VERSION 5.8 ;
BUSBITCHARS "[]" ;
DIVIDERCHAR "/" ;
UNITS
    DATABASE MICRONS 1000 ;
END UNITS

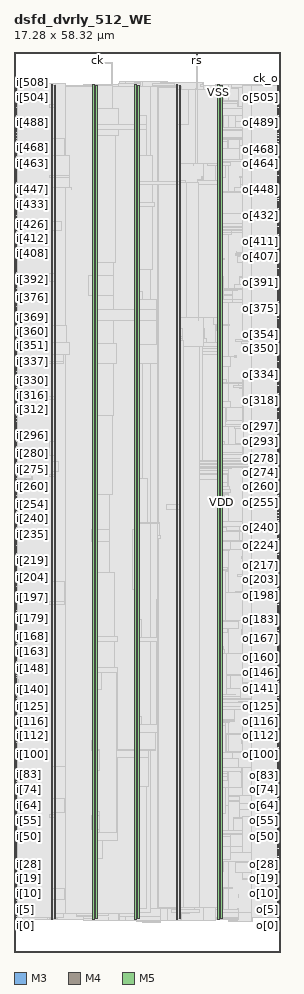
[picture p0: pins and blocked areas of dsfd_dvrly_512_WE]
MACRO dsfd_dvrly_512_WE
  FOREIGN dsfd_dvrly_512_WE 0 0 ;
  CLASS BLOCK ;
  SIZE 17.28 BY 58.32 ;
  PIN ck
    DIRECTION INPUT ;
    USE SIGNAL ;
    PORT
      LAYER M3 ;
        RECT  5.4 58.176 5.418 58.32 ;
    END
  END ck
  PIN ck_o
    DIRECTION OUTPUT ;
    USE SIGNAL ;
    PORT
      LAYER M4 ;
        RECT  17.088 56.112 17.28 56.136 ;
    END
  END ck_o
  PIN i[0]
    DIRECTION INPUT ;
    USE SIGNAL ;
    PORT
      LAYER M4 ;
        RECT  0 2.208 0.192 2.232 ;
    END
  END i[0]
  PIN i[100]
    DIRECTION INPUT ;
    USE SIGNAL ;
    PORT
      LAYER M4 ;
        RECT  0 12.768 0.192 12.792 ;
    END
  END i[100]
  PIN i[101]
    DIRECTION INPUT ;
    USE SIGNAL ;
    PORT
      LAYER M4 ;
        RECT  0 12.864 0.192 12.888 ;
    END
  END i[101]
  PIN i[102]
    DIRECTION INPUT ;
    USE SIGNAL ;
    PORT
      LAYER M4 ;
        RECT  0 12.96 0.192 12.984 ;
    END
  END i[102]
  PIN i[103]
    DIRECTION INPUT ;
    USE SIGNAL ;
    PORT
      LAYER M4 ;
        RECT  0 13.104 0.192 13.128 ;
    END
  END i[103]
  PIN i[104]
    DIRECTION INPUT ;
    USE SIGNAL ;
    PORT
      LAYER M4 ;
        RECT  0 13.2 0.192 13.224 ;
    END
  END i[104]
  PIN i[105]
    DIRECTION INPUT ;
    USE SIGNAL ;
    PORT
      LAYER M4 ;
        RECT  0 13.296 0.192 13.32 ;
    END
  END i[105]
  PIN i[106]
    DIRECTION INPUT ;
    USE SIGNAL ;
    PORT
      LAYER M4 ;
        RECT  0 13.392 0.192 13.416 ;
    END
  END i[106]
  PIN i[107]
    DIRECTION INPUT ;
    USE SIGNAL ;
    PORT
      LAYER M4 ;
        RECT  0 13.488 0.192 13.512 ;
    END
  END i[107]
  PIN i[108]
    DIRECTION INPUT ;
    USE SIGNAL ;
    PORT
      LAYER M4 ;
        RECT  0 13.632 0.192 13.656 ;
    END
  END i[108]
  PIN i[109]
    DIRECTION INPUT ;
    USE SIGNAL ;
    PORT
      LAYER M4 ;
        RECT  0 13.728 0.192 13.752 ;
    END
  END i[109]
  PIN i[10]
    DIRECTION INPUT ;
    USE SIGNAL ;
    PORT
      LAYER M4 ;
        RECT  0 3.264 0.192 3.288 ;
    END
  END i[10]
  PIN i[110]
    DIRECTION INPUT ;
    USE SIGNAL ;
    PORT
      LAYER M4 ;
        RECT  0 13.824 0.192 13.848 ;
    END
  END i[110]
  PIN i[111]
    DIRECTION INPUT ;
    USE SIGNAL ;
    PORT
      LAYER M4 ;
        RECT  0 13.92 0.192 13.944 ;
    END
  END i[111]
  PIN i[112]
    DIRECTION INPUT ;
    USE SIGNAL ;
    PORT
      LAYER M4 ;
        RECT  0 14.016 0.192 14.04 ;
    END
  END i[112]
  PIN i[113]
    DIRECTION INPUT ;
    USE SIGNAL ;
    PORT
      LAYER M4 ;
        RECT  0 14.16 0.192 14.184 ;
    END
  END i[113]
  PIN i[114]
    DIRECTION INPUT ;
    USE SIGNAL ;
    PORT
      LAYER M4 ;
        RECT  0 14.256 0.192 14.28 ;
    END
  END i[114]
  PIN i[115]
    DIRECTION INPUT ;
    USE SIGNAL ;
    PORT
      LAYER M4 ;
        RECT  0 14.352 0.192 14.376 ;
    END
  END i[115]
  PIN i[116]
    DIRECTION INPUT ;
    USE SIGNAL ;
    PORT
      LAYER M4 ;
        RECT  0 14.448 0.192 14.472 ;
    END
  END i[116]
  PIN i[117]
    DIRECTION INPUT ;
    USE SIGNAL ;
    PORT
      LAYER M4 ;
        RECT  0 14.544 0.192 14.568 ;
    END
  END i[117]
  PIN i[118]
    DIRECTION INPUT ;
    USE SIGNAL ;
    PORT
      LAYER M4 ;
        RECT  0 14.688 0.192 14.712 ;
    END
  END i[118]
  PIN i[119]
    DIRECTION INPUT ;
    USE SIGNAL ;
    PORT
      LAYER M4 ;
        RECT  0 14.784 0.192 14.808 ;
    END
  END i[119]
  PIN i[11]
    DIRECTION INPUT ;
    USE SIGNAL ;
    PORT
      LAYER M4 ;
        RECT  0 3.408 0.192 3.432 ;
    END
  END i[11]
  PIN i[120]
    DIRECTION INPUT ;
    USE SIGNAL ;
    PORT
      LAYER M4 ;
        RECT  0 14.88 0.192 14.904 ;
    END
  END i[120]
  PIN i[121]
    DIRECTION INPUT ;
    USE SIGNAL ;
    PORT
      LAYER M4 ;
        RECT  0 14.976 0.192 15 ;
    END
  END i[121]
  PIN i[122]
    DIRECTION INPUT ;
    USE SIGNAL ;
    PORT
      LAYER M4 ;
        RECT  0 15.072 0.192 15.096 ;
    END
  END i[122]
  PIN i[123]
    DIRECTION INPUT ;
    USE SIGNAL ;
    PORT
      LAYER M4 ;
        RECT  0 15.216 0.192 15.24 ;
    END
  END i[123]
  PIN i[124]
    DIRECTION INPUT ;
    USE SIGNAL ;
    PORT
      LAYER M4 ;
        RECT  0 15.312 0.192 15.336 ;
    END
  END i[124]
  PIN i[125]
    DIRECTION INPUT ;
    USE SIGNAL ;
    PORT
      LAYER M4 ;
        RECT  0 15.408 0.192 15.432 ;
    END
  END i[125]
  PIN i[126]
    DIRECTION INPUT ;
    USE SIGNAL ;
    PORT
      LAYER M4 ;
        RECT  0 15.504 0.192 15.528 ;
    END
  END i[126]
  PIN i[127]
    DIRECTION INPUT ;
    USE SIGNAL ;
    PORT
      LAYER M4 ;
        RECT  0 15.6 0.192 15.624 ;
    END
  END i[127]
  PIN i[128]
    DIRECTION INPUT ;
    USE SIGNAL ;
    PORT
      LAYER M4 ;
        RECT  0 15.744 0.192 15.768 ;
    END
  END i[128]
  PIN i[129]
    DIRECTION INPUT ;
    USE SIGNAL ;
    PORT
      LAYER M4 ;
        RECT  0 15.84 0.192 15.864 ;
    END
  END i[129]
  PIN i[12]
    DIRECTION INPUT ;
    USE SIGNAL ;
    PORT
      LAYER M4 ;
        RECT  0 3.504 0.192 3.528 ;
    END
  END i[12]
  PIN i[130]
    DIRECTION INPUT ;
    USE SIGNAL ;
    PORT
      LAYER M4 ;
        RECT  0 15.936 0.192 15.96 ;
    END
  END i[130]
  PIN i[131]
    DIRECTION INPUT ;
    USE SIGNAL ;
    PORT
      LAYER M4 ;
        RECT  0 16.032 0.192 16.056 ;
    END
  END i[131]
  PIN i[132]
    DIRECTION INPUT ;
    USE SIGNAL ;
    PORT
      LAYER M4 ;
        RECT  0 16.128 0.192 16.152 ;
    END
  END i[132]
  PIN i[133]
    DIRECTION INPUT ;
    USE SIGNAL ;
    PORT
      LAYER M4 ;
        RECT  0 16.272 0.192 16.296 ;
    END
  END i[133]
  PIN i[134]
    DIRECTION INPUT ;
    USE SIGNAL ;
    PORT
      LAYER M4 ;
        RECT  0 16.368 0.192 16.392 ;
    END
  END i[134]
  PIN i[135]
    DIRECTION INPUT ;
    USE SIGNAL ;
    PORT
      LAYER M4 ;
        RECT  0 16.464 0.192 16.488 ;
    END
  END i[135]
  PIN i[136]
    DIRECTION INPUT ;
    USE SIGNAL ;
    PORT
      LAYER M4 ;
        RECT  0 16.56 0.192 16.584 ;
    END
  END i[136]
  PIN i[137]
    DIRECTION INPUT ;
    USE SIGNAL ;
    PORT
      LAYER M4 ;
        RECT  0 16.656 0.192 16.68 ;
    END
  END i[137]
  PIN i[138]
    DIRECTION INPUT ;
    USE SIGNAL ;
    PORT
      LAYER M4 ;
        RECT  0 16.8 0.192 16.824 ;
    END
  END i[138]
  PIN i[139]
    DIRECTION INPUT ;
    USE SIGNAL ;
    PORT
      LAYER M4 ;
        RECT  0 16.896 0.192 16.92 ;
    END
  END i[139]
  PIN i[13]
    DIRECTION INPUT ;
    USE SIGNAL ;
    PORT
      LAYER M4 ;
        RECT  0 3.6 0.192 3.624 ;
    END
  END i[13]
  PIN i[140]
    DIRECTION INPUT ;
    USE SIGNAL ;
    PORT
      LAYER M4 ;
        RECT  0 16.992 0.192 17.016 ;
    END
  END i[140]
  PIN i[141]
    DIRECTION INPUT ;
    USE SIGNAL ;
    PORT
      LAYER M4 ;
        RECT  0 17.088 0.192 17.112 ;
    END
  END i[141]
  PIN i[142]
    DIRECTION INPUT ;
    USE SIGNAL ;
    PORT
      LAYER M4 ;
        RECT  0 17.184 0.192 17.208 ;
    END
  END i[142]
  PIN i[143]
    DIRECTION INPUT ;
    USE SIGNAL ;
    PORT
      LAYER M4 ;
        RECT  0 17.328 0.192 17.352 ;
    END
  END i[143]
  PIN i[144]
    DIRECTION INPUT ;
    USE SIGNAL ;
    PORT
      LAYER M4 ;
        RECT  0 17.424 0.192 17.448 ;
    END
  END i[144]
  PIN i[145]
    DIRECTION INPUT ;
    USE SIGNAL ;
    PORT
      LAYER M4 ;
        RECT  0 17.52 0.192 17.544 ;
    END
  END i[145]
  PIN i[146]
    DIRECTION INPUT ;
    USE SIGNAL ;
    PORT
      LAYER M4 ;
        RECT  0 17.616 0.192 17.64 ;
    END
  END i[146]
  PIN i[147]
    DIRECTION INPUT ;
    USE SIGNAL ;
    PORT
      LAYER M4 ;
        RECT  0 17.712 0.192 17.736 ;
    END
  END i[147]
  PIN i[148]
    DIRECTION INPUT ;
    USE SIGNAL ;
    PORT
      LAYER M4 ;
        RECT  0 17.856 0.192 17.88 ;
    END
  END i[148]
  PIN i[149]
    DIRECTION INPUT ;
    USE SIGNAL ;
    PORT
      LAYER M4 ;
        RECT  0 17.952 0.192 17.976 ;
    END
  END i[149]
  PIN i[14]
    DIRECTION INPUT ;
    USE SIGNAL ;
    PORT
      LAYER M4 ;
        RECT  0 3.696 0.192 3.72 ;
    END
  END i[14]
  PIN i[150]
    DIRECTION INPUT ;
    USE SIGNAL ;
    PORT
      LAYER M4 ;
        RECT  0 18.048 0.192 18.072 ;
    END
  END i[150]
  PIN i[151]
    DIRECTION INPUT ;
    USE SIGNAL ;
    PORT
      LAYER M4 ;
        RECT  0 18.144 0.192 18.168 ;
    END
  END i[151]
  PIN i[152]
    DIRECTION INPUT ;
    USE SIGNAL ;
    PORT
      LAYER M4 ;
        RECT  0 18.24 0.192 18.264 ;
    END
  END i[152]
  PIN i[153]
    DIRECTION INPUT ;
    USE SIGNAL ;
    PORT
      LAYER M4 ;
        RECT  0 18.384 0.192 18.408 ;
    END
  END i[153]
  PIN i[154]
    DIRECTION INPUT ;
    USE SIGNAL ;
    PORT
      LAYER M4 ;
        RECT  0 18.48 0.192 18.504 ;
    END
  END i[154]
  PIN i[155]
    DIRECTION INPUT ;
    USE SIGNAL ;
    PORT
      LAYER M4 ;
        RECT  0 18.576 0.192 18.6 ;
    END
  END i[155]
  PIN i[156]
    DIRECTION INPUT ;
    USE SIGNAL ;
    PORT
      LAYER M4 ;
        RECT  0 18.672 0.192 18.696 ;
    END
  END i[156]
  PIN i[157]
    DIRECTION INPUT ;
    USE SIGNAL ;
    PORT
      LAYER M4 ;
        RECT  0 18.768 0.192 18.792 ;
    END
  END i[157]
  PIN i[158]
    DIRECTION INPUT ;
    USE SIGNAL ;
    PORT
      LAYER M4 ;
        RECT  0 18.912 0.192 18.936 ;
    END
  END i[158]
  PIN i[159]
    DIRECTION INPUT ;
    USE SIGNAL ;
    PORT
      LAYER M4 ;
        RECT  0 19.008 0.192 19.032 ;
    END
  END i[159]
  PIN i[15]
    DIRECTION INPUT ;
    USE SIGNAL ;
    PORT
      LAYER M4 ;
        RECT  0 3.792 0.192 3.816 ;
    END
  END i[15]
  PIN i[160]
    DIRECTION INPUT ;
    USE SIGNAL ;
    PORT
      LAYER M4 ;
        RECT  0 19.104 0.192 19.128 ;
    END
  END i[160]
  PIN i[161]
    DIRECTION INPUT ;
    USE SIGNAL ;
    PORT
      LAYER M4 ;
        RECT  0 19.2 0.192 19.224 ;
    END
  END i[161]
  PIN i[162]
    DIRECTION INPUT ;
    USE SIGNAL ;
    PORT
      LAYER M4 ;
        RECT  0 19.296 0.192 19.32 ;
    END
  END i[162]
  PIN i[163]
    DIRECTION INPUT ;
    USE SIGNAL ;
    PORT
      LAYER M4 ;
        RECT  0 19.44 0.192 19.464 ;
    END
  END i[163]
  PIN i[164]
    DIRECTION INPUT ;
    USE SIGNAL ;
    PORT
      LAYER M4 ;
        RECT  0 19.536 0.192 19.56 ;
    END
  END i[164]
  PIN i[165]
    DIRECTION INPUT ;
    USE SIGNAL ;
    PORT
      LAYER M4 ;
        RECT  0 19.632 0.192 19.656 ;
    END
  END i[165]
  PIN i[166]
    DIRECTION INPUT ;
    USE SIGNAL ;
    PORT
      LAYER M4 ;
        RECT  0 19.728 0.192 19.752 ;
    END
  END i[166]
  PIN i[167]
    DIRECTION INPUT ;
    USE SIGNAL ;
    PORT
      LAYER M4 ;
        RECT  0 19.824 0.192 19.848 ;
    END
  END i[167]
  PIN i[168]
    DIRECTION INPUT ;
    USE SIGNAL ;
    PORT
      LAYER M4 ;
        RECT  0 19.92 0.192 19.944 ;
    END
  END i[168]
  PIN i[169]
    DIRECTION INPUT ;
    USE SIGNAL ;
    PORT
      LAYER M4 ;
        RECT  0 20.064 0.192 20.088 ;
    END
  END i[169]
  PIN i[16]
    DIRECTION INPUT ;
    USE SIGNAL ;
    PORT
      LAYER M4 ;
        RECT  0 3.936 0.192 3.96 ;
    END
  END i[16]
  PIN i[170]
    DIRECTION INPUT ;
    USE SIGNAL ;
    PORT
      LAYER M4 ;
        RECT  0 20.16 0.192 20.184 ;
    END
  END i[170]
  PIN i[171]
    DIRECTION INPUT ;
    USE SIGNAL ;
    PORT
      LAYER M4 ;
        RECT  0 20.256 0.192 20.28 ;
    END
  END i[171]
  PIN i[172]
    DIRECTION INPUT ;
    USE SIGNAL ;
    PORT
      LAYER M4 ;
        RECT  0 20.352 0.192 20.376 ;
    END
  END i[172]
  PIN i[173]
    DIRECTION INPUT ;
    USE SIGNAL ;
    PORT
      LAYER M4 ;
        RECT  0 20.448 0.192 20.472 ;
    END
  END i[173]
  PIN i[174]
    DIRECTION INPUT ;
    USE SIGNAL ;
    PORT
      LAYER M4 ;
        RECT  0 20.592 0.192 20.616 ;
    END
  END i[174]
  PIN i[175]
    DIRECTION INPUT ;
    USE SIGNAL ;
    PORT
      LAYER M4 ;
        RECT  0 20.688 0.192 20.712 ;
    END
  END i[175]
  PIN i[176]
    DIRECTION INPUT ;
    USE SIGNAL ;
    PORT
      LAYER M4 ;
        RECT  0 20.784 0.192 20.808 ;
    END
  END i[176]
  PIN i[177]
    DIRECTION INPUT ;
    USE SIGNAL ;
    PORT
      LAYER M4 ;
        RECT  0 20.88 0.192 20.904 ;
    END
  END i[177]
  PIN i[178]
    DIRECTION INPUT ;
    USE SIGNAL ;
    PORT
      LAYER M4 ;
        RECT  0 20.976 0.192 21 ;
    END
  END i[178]
  PIN i[179]
    DIRECTION INPUT ;
    USE SIGNAL ;
    PORT
      LAYER M4 ;
        RECT  0 21.12 0.192 21.144 ;
    END
  END i[179]
  PIN i[17]
    DIRECTION INPUT ;
    USE SIGNAL ;
    PORT
      LAYER M4 ;
        RECT  0 4.032 0.192 4.056 ;
    END
  END i[17]
  PIN i[180]
    DIRECTION INPUT ;
    USE SIGNAL ;
    PORT
      LAYER M4 ;
        RECT  0 21.216 0.192 21.24 ;
    END
  END i[180]
  PIN i[181]
    DIRECTION INPUT ;
    USE SIGNAL ;
    PORT
      LAYER M4 ;
        RECT  0 21.312 0.192 21.336 ;
    END
  END i[181]
  PIN i[182]
    DIRECTION INPUT ;
    USE SIGNAL ;
    PORT
      LAYER M4 ;
        RECT  0 21.408 0.192 21.432 ;
    END
  END i[182]
  PIN i[183]
    DIRECTION INPUT ;
    USE SIGNAL ;
    PORT
      LAYER M4 ;
        RECT  0 21.504 0.192 21.528 ;
    END
  END i[183]
  PIN i[184]
    DIRECTION INPUT ;
    USE SIGNAL ;
    PORT
      LAYER M4 ;
        RECT  0 21.648 0.192 21.672 ;
    END
  END i[184]
  PIN i[185]
    DIRECTION INPUT ;
    USE SIGNAL ;
    PORT
      LAYER M4 ;
        RECT  0 21.744 0.192 21.768 ;
    END
  END i[185]
  PIN i[186]
    DIRECTION INPUT ;
    USE SIGNAL ;
    PORT
      LAYER M4 ;
        RECT  0 21.84 0.192 21.864 ;
    END
  END i[186]
  PIN i[187]
    DIRECTION INPUT ;
    USE SIGNAL ;
    PORT
      LAYER M4 ;
        RECT  0 21.936 0.192 21.96 ;
    END
  END i[187]
  PIN i[188]
    DIRECTION INPUT ;
    USE SIGNAL ;
    PORT
      LAYER M4 ;
        RECT  0 22.032 0.192 22.056 ;
    END
  END i[188]
  PIN i[189]
    DIRECTION INPUT ;
    USE SIGNAL ;
    PORT
      LAYER M4 ;
        RECT  0 22.176 0.192 22.2 ;
    END
  END i[189]
  PIN i[18]
    DIRECTION INPUT ;
    USE SIGNAL ;
    PORT
      LAYER M4 ;
        RECT  0 4.128 0.192 4.152 ;
    END
  END i[18]
  PIN i[190]
    DIRECTION INPUT ;
    USE SIGNAL ;
    PORT
      LAYER M4 ;
        RECT  0 22.272 0.192 22.296 ;
    END
  END i[190]
  PIN i[191]
    DIRECTION INPUT ;
    USE SIGNAL ;
    PORT
      LAYER M4 ;
        RECT  0 22.368 0.192 22.392 ;
    END
  END i[191]
  PIN i[192]
    DIRECTION INPUT ;
    USE SIGNAL ;
    PORT
      LAYER M4 ;
        RECT  0 22.464 0.192 22.488 ;
    END
  END i[192]
  PIN i[193]
    DIRECTION INPUT ;
    USE SIGNAL ;
    PORT
      LAYER M4 ;
        RECT  0 22.56 0.192 22.584 ;
    END
  END i[193]
  PIN i[194]
    DIRECTION INPUT ;
    USE SIGNAL ;
    PORT
      LAYER M4 ;
        RECT  0 22.704 0.192 22.728 ;
    END
  END i[194]
  PIN i[195]
    DIRECTION INPUT ;
    USE SIGNAL ;
    PORT
      LAYER M4 ;
        RECT  0 22.8 0.192 22.824 ;
    END
  END i[195]
  PIN i[196]
    DIRECTION INPUT ;
    USE SIGNAL ;
    PORT
      LAYER M4 ;
        RECT  0 22.896 0.192 22.92 ;
    END
  END i[196]
  PIN i[197]
    DIRECTION INPUT ;
    USE SIGNAL ;
    PORT
      LAYER M4 ;
        RECT  0 22.992 0.192 23.016 ;
    END
  END i[197]
  PIN i[198]
    DIRECTION INPUT ;
    USE SIGNAL ;
    PORT
      LAYER M4 ;
        RECT  0 23.088 0.192 23.112 ;
    END
  END i[198]
  PIN i[199]
    DIRECTION INPUT ;
    USE SIGNAL ;
    PORT
      LAYER M4 ;
        RECT  0 23.232 0.192 23.256 ;
    END
  END i[199]
  PIN i[19]
    DIRECTION INPUT ;
    USE SIGNAL ;
    PORT
      LAYER M4 ;
        RECT  0 4.224 0.192 4.248 ;
    END
  END i[19]
  PIN i[1]
    DIRECTION INPUT ;
    USE SIGNAL ;
    PORT
      LAYER M4 ;
        RECT  0 2.352 0.192 2.376 ;
    END
  END i[1]
  PIN i[200]
    DIRECTION INPUT ;
    USE SIGNAL ;
    PORT
      LAYER M4 ;
        RECT  0 23.328 0.192 23.352 ;
    END
  END i[200]
  PIN i[201]
    DIRECTION INPUT ;
    USE SIGNAL ;
    PORT
      LAYER M4 ;
        RECT  0 23.424 0.192 23.448 ;
    END
  END i[201]
  PIN i[202]
    DIRECTION INPUT ;
    USE SIGNAL ;
    PORT
      LAYER M4 ;
        RECT  0 23.52 0.192 23.544 ;
    END
  END i[202]
  PIN i[203]
    DIRECTION INPUT ;
    USE SIGNAL ;
    PORT
      LAYER M4 ;
        RECT  0 23.616 0.192 23.64 ;
    END
  END i[203]
  PIN i[204]
    DIRECTION INPUT ;
    USE SIGNAL ;
    PORT
      LAYER M4 ;
        RECT  0 23.76 0.192 23.784 ;
    END
  END i[204]
  PIN i[205]
    DIRECTION INPUT ;
    USE SIGNAL ;
    PORT
      LAYER M4 ;
        RECT  0 23.856 0.192 23.88 ;
    END
  END i[205]
  PIN i[206]
    DIRECTION INPUT ;
    USE SIGNAL ;
    PORT
      LAYER M4 ;
        RECT  0 23.952 0.192 23.976 ;
    END
  END i[206]
  PIN i[207]
    DIRECTION INPUT ;
    USE SIGNAL ;
    PORT
      LAYER M4 ;
        RECT  0 24.048 0.192 24.072 ;
    END
  END i[207]
  PIN i[208]
    DIRECTION INPUT ;
    USE SIGNAL ;
    PORT
      LAYER M4 ;
        RECT  0 24.144 0.192 24.168 ;
    END
  END i[208]
  PIN i[209]
    DIRECTION INPUT ;
    USE SIGNAL ;
    PORT
      LAYER M4 ;
        RECT  0 24.288 0.192 24.312 ;
    END
  END i[209]
  PIN i[20]
    DIRECTION INPUT ;
    USE SIGNAL ;
    PORT
      LAYER M4 ;
        RECT  0 4.32 0.192 4.344 ;
    END
  END i[20]
  PIN i[210]
    DIRECTION INPUT ;
    USE SIGNAL ;
    PORT
      LAYER M4 ;
        RECT  0 24.384 0.192 24.408 ;
    END
  END i[210]
  PIN i[211]
    DIRECTION INPUT ;
    USE SIGNAL ;
    PORT
      LAYER M4 ;
        RECT  0 24.48 0.192 24.504 ;
    END
  END i[211]
  PIN i[212]
    DIRECTION INPUT ;
    USE SIGNAL ;
    PORT
      LAYER M4 ;
        RECT  0 24.576 0.192 24.6 ;
    END
  END i[212]
  PIN i[213]
    DIRECTION INPUT ;
    USE SIGNAL ;
    PORT
      LAYER M4 ;
        RECT  0 24.672 0.192 24.696 ;
    END
  END i[213]
  PIN i[214]
    DIRECTION INPUT ;
    USE SIGNAL ;
    PORT
      LAYER M4 ;
        RECT  0 24.816 0.192 24.84 ;
    END
  END i[214]
  PIN i[215]
    DIRECTION INPUT ;
    USE SIGNAL ;
    PORT
      LAYER M4 ;
        RECT  0 24.912 0.192 24.936 ;
    END
  END i[215]
  PIN i[216]
    DIRECTION INPUT ;
    USE SIGNAL ;
    PORT
      LAYER M4 ;
        RECT  0 25.008 0.192 25.032 ;
    END
  END i[216]
  PIN i[217]
    DIRECTION INPUT ;
    USE SIGNAL ;
    PORT
      LAYER M4 ;
        RECT  0 25.104 0.192 25.128 ;
    END
  END i[217]
  PIN i[218]
    DIRECTION INPUT ;
    USE SIGNAL ;
    PORT
      LAYER M4 ;
        RECT  0 25.2 0.192 25.224 ;
    END
  END i[218]
  PIN i[219]
    DIRECTION INPUT ;
    USE SIGNAL ;
    PORT
      LAYER M4 ;
        RECT  0 25.344 0.192 25.368 ;
    END
  END i[219]
  PIN i[21]
    DIRECTION INPUT ;
    USE SIGNAL ;
    PORT
      LAYER M4 ;
        RECT  0 4.416 0.192 4.44 ;
    END
  END i[21]
  PIN i[220]
    DIRECTION INPUT ;
    USE SIGNAL ;
    PORT
      LAYER M4 ;
        RECT  0 25.44 0.192 25.464 ;
    END
  END i[220]
  PIN i[221]
    DIRECTION INPUT ;
    USE SIGNAL ;
    PORT
      LAYER M4 ;
        RECT  0 25.536 0.192 25.56 ;
    END
  END i[221]
  PIN i[222]
    DIRECTION INPUT ;
    USE SIGNAL ;
    PORT
      LAYER M4 ;
        RECT  0 25.632 0.192 25.656 ;
    END
  END i[222]
  PIN i[223]
    DIRECTION INPUT ;
    USE SIGNAL ;
    PORT
      LAYER M4 ;
        RECT  0 25.728 0.192 25.752 ;
    END
  END i[223]
  PIN i[224]
    DIRECTION INPUT ;
    USE SIGNAL ;
    PORT
      LAYER M4 ;
        RECT  0 25.872 0.192 25.896 ;
    END
  END i[224]
  PIN i[225]
    DIRECTION INPUT ;
    USE SIGNAL ;
    PORT
      LAYER M4 ;
        RECT  0 25.968 0.192 25.992 ;
    END
  END i[225]
  PIN i[226]
    DIRECTION INPUT ;
    USE SIGNAL ;
    PORT
      LAYER M4 ;
        RECT  0 26.064 0.192 26.088 ;
    END
  END i[226]
  PIN i[227]
    DIRECTION INPUT ;
    USE SIGNAL ;
    PORT
      LAYER M4 ;
        RECT  0 26.16 0.192 26.184 ;
    END
  END i[227]
  PIN i[228]
    DIRECTION INPUT ;
    USE SIGNAL ;
    PORT
      LAYER M4 ;
        RECT  0 26.256 0.192 26.28 ;
    END
  END i[228]
  PIN i[229]
    DIRECTION INPUT ;
    USE SIGNAL ;
    PORT
      LAYER M4 ;
        RECT  0 26.4 0.192 26.424 ;
    END
  END i[229]
  PIN i[22]
    DIRECTION INPUT ;
    USE SIGNAL ;
    PORT
      LAYER M4 ;
        RECT  0 4.56 0.192 4.584 ;
    END
  END i[22]
  PIN i[230]
    DIRECTION INPUT ;
    USE SIGNAL ;
    PORT
      LAYER M4 ;
        RECT  0 26.496 0.192 26.52 ;
    END
  END i[230]
  PIN i[231]
    DIRECTION INPUT ;
    USE SIGNAL ;
    PORT
      LAYER M4 ;
        RECT  0 26.592 0.192 26.616 ;
    END
  END i[231]
  PIN i[232]
    DIRECTION INPUT ;
    USE SIGNAL ;
    PORT
      LAYER M4 ;
        RECT  0 26.688 0.192 26.712 ;
    END
  END i[232]
  PIN i[233]
    DIRECTION INPUT ;
    USE SIGNAL ;
    PORT
      LAYER M4 ;
        RECT  0 26.784 0.192 26.808 ;
    END
  END i[233]
  PIN i[234]
    DIRECTION INPUT ;
    USE SIGNAL ;
    PORT
      LAYER M4 ;
        RECT  0 26.928 0.192 26.952 ;
    END
  END i[234]
  PIN i[235]
    DIRECTION INPUT ;
    USE SIGNAL ;
    PORT
      LAYER M4 ;
        RECT  0 27.024 0.192 27.048 ;
    END
  END i[235]
  PIN i[236]
    DIRECTION INPUT ;
    USE SIGNAL ;
    PORT
      LAYER M4 ;
        RECT  0 27.12 0.192 27.144 ;
    END
  END i[236]
  PIN i[237]
    DIRECTION INPUT ;
    USE SIGNAL ;
    PORT
      LAYER M4 ;
        RECT  0 27.216 0.192 27.24 ;
    END
  END i[237]
  PIN i[238]
    DIRECTION INPUT ;
    USE SIGNAL ;
    PORT
      LAYER M4 ;
        RECT  0 27.312 0.192 27.336 ;
    END
  END i[238]
  PIN i[239]
    DIRECTION INPUT ;
    USE SIGNAL ;
    PORT
      LAYER M4 ;
        RECT  0 27.408 0.192 27.432 ;
    END
  END i[239]
  PIN i[23]
    DIRECTION INPUT ;
    USE SIGNAL ;
    PORT
      LAYER M4 ;
        RECT  0 4.656 0.192 4.68 ;
    END
  END i[23]
  PIN i[240]
    DIRECTION INPUT ;
    USE SIGNAL ;
    PORT
      LAYER M4 ;
        RECT  0 27.552 0.192 27.576 ;
    END
  END i[240]
  PIN i[241]
    DIRECTION INPUT ;
    USE SIGNAL ;
    PORT
      LAYER M4 ;
        RECT  0 27.648 0.192 27.672 ;
    END
  END i[241]
  PIN i[242]
    DIRECTION INPUT ;
    USE SIGNAL ;
    PORT
      LAYER M4 ;
        RECT  0 27.744 0.192 27.768 ;
    END
  END i[242]
  PIN i[243]
    DIRECTION INPUT ;
    USE SIGNAL ;
    PORT
      LAYER M4 ;
        RECT  0 27.84 0.192 27.864 ;
    END
  END i[243]
  PIN i[244]
    DIRECTION INPUT ;
    USE SIGNAL ;
    PORT
      LAYER M4 ;
        RECT  0 27.936 0.192 27.96 ;
    END
  END i[244]
  PIN i[245]
    DIRECTION INPUT ;
    USE SIGNAL ;
    PORT
      LAYER M4 ;
        RECT  0 28.08 0.192 28.104 ;
    END
  END i[245]
  PIN i[246]
    DIRECTION INPUT ;
    USE SIGNAL ;
    PORT
      LAYER M4 ;
        RECT  0 28.176 0.192 28.2 ;
    END
  END i[246]
  PIN i[247]
    DIRECTION INPUT ;
    USE SIGNAL ;
    PORT
      LAYER M4 ;
        RECT  0 28.272 0.192 28.296 ;
    END
  END i[247]
  PIN i[248]
    DIRECTION INPUT ;
    USE SIGNAL ;
    PORT
      LAYER M4 ;
        RECT  0 28.368 0.192 28.392 ;
    END
  END i[248]
  PIN i[249]
    DIRECTION INPUT ;
    USE SIGNAL ;
    PORT
      LAYER M4 ;
        RECT  0 28.464 0.192 28.488 ;
    END
  END i[249]
  PIN i[24]
    DIRECTION INPUT ;
    USE SIGNAL ;
    PORT
      LAYER M4 ;
        RECT  0 4.752 0.192 4.776 ;
    END
  END i[24]
  PIN i[250]
    DIRECTION INPUT ;
    USE SIGNAL ;
    PORT
      LAYER M4 ;
        RECT  0 28.608 0.192 28.632 ;
    END
  END i[250]
  PIN i[251]
    DIRECTION INPUT ;
    USE SIGNAL ;
    PORT
      LAYER M4 ;
        RECT  0 28.704 0.192 28.728 ;
    END
  END i[251]
  PIN i[252]
    DIRECTION INPUT ;
    USE SIGNAL ;
    PORT
      LAYER M4 ;
        RECT  0 28.8 0.192 28.824 ;
    END
  END i[252]
  PIN i[253]
    DIRECTION INPUT ;
    USE SIGNAL ;
    PORT
      LAYER M4 ;
        RECT  0 28.896 0.192 28.92 ;
    END
  END i[253]
  PIN i[254]
    DIRECTION INPUT ;
    USE SIGNAL ;
    PORT
      LAYER M4 ;
        RECT  0 28.992 0.192 29.016 ;
    END
  END i[254]
  PIN i[255]
    DIRECTION INPUT ;
    USE SIGNAL ;
    PORT
      LAYER M4 ;
        RECT  0 29.136 0.192 29.16 ;
    END
  END i[255]
  PIN i[256]
    DIRECTION INPUT ;
    USE SIGNAL ;
    PORT
      LAYER M4 ;
        RECT  0 29.232 0.192 29.256 ;
    END
  END i[256]
  PIN i[257]
    DIRECTION INPUT ;
    USE SIGNAL ;
    PORT
      LAYER M4 ;
        RECT  0 29.328 0.192 29.352 ;
    END
  END i[257]
  PIN i[258]
    DIRECTION INPUT ;
    USE SIGNAL ;
    PORT
      LAYER M4 ;
        RECT  0 29.424 0.192 29.448 ;
    END
  END i[258]
  PIN i[259]
    DIRECTION INPUT ;
    USE SIGNAL ;
    PORT
      LAYER M4 ;
        RECT  0 29.52 0.192 29.544 ;
    END
  END i[259]
  PIN i[25]
    DIRECTION INPUT ;
    USE SIGNAL ;
    PORT
      LAYER M4 ;
        RECT  0 4.848 0.192 4.872 ;
    END
  END i[25]
  PIN i[260]
    DIRECTION INPUT ;
    USE SIGNAL ;
    PORT
      LAYER M4 ;
        RECT  0 29.664 0.192 29.688 ;
    END
  END i[260]
  PIN i[261]
    DIRECTION INPUT ;
    USE SIGNAL ;
    PORT
      LAYER M4 ;
        RECT  0 29.76 0.192 29.784 ;
    END
  END i[261]
  PIN i[262]
    DIRECTION INPUT ;
    USE SIGNAL ;
    PORT
      LAYER M4 ;
        RECT  0 29.856 0.192 29.88 ;
    END
  END i[262]
  PIN i[263]
    DIRECTION INPUT ;
    USE SIGNAL ;
    PORT
      LAYER M4 ;
        RECT  0 29.952 0.192 29.976 ;
    END
  END i[263]
  PIN i[264]
    DIRECTION INPUT ;
    USE SIGNAL ;
    PORT
      LAYER M4 ;
        RECT  0 30.048 0.192 30.072 ;
    END
  END i[264]
  PIN i[265]
    DIRECTION INPUT ;
    USE SIGNAL ;
    PORT
      LAYER M4 ;
        RECT  0 30.192 0.192 30.216 ;
    END
  END i[265]
  PIN i[266]
    DIRECTION INPUT ;
    USE SIGNAL ;
    PORT
      LAYER M4 ;
        RECT  0 30.288 0.192 30.312 ;
    END
  END i[266]
  PIN i[267]
    DIRECTION INPUT ;
    USE SIGNAL ;
    PORT
      LAYER M4 ;
        RECT  0 30.384 0.192 30.408 ;
    END
  END i[267]
  PIN i[268]
    DIRECTION INPUT ;
    USE SIGNAL ;
    PORT
      LAYER M4 ;
        RECT  0 30.48 0.192 30.504 ;
    END
  END i[268]
  PIN i[269]
    DIRECTION INPUT ;
    USE SIGNAL ;
    PORT
      LAYER M4 ;
        RECT  0 30.576 0.192 30.6 ;
    END
  END i[269]
  PIN i[26]
    DIRECTION INPUT ;
    USE SIGNAL ;
    PORT
      LAYER M4 ;
        RECT  0 4.944 0.192 4.968 ;
    END
  END i[26]
  PIN i[270]
    DIRECTION INPUT ;
    USE SIGNAL ;
    PORT
      LAYER M4 ;
        RECT  0 30.72 0.192 30.744 ;
    END
  END i[270]
  PIN i[271]
    DIRECTION INPUT ;
    USE SIGNAL ;
    PORT
      LAYER M4 ;
        RECT  0 30.816 0.192 30.84 ;
    END
  END i[271]
  PIN i[272]
    DIRECTION INPUT ;
    USE SIGNAL ;
    PORT
      LAYER M4 ;
        RECT  0 30.912 0.192 30.936 ;
    END
  END i[272]
  PIN i[273]
    DIRECTION INPUT ;
    USE SIGNAL ;
    PORT
      LAYER M4 ;
        RECT  0 31.008 0.192 31.032 ;
    END
  END i[273]
  PIN i[274]
    DIRECTION INPUT ;
    USE SIGNAL ;
    PORT
      LAYER M4 ;
        RECT  0 31.104 0.192 31.128 ;
    END
  END i[274]
  PIN i[275]
    DIRECTION INPUT ;
    USE SIGNAL ;
    PORT
      LAYER M4 ;
        RECT  0 31.248 0.192 31.272 ;
    END
  END i[275]
  PIN i[276]
    DIRECTION INPUT ;
    USE SIGNAL ;
    PORT
      LAYER M4 ;
        RECT  0 31.344 0.192 31.368 ;
    END
  END i[276]
  PIN i[277]
    DIRECTION INPUT ;
    USE SIGNAL ;
    PORT
      LAYER M4 ;
        RECT  0 31.44 0.192 31.464 ;
    END
  END i[277]
  PIN i[278]
    DIRECTION INPUT ;
    USE SIGNAL ;
    PORT
      LAYER M4 ;
        RECT  0 31.536 0.192 31.56 ;
    END
  END i[278]
  PIN i[279]
    DIRECTION INPUT ;
    USE SIGNAL ;
    PORT
      LAYER M4 ;
        RECT  0 31.632 0.192 31.656 ;
    END
  END i[279]
  PIN i[27]
    DIRECTION INPUT ;
    USE SIGNAL ;
    PORT
      LAYER M4 ;
        RECT  0 5.088 0.192 5.112 ;
    END
  END i[27]
  PIN i[280]
    DIRECTION INPUT ;
    USE SIGNAL ;
    PORT
      LAYER M4 ;
        RECT  0 31.776 0.192 31.8 ;
    END
  END i[280]
  PIN i[281]
    DIRECTION INPUT ;
    USE SIGNAL ;
    PORT
      LAYER M4 ;
        RECT  0 31.872 0.192 31.896 ;
    END
  END i[281]
  PIN i[282]
    DIRECTION INPUT ;
    USE SIGNAL ;
    PORT
      LAYER M4 ;
        RECT  0 31.968 0.192 31.992 ;
    END
  END i[282]
  PIN i[283]
    DIRECTION INPUT ;
    USE SIGNAL ;
    PORT
      LAYER M4 ;
        RECT  0 32.064 0.192 32.088 ;
    END
  END i[283]
  PIN i[284]
    DIRECTION INPUT ;
    USE SIGNAL ;
    PORT
      LAYER M4 ;
        RECT  0 32.16 0.192 32.184 ;
    END
  END i[284]
  PIN i[285]
    DIRECTION INPUT ;
    USE SIGNAL ;
    PORT
      LAYER M4 ;
        RECT  0 32.304 0.192 32.328 ;
    END
  END i[285]
  PIN i[286]
    DIRECTION INPUT ;
    USE SIGNAL ;
    PORT
      LAYER M4 ;
        RECT  0 32.4 0.192 32.424 ;
    END
  END i[286]
  PIN i[287]
    DIRECTION INPUT ;
    USE SIGNAL ;
    PORT
      LAYER M4 ;
        RECT  0 32.496 0.192 32.52 ;
    END
  END i[287]
  PIN i[288]
    DIRECTION INPUT ;
    USE SIGNAL ;
    PORT
      LAYER M4 ;
        RECT  0 32.592 0.192 32.616 ;
    END
  END i[288]
  PIN i[289]
    DIRECTION INPUT ;
    USE SIGNAL ;
    PORT
      LAYER M4 ;
        RECT  0 32.688 0.192 32.712 ;
    END
  END i[289]
  PIN i[28]
    DIRECTION INPUT ;
    USE SIGNAL ;
    PORT
      LAYER M4 ;
        RECT  0 5.184 0.192 5.208 ;
    END
  END i[28]
  PIN i[290]
    DIRECTION INPUT ;
    USE SIGNAL ;
    PORT
      LAYER M4 ;
        RECT  0 32.832 0.192 32.856 ;
    END
  END i[290]
  PIN i[291]
    DIRECTION INPUT ;
    USE SIGNAL ;
    PORT
      LAYER M4 ;
        RECT  0 32.928 0.192 32.952 ;
    END
  END i[291]
  PIN i[292]
    DIRECTION INPUT ;
    USE SIGNAL ;
    PORT
      LAYER M4 ;
        RECT  0 33.024 0.192 33.048 ;
    END
  END i[292]
  PIN i[293]
    DIRECTION INPUT ;
    USE SIGNAL ;
    PORT
      LAYER M4 ;
        RECT  0 33.12 0.192 33.144 ;
    END
  END i[293]
  PIN i[294]
    DIRECTION INPUT ;
    USE SIGNAL ;
    PORT
      LAYER M4 ;
        RECT  0 33.216 0.192 33.24 ;
    END
  END i[294]
  PIN i[295]
    DIRECTION INPUT ;
    USE SIGNAL ;
    PORT
      LAYER M4 ;
        RECT  0 33.36 0.192 33.384 ;
    END
  END i[295]
  PIN i[296]
    DIRECTION INPUT ;
    USE SIGNAL ;
    PORT
      LAYER M4 ;
        RECT  0 33.456 0.192 33.48 ;
    END
  END i[296]
  PIN i[297]
    DIRECTION INPUT ;
    USE SIGNAL ;
    PORT
      LAYER M4 ;
        RECT  0 33.552 0.192 33.576 ;
    END
  END i[297]
  PIN i[298]
    DIRECTION INPUT ;
    USE SIGNAL ;
    PORT
      LAYER M4 ;
        RECT  0 33.648 0.192 33.672 ;
    END
  END i[298]
  PIN i[299]
    DIRECTION INPUT ;
    USE SIGNAL ;
    PORT
      LAYER M4 ;
        RECT  0 33.744 0.192 33.768 ;
    END
  END i[299]
  PIN i[29]
    DIRECTION INPUT ;
    USE SIGNAL ;
    PORT
      LAYER M4 ;
        RECT  0 5.28 0.192 5.304 ;
    END
  END i[29]
  PIN i[2]
    DIRECTION INPUT ;
    USE SIGNAL ;
    PORT
      LAYER M4 ;
        RECT  0 2.448 0.192 2.472 ;
    END
  END i[2]
  PIN i[300]
    DIRECTION INPUT ;
    USE SIGNAL ;
    PORT
      LAYER M4 ;
        RECT  0 33.888 0.192 33.912 ;
    END
  END i[300]
  PIN i[301]
    DIRECTION INPUT ;
    USE SIGNAL ;
    PORT
      LAYER M4 ;
        RECT  0 33.984 0.192 34.008 ;
    END
  END i[301]
  PIN i[302]
    DIRECTION INPUT ;
    USE SIGNAL ;
    PORT
      LAYER M4 ;
        RECT  0 34.08 0.192 34.104 ;
    END
  END i[302]
  PIN i[303]
    DIRECTION INPUT ;
    USE SIGNAL ;
    PORT
      LAYER M4 ;
        RECT  0 34.176 0.192 34.2 ;
    END
  END i[303]
  PIN i[304]
    DIRECTION INPUT ;
    USE SIGNAL ;
    PORT
      LAYER M4 ;
        RECT  0 34.272 0.192 34.296 ;
    END
  END i[304]
  PIN i[305]
    DIRECTION INPUT ;
    USE SIGNAL ;
    PORT
      LAYER M4 ;
        RECT  0 34.416 0.192 34.44 ;
    END
  END i[305]
  PIN i[306]
    DIRECTION INPUT ;
    USE SIGNAL ;
    PORT
      LAYER M4 ;
        RECT  0 34.512 0.192 34.536 ;
    END
  END i[306]
  PIN i[307]
    DIRECTION INPUT ;
    USE SIGNAL ;
    PORT
      LAYER M4 ;
        RECT  0 34.608 0.192 34.632 ;
    END
  END i[307]
  PIN i[308]
    DIRECTION INPUT ;
    USE SIGNAL ;
    PORT
      LAYER M4 ;
        RECT  0 34.704 0.192 34.728 ;
    END
  END i[308]
  PIN i[309]
    DIRECTION INPUT ;
    USE SIGNAL ;
    PORT
      LAYER M4 ;
        RECT  0 34.8 0.192 34.824 ;
    END
  END i[309]
  PIN i[30]
    DIRECTION INPUT ;
    USE SIGNAL ;
    PORT
      LAYER M4 ;
        RECT  0 5.376 0.192 5.4 ;
    END
  END i[30]
  PIN i[310]
    DIRECTION INPUT ;
    USE SIGNAL ;
    PORT
      LAYER M4 ;
        RECT  0 34.944 0.192 34.968 ;
    END
  END i[310]
  PIN i[311]
    DIRECTION INPUT ;
    USE SIGNAL ;
    PORT
      LAYER M4 ;
        RECT  0 35.04 0.192 35.064 ;
    END
  END i[311]
  PIN i[312]
    DIRECTION INPUT ;
    USE SIGNAL ;
    PORT
      LAYER M4 ;
        RECT  0 35.136 0.192 35.16 ;
    END
  END i[312]
  PIN i[313]
    DIRECTION INPUT ;
    USE SIGNAL ;
    PORT
      LAYER M4 ;
        RECT  0 35.232 0.192 35.256 ;
    END
  END i[313]
  PIN i[314]
    DIRECTION INPUT ;
    USE SIGNAL ;
    PORT
      LAYER M4 ;
        RECT  0 35.328 0.192 35.352 ;
    END
  END i[314]
  PIN i[315]
    DIRECTION INPUT ;
    USE SIGNAL ;
    PORT
      LAYER M4 ;
        RECT  0 35.424 0.192 35.448 ;
    END
  END i[315]
  PIN i[316]
    DIRECTION INPUT ;
    USE SIGNAL ;
    PORT
      LAYER M4 ;
        RECT  0 35.568 0.192 35.592 ;
    END
  END i[316]
  PIN i[317]
    DIRECTION INPUT ;
    USE SIGNAL ;
    PORT
      LAYER M4 ;
        RECT  0 35.664 0.192 35.688 ;
    END
  END i[317]
  PIN i[318]
    DIRECTION INPUT ;
    USE SIGNAL ;
    PORT
      LAYER M4 ;
        RECT  0 35.76 0.192 35.784 ;
    END
  END i[318]
  PIN i[319]
    DIRECTION INPUT ;
    USE SIGNAL ;
    PORT
      LAYER M4 ;
        RECT  0 35.856 0.192 35.88 ;
    END
  END i[319]
  PIN i[31]
    DIRECTION INPUT ;
    USE SIGNAL ;
    PORT
      LAYER M4 ;
        RECT  0 5.472 0.192 5.496 ;
    END
  END i[31]
  PIN i[320]
    DIRECTION INPUT ;
    USE SIGNAL ;
    PORT
      LAYER M4 ;
        RECT  0 35.952 0.192 35.976 ;
    END
  END i[320]
  PIN i[321]
    DIRECTION INPUT ;
    USE SIGNAL ;
    PORT
      LAYER M4 ;
        RECT  0 36.096 0.192 36.12 ;
    END
  END i[321]
  PIN i[322]
    DIRECTION INPUT ;
    USE SIGNAL ;
    PORT
      LAYER M4 ;
        RECT  0 36.192 0.192 36.216 ;
    END
  END i[322]
  PIN i[323]
    DIRECTION INPUT ;
    USE SIGNAL ;
    PORT
      LAYER M4 ;
        RECT  0 36.288 0.192 36.312 ;
    END
  END i[323]
  PIN i[324]
    DIRECTION INPUT ;
    USE SIGNAL ;
    PORT
      LAYER M4 ;
        RECT  0 36.384 0.192 36.408 ;
    END
  END i[324]
  PIN i[325]
    DIRECTION INPUT ;
    USE SIGNAL ;
    PORT
      LAYER M4 ;
        RECT  0 36.48 0.192 36.504 ;
    END
  END i[325]
  PIN i[326]
    DIRECTION INPUT ;
    USE SIGNAL ;
    PORT
      LAYER M4 ;
        RECT  0 36.624 0.192 36.648 ;
    END
  END i[326]
  PIN i[327]
    DIRECTION INPUT ;
    USE SIGNAL ;
    PORT
      LAYER M4 ;
        RECT  0 36.72 0.192 36.744 ;
    END
  END i[327]
  PIN i[328]
    DIRECTION INPUT ;
    USE SIGNAL ;
    PORT
      LAYER M4 ;
        RECT  0 36.816 0.192 36.84 ;
    END
  END i[328]
  PIN i[329]
    DIRECTION INPUT ;
    USE SIGNAL ;
    PORT
      LAYER M4 ;
        RECT  0 36.912 0.192 36.936 ;
    END
  END i[329]
  PIN i[32]
    DIRECTION INPUT ;
    USE SIGNAL ;
    PORT
      LAYER M4 ;
        RECT  0 5.616 0.192 5.64 ;
    END
  END i[32]
  PIN i[330]
    DIRECTION INPUT ;
    USE SIGNAL ;
    PORT
      LAYER M4 ;
        RECT  0 37.008 0.192 37.032 ;
    END
  END i[330]
  PIN i[331]
    DIRECTION INPUT ;
    USE SIGNAL ;
    PORT
      LAYER M4 ;
        RECT  0 37.152 0.192 37.176 ;
    END
  END i[331]
  PIN i[332]
    DIRECTION INPUT ;
    USE SIGNAL ;
    PORT
      LAYER M4 ;
        RECT  0 37.248 0.192 37.272 ;
    END
  END i[332]
  PIN i[333]
    DIRECTION INPUT ;
    USE SIGNAL ;
    PORT
      LAYER M4 ;
        RECT  0 37.344 0.192 37.368 ;
    END
  END i[333]
  PIN i[334]
    DIRECTION INPUT ;
    USE SIGNAL ;
    PORT
      LAYER M4 ;
        RECT  0 37.44 0.192 37.464 ;
    END
  END i[334]
  PIN i[335]
    DIRECTION INPUT ;
    USE SIGNAL ;
    PORT
      LAYER M4 ;
        RECT  0 37.536 0.192 37.56 ;
    END
  END i[335]
  PIN i[336]
    DIRECTION INPUT ;
    USE SIGNAL ;
    PORT
      LAYER M4 ;
        RECT  0 37.68 0.192 37.704 ;
    END
  END i[336]
  PIN i[337]
    DIRECTION INPUT ;
    USE SIGNAL ;
    PORT
      LAYER M4 ;
        RECT  0 37.776 0.192 37.8 ;
    END
  END i[337]
  PIN i[338]
    DIRECTION INPUT ;
    USE SIGNAL ;
    PORT
      LAYER M4 ;
        RECT  0 37.872 0.192 37.896 ;
    END
  END i[338]
  PIN i[339]
    DIRECTION INPUT ;
    USE SIGNAL ;
    PORT
      LAYER M4 ;
        RECT  0 37.968 0.192 37.992 ;
    END
  END i[339]
  PIN i[33]
    DIRECTION INPUT ;
    USE SIGNAL ;
    PORT
      LAYER M4 ;
        RECT  0 5.712 0.192 5.736 ;
    END
  END i[33]
  PIN i[340]
    DIRECTION INPUT ;
    USE SIGNAL ;
    PORT
      LAYER M4 ;
        RECT  0 38.064 0.192 38.088 ;
    END
  END i[340]
  PIN i[341]
    DIRECTION INPUT ;
    USE SIGNAL ;
    PORT
      LAYER M4 ;
        RECT  0 38.208 0.192 38.232 ;
    END
  END i[341]
  PIN i[342]
    DIRECTION INPUT ;
    USE SIGNAL ;
    PORT
      LAYER M4 ;
        RECT  0 38.304 0.192 38.328 ;
    END
  END i[342]
  PIN i[343]
    DIRECTION INPUT ;
    USE SIGNAL ;
    PORT
      LAYER M4 ;
        RECT  0 38.4 0.192 38.424 ;
    END
  END i[343]
  PIN i[344]
    DIRECTION INPUT ;
    USE SIGNAL ;
    PORT
      LAYER M4 ;
        RECT  0 38.496 0.192 38.52 ;
    END
  END i[344]
  PIN i[345]
    DIRECTION INPUT ;
    USE SIGNAL ;
    PORT
      LAYER M4 ;
        RECT  0 38.592 0.192 38.616 ;
    END
  END i[345]
  PIN i[346]
    DIRECTION INPUT ;
    USE SIGNAL ;
    PORT
      LAYER M4 ;
        RECT  0 38.736 0.192 38.76 ;
    END
  END i[346]
  PIN i[347]
    DIRECTION INPUT ;
    USE SIGNAL ;
    PORT
      LAYER M4 ;
        RECT  0 38.832 0.192 38.856 ;
    END
  END i[347]
  PIN i[348]
    DIRECTION INPUT ;
    USE SIGNAL ;
    PORT
      LAYER M4 ;
        RECT  0 38.928 0.192 38.952 ;
    END
  END i[348]
  PIN i[349]
    DIRECTION INPUT ;
    USE SIGNAL ;
    PORT
      LAYER M4 ;
        RECT  0 39.024 0.192 39.048 ;
    END
  END i[349]
  PIN i[34]
    DIRECTION INPUT ;
    USE SIGNAL ;
    PORT
      LAYER M4 ;
        RECT  0 5.808 0.192 5.832 ;
    END
  END i[34]
  PIN i[350]
    DIRECTION INPUT ;
    USE SIGNAL ;
    PORT
      LAYER M4 ;
        RECT  0 39.12 0.192 39.144 ;
    END
  END i[350]
  PIN i[351]
    DIRECTION INPUT ;
    USE SIGNAL ;
    PORT
      LAYER M4 ;
        RECT  0 39.264 0.192 39.288 ;
    END
  END i[351]
  PIN i[352]
    DIRECTION INPUT ;
    USE SIGNAL ;
    PORT
      LAYER M4 ;
        RECT  0 39.36 0.192 39.384 ;
    END
  END i[352]
  PIN i[353]
    DIRECTION INPUT ;
    USE SIGNAL ;
    PORT
      LAYER M4 ;
        RECT  0 39.456 0.192 39.48 ;
    END
  END i[353]
  PIN i[354]
    DIRECTION INPUT ;
    USE SIGNAL ;
    PORT
      LAYER M4 ;
        RECT  0 39.552 0.192 39.576 ;
    END
  END i[354]
  PIN i[355]
    DIRECTION INPUT ;
    USE SIGNAL ;
    PORT
      LAYER M4 ;
        RECT  0 39.648 0.192 39.672 ;
    END
  END i[355]
  PIN i[356]
    DIRECTION INPUT ;
    USE SIGNAL ;
    PORT
      LAYER M4 ;
        RECT  0 39.792 0.192 39.816 ;
    END
  END i[356]
  PIN i[357]
    DIRECTION INPUT ;
    USE SIGNAL ;
    PORT
      LAYER M4 ;
        RECT  0 39.888 0.192 39.912 ;
    END
  END i[357]
  PIN i[358]
    DIRECTION INPUT ;
    USE SIGNAL ;
    PORT
      LAYER M4 ;
        RECT  0 39.984 0.192 40.008 ;
    END
  END i[358]
  PIN i[359]
    DIRECTION INPUT ;
    USE SIGNAL ;
    PORT
      LAYER M4 ;
        RECT  0 40.08 0.192 40.104 ;
    END
  END i[359]
  PIN i[35]
    DIRECTION INPUT ;
    USE SIGNAL ;
    PORT
      LAYER M4 ;
        RECT  0 5.904 0.192 5.928 ;
    END
  END i[35]
  PIN i[360]
    DIRECTION INPUT ;
    USE SIGNAL ;
    PORT
      LAYER M4 ;
        RECT  0 40.176 0.192 40.2 ;
    END
  END i[360]
  PIN i[361]
    DIRECTION INPUT ;
    USE SIGNAL ;
    PORT
      LAYER M4 ;
        RECT  0 40.32 0.192 40.344 ;
    END
  END i[361]
  PIN i[362]
    DIRECTION INPUT ;
    USE SIGNAL ;
    PORT
      LAYER M4 ;
        RECT  0 40.416 0.192 40.44 ;
    END
  END i[362]
  PIN i[363]
    DIRECTION INPUT ;
    USE SIGNAL ;
    PORT
      LAYER M4 ;
        RECT  0 40.512 0.192 40.536 ;
    END
  END i[363]
  PIN i[364]
    DIRECTION INPUT ;
    USE SIGNAL ;
    PORT
      LAYER M4 ;
        RECT  0 40.608 0.192 40.632 ;
    END
  END i[364]
  PIN i[365]
    DIRECTION INPUT ;
    USE SIGNAL ;
    PORT
      LAYER M4 ;
        RECT  0 40.704 0.192 40.728 ;
    END
  END i[365]
  PIN i[366]
    DIRECTION INPUT ;
    USE SIGNAL ;
    PORT
      LAYER M4 ;
        RECT  0 40.848 0.192 40.872 ;
    END
  END i[366]
  PIN i[367]
    DIRECTION INPUT ;
    USE SIGNAL ;
    PORT
      LAYER M4 ;
        RECT  0 40.944 0.192 40.968 ;
    END
  END i[367]
  PIN i[368]
    DIRECTION INPUT ;
    USE SIGNAL ;
    PORT
      LAYER M4 ;
        RECT  0 41.04 0.192 41.064 ;
    END
  END i[368]
  PIN i[369]
    DIRECTION INPUT ;
    USE SIGNAL ;
    PORT
      LAYER M4 ;
        RECT  0 41.136 0.192 41.16 ;
    END
  END i[369]
  PIN i[36]
    DIRECTION INPUT ;
    USE SIGNAL ;
    PORT
      LAYER M4 ;
        RECT  0 6 0.192 6.024 ;
    END
  END i[36]
  PIN i[370]
    DIRECTION INPUT ;
    USE SIGNAL ;
    PORT
      LAYER M4 ;
        RECT  0 41.232 0.192 41.256 ;
    END
  END i[370]
  PIN i[371]
    DIRECTION INPUT ;
    USE SIGNAL ;
    PORT
      LAYER M4 ;
        RECT  0 41.376 0.192 41.4 ;
    END
  END i[371]
  PIN i[372]
    DIRECTION INPUT ;
    USE SIGNAL ;
    PORT
      LAYER M4 ;
        RECT  0 41.472 0.192 41.496 ;
    END
  END i[372]
  PIN i[373]
    DIRECTION INPUT ;
    USE SIGNAL ;
    PORT
      LAYER M4 ;
        RECT  0 41.568 0.192 41.592 ;
    END
  END i[373]
  PIN i[374]
    DIRECTION INPUT ;
    USE SIGNAL ;
    PORT
      LAYER M4 ;
        RECT  0 41.664 0.192 41.688 ;
    END
  END i[374]
  PIN i[375]
    DIRECTION INPUT ;
    USE SIGNAL ;
    PORT
      LAYER M4 ;
        RECT  0 41.76 0.192 41.784 ;
    END
  END i[375]
  PIN i[376]
    DIRECTION INPUT ;
    USE SIGNAL ;
    PORT
      LAYER M4 ;
        RECT  0 41.904 0.192 41.928 ;
    END
  END i[376]
  PIN i[377]
    DIRECTION INPUT ;
    USE SIGNAL ;
    PORT
      LAYER M4 ;
        RECT  0 42 0.192 42.024 ;
    END
  END i[377]
  PIN i[378]
    DIRECTION INPUT ;
    USE SIGNAL ;
    PORT
      LAYER M4 ;
        RECT  0 42.096 0.192 42.12 ;
    END
  END i[378]
  PIN i[379]
    DIRECTION INPUT ;
    USE SIGNAL ;
    PORT
      LAYER M4 ;
        RECT  0 42.192 0.192 42.216 ;
    END
  END i[379]
  PIN i[37]
    DIRECTION INPUT ;
    USE SIGNAL ;
    PORT
      LAYER M4 ;
        RECT  0 6.144 0.192 6.168 ;
    END
  END i[37]
  PIN i[380]
    DIRECTION INPUT ;
    USE SIGNAL ;
    PORT
      LAYER M4 ;
        RECT  0 42.288 0.192 42.312 ;
    END
  END i[380]
  PIN i[381]
    DIRECTION INPUT ;
    USE SIGNAL ;
    PORT
      LAYER M4 ;
        RECT  0 42.432 0.192 42.456 ;
    END
  END i[381]
  PIN i[382]
    DIRECTION INPUT ;
    USE SIGNAL ;
    PORT
      LAYER M4 ;
        RECT  0 42.528 0.192 42.552 ;
    END
  END i[382]
  PIN i[383]
    DIRECTION INPUT ;
    USE SIGNAL ;
    PORT
      LAYER M4 ;
        RECT  0 42.624 0.192 42.648 ;
    END
  END i[383]
  PIN i[384]
    DIRECTION INPUT ;
    USE SIGNAL ;
    PORT
      LAYER M4 ;
        RECT  0 42.72 0.192 42.744 ;
    END
  END i[384]
  PIN i[385]
    DIRECTION INPUT ;
    USE SIGNAL ;
    PORT
      LAYER M4 ;
        RECT  0 42.816 0.192 42.84 ;
    END
  END i[385]
  PIN i[386]
    DIRECTION INPUT ;
    USE SIGNAL ;
    PORT
      LAYER M4 ;
        RECT  0 42.912 0.192 42.936 ;
    END
  END i[386]
  PIN i[387]
    DIRECTION INPUT ;
    USE SIGNAL ;
    PORT
      LAYER M4 ;
        RECT  0 43.056 0.192 43.08 ;
    END
  END i[387]
  PIN i[388]
    DIRECTION INPUT ;
    USE SIGNAL ;
    PORT
      LAYER M4 ;
        RECT  0 43.152 0.192 43.176 ;
    END
  END i[388]
  PIN i[389]
    DIRECTION INPUT ;
    USE SIGNAL ;
    PORT
      LAYER M4 ;
        RECT  0 43.248 0.192 43.272 ;
    END
  END i[389]
  PIN i[38]
    DIRECTION INPUT ;
    USE SIGNAL ;
    PORT
      LAYER M4 ;
        RECT  0 6.24 0.192 6.264 ;
    END
  END i[38]
  PIN i[390]
    DIRECTION INPUT ;
    USE SIGNAL ;
    PORT
      LAYER M4 ;
        RECT  0 43.344 0.192 43.368 ;
    END
  END i[390]
  PIN i[391]
    DIRECTION INPUT ;
    USE SIGNAL ;
    PORT
      LAYER M4 ;
        RECT  0 43.44 0.192 43.464 ;
    END
  END i[391]
  PIN i[392]
    DIRECTION INPUT ;
    USE SIGNAL ;
    PORT
      LAYER M4 ;
        RECT  0 43.584 0.192 43.608 ;
    END
  END i[392]
  PIN i[393]
    DIRECTION INPUT ;
    USE SIGNAL ;
    PORT
      LAYER M4 ;
        RECT  0 43.68 0.192 43.704 ;
    END
  END i[393]
  PIN i[394]
    DIRECTION INPUT ;
    USE SIGNAL ;
    PORT
      LAYER M4 ;
        RECT  0 43.776 0.192 43.8 ;
    END
  END i[394]
  PIN i[395]
    DIRECTION INPUT ;
    USE SIGNAL ;
    PORT
      LAYER M4 ;
        RECT  0 43.872 0.192 43.896 ;
    END
  END i[395]
  PIN i[396]
    DIRECTION INPUT ;
    USE SIGNAL ;
    PORT
      LAYER M4 ;
        RECT  0 43.968 0.192 43.992 ;
    END
  END i[396]
  PIN i[397]
    DIRECTION INPUT ;
    USE SIGNAL ;
    PORT
      LAYER M4 ;
        RECT  0 44.112 0.192 44.136 ;
    END
  END i[397]
  PIN i[398]
    DIRECTION INPUT ;
    USE SIGNAL ;
    PORT
      LAYER M4 ;
        RECT  0 44.208 0.192 44.232 ;
    END
  END i[398]
  PIN i[399]
    DIRECTION INPUT ;
    USE SIGNAL ;
    PORT
      LAYER M4 ;
        RECT  0 44.304 0.192 44.328 ;
    END
  END i[399]
  PIN i[39]
    DIRECTION INPUT ;
    USE SIGNAL ;
    PORT
      LAYER M4 ;
        RECT  0 6.336 0.192 6.36 ;
    END
  END i[39]
  PIN i[3]
    DIRECTION INPUT ;
    USE SIGNAL ;
    PORT
      LAYER M4 ;
        RECT  0 2.544 0.192 2.568 ;
    END
  END i[3]
  PIN i[400]
    DIRECTION INPUT ;
    USE SIGNAL ;
    PORT
      LAYER M4 ;
        RECT  0 44.4 0.192 44.424 ;
    END
  END i[400]
  PIN i[401]
    DIRECTION INPUT ;
    USE SIGNAL ;
    PORT
      LAYER M4 ;
        RECT  0 44.496 0.192 44.52 ;
    END
  END i[401]
  PIN i[402]
    DIRECTION INPUT ;
    USE SIGNAL ;
    PORT
      LAYER M4 ;
        RECT  0 44.64 0.192 44.664 ;
    END
  END i[402]
  PIN i[403]
    DIRECTION INPUT ;
    USE SIGNAL ;
    PORT
      LAYER M4 ;
        RECT  0 44.736 0.192 44.76 ;
    END
  END i[403]
  PIN i[404]
    DIRECTION INPUT ;
    USE SIGNAL ;
    PORT
      LAYER M4 ;
        RECT  0 44.832 0.192 44.856 ;
    END
  END i[404]
  PIN i[405]
    DIRECTION INPUT ;
    USE SIGNAL ;
    PORT
      LAYER M4 ;
        RECT  0 44.928 0.192 44.952 ;
    END
  END i[405]
  PIN i[406]
    DIRECTION INPUT ;
    USE SIGNAL ;
    PORT
      LAYER M4 ;
        RECT  0 45.024 0.192 45.048 ;
    END
  END i[406]
  PIN i[407]
    DIRECTION INPUT ;
    USE SIGNAL ;
    PORT
      LAYER M4 ;
        RECT  0 45.168 0.192 45.192 ;
    END
  END i[407]
  PIN i[408]
    DIRECTION INPUT ;
    USE SIGNAL ;
    PORT
      LAYER M4 ;
        RECT  0 45.264 0.192 45.288 ;
    END
  END i[408]
  PIN i[409]
    DIRECTION INPUT ;
    USE SIGNAL ;
    PORT
      LAYER M4 ;
        RECT  0 45.36 0.192 45.384 ;
    END
  END i[409]
  PIN i[40]
    DIRECTION INPUT ;
    USE SIGNAL ;
    PORT
      LAYER M4 ;
        RECT  0 6.432 0.192 6.456 ;
    END
  END i[40]
  PIN i[410]
    DIRECTION INPUT ;
    USE SIGNAL ;
    PORT
      LAYER M4 ;
        RECT  0 45.456 0.192 45.48 ;
    END
  END i[410]
  PIN i[411]
    DIRECTION INPUT ;
    USE SIGNAL ;
    PORT
      LAYER M4 ;
        RECT  0 45.552 0.192 45.576 ;
    END
  END i[411]
  PIN i[412]
    DIRECTION INPUT ;
    USE SIGNAL ;
    PORT
      LAYER M4 ;
        RECT  0 45.696 0.192 45.72 ;
    END
  END i[412]
  PIN i[413]
    DIRECTION INPUT ;
    USE SIGNAL ;
    PORT
      LAYER M4 ;
        RECT  0 45.792 0.192 45.816 ;
    END
  END i[413]
  PIN i[414]
    DIRECTION INPUT ;
    USE SIGNAL ;
    PORT
      LAYER M4 ;
        RECT  0 45.888 0.192 45.912 ;
    END
  END i[414]
  PIN i[415]
    DIRECTION INPUT ;
    USE SIGNAL ;
    PORT
      LAYER M4 ;
        RECT  0 45.984 0.192 46.008 ;
    END
  END i[415]
  PIN i[416]
    DIRECTION INPUT ;
    USE SIGNAL ;
    PORT
      LAYER M4 ;
        RECT  0 46.08 0.192 46.104 ;
    END
  END i[416]
  PIN i[417]
    DIRECTION INPUT ;
    USE SIGNAL ;
    PORT
      LAYER M4 ;
        RECT  0 46.224 0.192 46.248 ;
    END
  END i[417]
  PIN i[418]
    DIRECTION INPUT ;
    USE SIGNAL ;
    PORT
      LAYER M4 ;
        RECT  0 46.32 0.192 46.344 ;
    END
  END i[418]
  PIN i[419]
    DIRECTION INPUT ;
    USE SIGNAL ;
    PORT
      LAYER M4 ;
        RECT  0 46.416 0.192 46.44 ;
    END
  END i[419]
  PIN i[41]
    DIRECTION INPUT ;
    USE SIGNAL ;
    PORT
      LAYER M4 ;
        RECT  0 6.528 0.192 6.552 ;
    END
  END i[41]
  PIN i[420]
    DIRECTION INPUT ;
    USE SIGNAL ;
    PORT
      LAYER M4 ;
        RECT  0 46.512 0.192 46.536 ;
    END
  END i[420]
  PIN i[421]
    DIRECTION INPUT ;
    USE SIGNAL ;
    PORT
      LAYER M4 ;
        RECT  0 46.608 0.192 46.632 ;
    END
  END i[421]
  PIN i[422]
    DIRECTION INPUT ;
    USE SIGNAL ;
    PORT
      LAYER M4 ;
        RECT  0 46.752 0.192 46.776 ;
    END
  END i[422]
  PIN i[423]
    DIRECTION INPUT ;
    USE SIGNAL ;
    PORT
      LAYER M4 ;
        RECT  0 46.848 0.192 46.872 ;
    END
  END i[423]
  PIN i[424]
    DIRECTION INPUT ;
    USE SIGNAL ;
    PORT
      LAYER M4 ;
        RECT  0 46.944 0.192 46.968 ;
    END
  END i[424]
  PIN i[425]
    DIRECTION INPUT ;
    USE SIGNAL ;
    PORT
      LAYER M4 ;
        RECT  0 47.04 0.192 47.064 ;
    END
  END i[425]
  PIN i[426]
    DIRECTION INPUT ;
    USE SIGNAL ;
    PORT
      LAYER M4 ;
        RECT  0 47.136 0.192 47.16 ;
    END
  END i[426]
  PIN i[427]
    DIRECTION INPUT ;
    USE SIGNAL ;
    PORT
      LAYER M4 ;
        RECT  0 47.28 0.192 47.304 ;
    END
  END i[427]
  PIN i[428]
    DIRECTION INPUT ;
    USE SIGNAL ;
    PORT
      LAYER M4 ;
        RECT  0 47.376 0.192 47.4 ;
    END
  END i[428]
  PIN i[429]
    DIRECTION INPUT ;
    USE SIGNAL ;
    PORT
      LAYER M4 ;
        RECT  0 47.472 0.192 47.496 ;
    END
  END i[429]
  PIN i[42]
    DIRECTION INPUT ;
    USE SIGNAL ;
    PORT
      LAYER M4 ;
        RECT  0 6.672 0.192 6.696 ;
    END
  END i[42]
  PIN i[430]
    DIRECTION INPUT ;
    USE SIGNAL ;
    PORT
      LAYER M4 ;
        RECT  0 47.568 0.192 47.592 ;
    END
  END i[430]
  PIN i[431]
    DIRECTION INPUT ;
    USE SIGNAL ;
    PORT
      LAYER M4 ;
        RECT  0 47.664 0.192 47.688 ;
    END
  END i[431]
  PIN i[432]
    DIRECTION INPUT ;
    USE SIGNAL ;
    PORT
      LAYER M4 ;
        RECT  0 47.808 0.192 47.832 ;
    END
  END i[432]
  PIN i[433]
    DIRECTION INPUT ;
    USE SIGNAL ;
    PORT
      LAYER M4 ;
        RECT  0 47.904 0.192 47.928 ;
    END
  END i[433]
  PIN i[434]
    DIRECTION INPUT ;
    USE SIGNAL ;
    PORT
      LAYER M4 ;
        RECT  0 48 0.192 48.024 ;
    END
  END i[434]
  PIN i[435]
    DIRECTION INPUT ;
    USE SIGNAL ;
    PORT
      LAYER M4 ;
        RECT  0 48.096 0.192 48.12 ;
    END
  END i[435]
  PIN i[436]
    DIRECTION INPUT ;
    USE SIGNAL ;
    PORT
      LAYER M4 ;
        RECT  0 48.192 0.192 48.216 ;
    END
  END i[436]
  PIN i[437]
    DIRECTION INPUT ;
    USE SIGNAL ;
    PORT
      LAYER M4 ;
        RECT  0 48.336 0.192 48.36 ;
    END
  END i[437]
  PIN i[438]
    DIRECTION INPUT ;
    USE SIGNAL ;
    PORT
      LAYER M4 ;
        RECT  0 48.432 0.192 48.456 ;
    END
  END i[438]
  PIN i[439]
    DIRECTION INPUT ;
    USE SIGNAL ;
    PORT
      LAYER M4 ;
        RECT  0 48.528 0.192 48.552 ;
    END
  END i[439]
  PIN i[43]
    DIRECTION INPUT ;
    USE SIGNAL ;
    PORT
      LAYER M4 ;
        RECT  0 6.768 0.192 6.792 ;
    END
  END i[43]
  PIN i[440]
    DIRECTION INPUT ;
    USE SIGNAL ;
    PORT
      LAYER M4 ;
        RECT  0 48.624 0.192 48.648 ;
    END
  END i[440]
  PIN i[441]
    DIRECTION INPUT ;
    USE SIGNAL ;
    PORT
      LAYER M4 ;
        RECT  0 48.72 0.192 48.744 ;
    END
  END i[441]
  PIN i[442]
    DIRECTION INPUT ;
    USE SIGNAL ;
    PORT
      LAYER M4 ;
        RECT  0 48.864 0.192 48.888 ;
    END
  END i[442]
  PIN i[443]
    DIRECTION INPUT ;
    USE SIGNAL ;
    PORT
      LAYER M4 ;
        RECT  0 48.96 0.192 48.984 ;
    END
  END i[443]
  PIN i[444]
    DIRECTION INPUT ;
    USE SIGNAL ;
    PORT
      LAYER M4 ;
        RECT  0 49.056 0.192 49.08 ;
    END
  END i[444]
  PIN i[445]
    DIRECTION INPUT ;
    USE SIGNAL ;
    PORT
      LAYER M4 ;
        RECT  0 49.152 0.192 49.176 ;
    END
  END i[445]
  PIN i[446]
    DIRECTION INPUT ;
    USE SIGNAL ;
    PORT
      LAYER M4 ;
        RECT  0 49.248 0.192 49.272 ;
    END
  END i[446]
  PIN i[447]
    DIRECTION INPUT ;
    USE SIGNAL ;
    PORT
      LAYER M4 ;
        RECT  0 49.392 0.192 49.416 ;
    END
  END i[447]
  PIN i[448]
    DIRECTION INPUT ;
    USE SIGNAL ;
    PORT
      LAYER M4 ;
        RECT  0 49.488 0.192 49.512 ;
    END
  END i[448]
  PIN i[449]
    DIRECTION INPUT ;
    USE SIGNAL ;
    PORT
      LAYER M4 ;
        RECT  0 49.584 0.192 49.608 ;
    END
  END i[449]
  PIN i[44]
    DIRECTION INPUT ;
    USE SIGNAL ;
    PORT
      LAYER M4 ;
        RECT  0 6.864 0.192 6.888 ;
    END
  END i[44]
  PIN i[450]
    DIRECTION INPUT ;
    USE SIGNAL ;
    PORT
      LAYER M4 ;
        RECT  0 49.68 0.192 49.704 ;
    END
  END i[450]
  PIN i[451]
    DIRECTION INPUT ;
    USE SIGNAL ;
    PORT
      LAYER M4 ;
        RECT  0 49.776 0.192 49.8 ;
    END
  END i[451]
  PIN i[452]
    DIRECTION INPUT ;
    USE SIGNAL ;
    PORT
      LAYER M4 ;
        RECT  0 49.92 0.192 49.944 ;
    END
  END i[452]
  PIN i[453]
    DIRECTION INPUT ;
    USE SIGNAL ;
    PORT
      LAYER M4 ;
        RECT  0 50.016 0.192 50.04 ;
    END
  END i[453]
  PIN i[454]
    DIRECTION INPUT ;
    USE SIGNAL ;
    PORT
      LAYER M4 ;
        RECT  0 50.112 0.192 50.136 ;
    END
  END i[454]
  PIN i[455]
    DIRECTION INPUT ;
    USE SIGNAL ;
    PORT
      LAYER M4 ;
        RECT  0 50.208 0.192 50.232 ;
    END
  END i[455]
  PIN i[456]
    DIRECTION INPUT ;
    USE SIGNAL ;
    PORT
      LAYER M4 ;
        RECT  0 50.304 0.192 50.328 ;
    END
  END i[456]
  PIN i[457]
    DIRECTION INPUT ;
    USE SIGNAL ;
    PORT
      LAYER M4 ;
        RECT  0 50.4 0.192 50.424 ;
    END
  END i[457]
  PIN i[458]
    DIRECTION INPUT ;
    USE SIGNAL ;
    PORT
      LAYER M4 ;
        RECT  0 50.544 0.192 50.568 ;
    END
  END i[458]
  PIN i[459]
    DIRECTION INPUT ;
    USE SIGNAL ;
    PORT
      LAYER M4 ;
        RECT  0 50.64 0.192 50.664 ;
    END
  END i[459]
  PIN i[45]
    DIRECTION INPUT ;
    USE SIGNAL ;
    PORT
      LAYER M4 ;
        RECT  0 6.96 0.192 6.984 ;
    END
  END i[45]
  PIN i[460]
    DIRECTION INPUT ;
    USE SIGNAL ;
    PORT
      LAYER M4 ;
        RECT  0 50.736 0.192 50.76 ;
    END
  END i[460]
  PIN i[461]
    DIRECTION INPUT ;
    USE SIGNAL ;
    PORT
      LAYER M4 ;
        RECT  0 50.832 0.192 50.856 ;
    END
  END i[461]
  PIN i[462]
    DIRECTION INPUT ;
    USE SIGNAL ;
    PORT
      LAYER M4 ;
        RECT  0 50.928 0.192 50.952 ;
    END
  END i[462]
  PIN i[463]
    DIRECTION INPUT ;
    USE SIGNAL ;
    PORT
      LAYER M4 ;
        RECT  0 51.072 0.192 51.096 ;
    END
  END i[463]
  PIN i[464]
    DIRECTION INPUT ;
    USE SIGNAL ;
    PORT
      LAYER M4 ;
        RECT  0 51.168 0.192 51.192 ;
    END
  END i[464]
  PIN i[465]
    DIRECTION INPUT ;
    USE SIGNAL ;
    PORT
      LAYER M4 ;
        RECT  0 51.264 0.192 51.288 ;
    END
  END i[465]
  PIN i[466]
    DIRECTION INPUT ;
    USE SIGNAL ;
    PORT
      LAYER M4 ;
        RECT  0 51.36 0.192 51.384 ;
    END
  END i[466]
  PIN i[467]
    DIRECTION INPUT ;
    USE SIGNAL ;
    PORT
      LAYER M4 ;
        RECT  0 51.456 0.192 51.48 ;
    END
  END i[467]
  PIN i[468]
    DIRECTION INPUT ;
    USE SIGNAL ;
    PORT
      LAYER M4 ;
        RECT  0 51.6 0.192 51.624 ;
    END
  END i[468]
  PIN i[469]
    DIRECTION INPUT ;
    USE SIGNAL ;
    PORT
      LAYER M4 ;
        RECT  0 51.696 0.192 51.72 ;
    END
  END i[469]
  PIN i[46]
    DIRECTION INPUT ;
    USE SIGNAL ;
    PORT
      LAYER M4 ;
        RECT  0 7.056 0.192 7.08 ;
    END
  END i[46]
  PIN i[470]
    DIRECTION INPUT ;
    USE SIGNAL ;
    PORT
      LAYER M4 ;
        RECT  0 51.792 0.192 51.816 ;
    END
  END i[470]
  PIN i[471]
    DIRECTION INPUT ;
    USE SIGNAL ;
    PORT
      LAYER M4 ;
        RECT  0 51.888 0.192 51.912 ;
    END
  END i[471]
  PIN i[472]
    DIRECTION INPUT ;
    USE SIGNAL ;
    PORT
      LAYER M4 ;
        RECT  0 51.984 0.192 52.008 ;
    END
  END i[472]
  PIN i[473]
    DIRECTION INPUT ;
    USE SIGNAL ;
    PORT
      LAYER M4 ;
        RECT  0 52.128 0.192 52.152 ;
    END
  END i[473]
  PIN i[474]
    DIRECTION INPUT ;
    USE SIGNAL ;
    PORT
      LAYER M4 ;
        RECT  0 52.224 0.192 52.248 ;
    END
  END i[474]
  PIN i[475]
    DIRECTION INPUT ;
    USE SIGNAL ;
    PORT
      LAYER M4 ;
        RECT  0 52.32 0.192 52.344 ;
    END
  END i[475]
  PIN i[476]
    DIRECTION INPUT ;
    USE SIGNAL ;
    PORT
      LAYER M4 ;
        RECT  0 52.416 0.192 52.44 ;
    END
  END i[476]
  PIN i[477]
    DIRECTION INPUT ;
    USE SIGNAL ;
    PORT
      LAYER M4 ;
        RECT  0 52.512 0.192 52.536 ;
    END
  END i[477]
  PIN i[478]
    DIRECTION INPUT ;
    USE SIGNAL ;
    PORT
      LAYER M4 ;
        RECT  0 52.656 0.192 52.68 ;
    END
  END i[478]
  PIN i[479]
    DIRECTION INPUT ;
    USE SIGNAL ;
    PORT
      LAYER M4 ;
        RECT  0 52.752 0.192 52.776 ;
    END
  END i[479]
  PIN i[47]
    DIRECTION INPUT ;
    USE SIGNAL ;
    PORT
      LAYER M4 ;
        RECT  0 7.2 0.192 7.224 ;
    END
  END i[47]
  PIN i[480]
    DIRECTION INPUT ;
    USE SIGNAL ;
    PORT
      LAYER M4 ;
        RECT  0 52.848 0.192 52.872 ;
    END
  END i[480]
  PIN i[481]
    DIRECTION INPUT ;
    USE SIGNAL ;
    PORT
      LAYER M4 ;
        RECT  0 52.944 0.192 52.968 ;
    END
  END i[481]
  PIN i[482]
    DIRECTION INPUT ;
    USE SIGNAL ;
    PORT
      LAYER M4 ;
        RECT  0 53.04 0.192 53.064 ;
    END
  END i[482]
  PIN i[483]
    DIRECTION INPUT ;
    USE SIGNAL ;
    PORT
      LAYER M4 ;
        RECT  0 53.184 0.192 53.208 ;
    END
  END i[483]
  PIN i[484]
    DIRECTION INPUT ;
    USE SIGNAL ;
    PORT
      LAYER M4 ;
        RECT  0 53.28 0.192 53.304 ;
    END
  END i[484]
  PIN i[485]
    DIRECTION INPUT ;
    USE SIGNAL ;
    PORT
      LAYER M4 ;
        RECT  0 53.376 0.192 53.4 ;
    END
  END i[485]
  PIN i[486]
    DIRECTION INPUT ;
    USE SIGNAL ;
    PORT
      LAYER M4 ;
        RECT  0 53.472 0.192 53.496 ;
    END
  END i[486]
  PIN i[487]
    DIRECTION INPUT ;
    USE SIGNAL ;
    PORT
      LAYER M4 ;
        RECT  0 53.568 0.192 53.592 ;
    END
  END i[487]
  PIN i[488]
    DIRECTION INPUT ;
    USE SIGNAL ;
    PORT
      LAYER M4 ;
        RECT  0 53.712 0.192 53.736 ;
    END
  END i[488]
  PIN i[489]
    DIRECTION INPUT ;
    USE SIGNAL ;
    PORT
      LAYER M4 ;
        RECT  0 53.808 0.192 53.832 ;
    END
  END i[489]
  PIN i[48]
    DIRECTION INPUT ;
    USE SIGNAL ;
    PORT
      LAYER M4 ;
        RECT  0 7.296 0.192 7.32 ;
    END
  END i[48]
  PIN i[490]
    DIRECTION INPUT ;
    USE SIGNAL ;
    PORT
      LAYER M4 ;
        RECT  0 53.904 0.192 53.928 ;
    END
  END i[490]
  PIN i[491]
    DIRECTION INPUT ;
    USE SIGNAL ;
    PORT
      LAYER M4 ;
        RECT  0 54 0.192 54.024 ;
    END
  END i[491]
  PIN i[492]
    DIRECTION INPUT ;
    USE SIGNAL ;
    PORT
      LAYER M4 ;
        RECT  0 54.096 0.192 54.12 ;
    END
  END i[492]
  PIN i[493]
    DIRECTION INPUT ;
    USE SIGNAL ;
    PORT
      LAYER M4 ;
        RECT  0 54.24 0.192 54.264 ;
    END
  END i[493]
  PIN i[494]
    DIRECTION INPUT ;
    USE SIGNAL ;
    PORT
      LAYER M4 ;
        RECT  0 54.336 0.192 54.36 ;
    END
  END i[494]
  PIN i[495]
    DIRECTION INPUT ;
    USE SIGNAL ;
    PORT
      LAYER M4 ;
        RECT  0 54.432 0.192 54.456 ;
    END
  END i[495]
  PIN i[496]
    DIRECTION INPUT ;
    USE SIGNAL ;
    PORT
      LAYER M4 ;
        RECT  0 54.528 0.192 54.552 ;
    END
  END i[496]
  PIN i[497]
    DIRECTION INPUT ;
    USE SIGNAL ;
    PORT
      LAYER M4 ;
        RECT  0 54.624 0.192 54.648 ;
    END
  END i[497]
  PIN i[498]
    DIRECTION INPUT ;
    USE SIGNAL ;
    PORT
      LAYER M4 ;
        RECT  0 54.768 0.192 54.792 ;
    END
  END i[498]
  PIN i[499]
    DIRECTION INPUT ;
    USE SIGNAL ;
    PORT
      LAYER M4 ;
        RECT  0 54.864 0.192 54.888 ;
    END
  END i[499]
  PIN i[49]
    DIRECTION INPUT ;
    USE SIGNAL ;
    PORT
      LAYER M4 ;
        RECT  0 7.392 0.192 7.416 ;
    END
  END i[49]
  PIN i[4]
    DIRECTION INPUT ;
    USE SIGNAL ;
    PORT
      LAYER M4 ;
        RECT  0 2.64 0.192 2.664 ;
    END
  END i[4]
  PIN i[500]
    DIRECTION INPUT ;
    USE SIGNAL ;
    PORT
      LAYER M4 ;
        RECT  0 54.96 0.192 54.984 ;
    END
  END i[500]
  PIN i[501]
    DIRECTION INPUT ;
    USE SIGNAL ;
    PORT
      LAYER M4 ;
        RECT  0 55.056 0.192 55.08 ;
    END
  END i[501]
  PIN i[502]
    DIRECTION INPUT ;
    USE SIGNAL ;
    PORT
      LAYER M4 ;
        RECT  0 55.152 0.192 55.176 ;
    END
  END i[502]
  PIN i[503]
    DIRECTION INPUT ;
    USE SIGNAL ;
    PORT
      LAYER M4 ;
        RECT  0 55.296 0.192 55.32 ;
    END
  END i[503]
  PIN i[504]
    DIRECTION INPUT ;
    USE SIGNAL ;
    PORT
      LAYER M4 ;
        RECT  0 55.392 0.192 55.416 ;
    END
  END i[504]
  PIN i[505]
    DIRECTION INPUT ;
    USE SIGNAL ;
    PORT
      LAYER M4 ;
        RECT  0 55.488 0.192 55.512 ;
    END
  END i[505]
  PIN i[506]
    DIRECTION INPUT ;
    USE SIGNAL ;
    PORT
      LAYER M4 ;
        RECT  0 55.584 0.192 55.608 ;
    END
  END i[506]
  PIN i[507]
    DIRECTION INPUT ;
    USE SIGNAL ;
    PORT
      LAYER M4 ;
        RECT  0 55.68 0.192 55.704 ;
    END
  END i[507]
  PIN i[508]
    DIRECTION INPUT ;
    USE SIGNAL ;
    PORT
      LAYER M4 ;
        RECT  0 55.824 0.192 55.848 ;
    END
  END i[508]
  PIN i[509]
    DIRECTION INPUT ;
    USE SIGNAL ;
    PORT
      LAYER M4 ;
        RECT  0 55.92 0.192 55.944 ;
    END
  END i[509]
  PIN i[50]
    DIRECTION INPUT ;
    USE SIGNAL ;
    PORT
      LAYER M4 ;
        RECT  0 7.488 0.192 7.512 ;
    END
  END i[50]
  PIN i[510]
    DIRECTION INPUT ;
    USE SIGNAL ;
    PORT
      LAYER M4 ;
        RECT  0 56.016 0.192 56.04 ;
    END
  END i[510]
  PIN i[511]
    DIRECTION INPUT ;
    USE SIGNAL ;
    PORT
      LAYER M4 ;
        RECT  0 56.112 0.192 56.136 ;
    END
  END i[511]
  PIN i[51]
    DIRECTION INPUT ;
    USE SIGNAL ;
    PORT
      LAYER M4 ;
        RECT  0 7.584 0.192 7.608 ;
    END
  END i[51]
  PIN i[52]
    DIRECTION INPUT ;
    USE SIGNAL ;
    PORT
      LAYER M4 ;
        RECT  0 7.728 0.192 7.752 ;
    END
  END i[52]
  PIN i[53]
    DIRECTION INPUT ;
    USE SIGNAL ;
    PORT
      LAYER M4 ;
        RECT  0 7.824 0.192 7.848 ;
    END
  END i[53]
  PIN i[54]
    DIRECTION INPUT ;
    USE SIGNAL ;
    PORT
      LAYER M4 ;
        RECT  0 7.92 0.192 7.944 ;
    END
  END i[54]
  PIN i[55]
    DIRECTION INPUT ;
    USE SIGNAL ;
    PORT
      LAYER M4 ;
        RECT  0 8.016 0.192 8.04 ;
    END
  END i[55]
  PIN i[56]
    DIRECTION INPUT ;
    USE SIGNAL ;
    PORT
      LAYER M4 ;
        RECT  0 8.112 0.192 8.136 ;
    END
  END i[56]
  PIN i[57]
    DIRECTION INPUT ;
    USE SIGNAL ;
    PORT
      LAYER M4 ;
        RECT  0 8.256 0.192 8.28 ;
    END
  END i[57]
  PIN i[58]
    DIRECTION INPUT ;
    USE SIGNAL ;
    PORT
      LAYER M4 ;
        RECT  0 8.352 0.192 8.376 ;
    END
  END i[58]
  PIN i[59]
    DIRECTION INPUT ;
    USE SIGNAL ;
    PORT
      LAYER M4 ;
        RECT  0 8.448 0.192 8.472 ;
    END
  END i[59]
  PIN i[5]
    DIRECTION INPUT ;
    USE SIGNAL ;
    PORT
      LAYER M4 ;
        RECT  0 2.736 0.192 2.76 ;
    END
  END i[5]
  PIN i[60]
    DIRECTION INPUT ;
    USE SIGNAL ;
    PORT
      LAYER M4 ;
        RECT  0 8.544 0.192 8.568 ;
    END
  END i[60]
  PIN i[61]
    DIRECTION INPUT ;
    USE SIGNAL ;
    PORT
      LAYER M4 ;
        RECT  0 8.64 0.192 8.664 ;
    END
  END i[61]
  PIN i[62]
    DIRECTION INPUT ;
    USE SIGNAL ;
    PORT
      LAYER M4 ;
        RECT  0 8.784 0.192 8.808 ;
    END
  END i[62]
  PIN i[63]
    DIRECTION INPUT ;
    USE SIGNAL ;
    PORT
      LAYER M4 ;
        RECT  0 8.88 0.192 8.904 ;
    END
  END i[63]
  PIN i[64]
    DIRECTION INPUT ;
    USE SIGNAL ;
    PORT
      LAYER M4 ;
        RECT  0 8.976 0.192 9 ;
    END
  END i[64]
  PIN i[65]
    DIRECTION INPUT ;
    USE SIGNAL ;
    PORT
      LAYER M4 ;
        RECT  0 9.072 0.192 9.096 ;
    END
  END i[65]
  PIN i[66]
    DIRECTION INPUT ;
    USE SIGNAL ;
    PORT
      LAYER M4 ;
        RECT  0 9.168 0.192 9.192 ;
    END
  END i[66]
  PIN i[67]
    DIRECTION INPUT ;
    USE SIGNAL ;
    PORT
      LAYER M4 ;
        RECT  0 9.312 0.192 9.336 ;
    END
  END i[67]
  PIN i[68]
    DIRECTION INPUT ;
    USE SIGNAL ;
    PORT
      LAYER M4 ;
        RECT  0 9.408 0.192 9.432 ;
    END
  END i[68]
  PIN i[69]
    DIRECTION INPUT ;
    USE SIGNAL ;
    PORT
      LAYER M4 ;
        RECT  0 9.504 0.192 9.528 ;
    END
  END i[69]
  PIN i[6]
    DIRECTION INPUT ;
    USE SIGNAL ;
    PORT
      LAYER M4 ;
        RECT  0 2.88 0.192 2.904 ;
    END
  END i[6]
  PIN i[70]
    DIRECTION INPUT ;
    USE SIGNAL ;
    PORT
      LAYER M4 ;
        RECT  0 9.6 0.192 9.624 ;
    END
  END i[70]
  PIN i[71]
    DIRECTION INPUT ;
    USE SIGNAL ;
    PORT
      LAYER M4 ;
        RECT  0 9.696 0.192 9.72 ;
    END
  END i[71]
  PIN i[72]
    DIRECTION INPUT ;
    USE SIGNAL ;
    PORT
      LAYER M4 ;
        RECT  0 9.84 0.192 9.864 ;
    END
  END i[72]
  PIN i[73]
    DIRECTION INPUT ;
    USE SIGNAL ;
    PORT
      LAYER M4 ;
        RECT  0 9.936 0.192 9.96 ;
    END
  END i[73]
  PIN i[74]
    DIRECTION INPUT ;
    USE SIGNAL ;
    PORT
      LAYER M4 ;
        RECT  0 10.032 0.192 10.056 ;
    END
  END i[74]
  PIN i[75]
    DIRECTION INPUT ;
    USE SIGNAL ;
    PORT
      LAYER M4 ;
        RECT  0 10.128 0.192 10.152 ;
    END
  END i[75]
  PIN i[76]
    DIRECTION INPUT ;
    USE SIGNAL ;
    PORT
      LAYER M4 ;
        RECT  0 10.224 0.192 10.248 ;
    END
  END i[76]
  PIN i[77]
    DIRECTION INPUT ;
    USE SIGNAL ;
    PORT
      LAYER M4 ;
        RECT  0 10.368 0.192 10.392 ;
    END
  END i[77]
  PIN i[78]
    DIRECTION INPUT ;
    USE SIGNAL ;
    PORT
      LAYER M4 ;
        RECT  0 10.464 0.192 10.488 ;
    END
  END i[78]
  PIN i[79]
    DIRECTION INPUT ;
    USE SIGNAL ;
    PORT
      LAYER M4 ;
        RECT  0 10.56 0.192 10.584 ;
    END
  END i[79]
  PIN i[7]
    DIRECTION INPUT ;
    USE SIGNAL ;
    PORT
      LAYER M4 ;
        RECT  0 2.976 0.192 3 ;
    END
  END i[7]
  PIN i[80]
    DIRECTION INPUT ;
    USE SIGNAL ;
    PORT
      LAYER M4 ;
        RECT  0 10.656 0.192 10.68 ;
    END
  END i[80]
  PIN i[81]
    DIRECTION INPUT ;
    USE SIGNAL ;
    PORT
      LAYER M4 ;
        RECT  0 10.752 0.192 10.776 ;
    END
  END i[81]
  PIN i[82]
    DIRECTION INPUT ;
    USE SIGNAL ;
    PORT
      LAYER M4 ;
        RECT  0 10.896 0.192 10.92 ;
    END
  END i[82]
  PIN i[83]
    DIRECTION INPUT ;
    USE SIGNAL ;
    PORT
      LAYER M4 ;
        RECT  0 10.992 0.192 11.016 ;
    END
  END i[83]
  PIN i[84]
    DIRECTION INPUT ;
    USE SIGNAL ;
    PORT
      LAYER M4 ;
        RECT  0 11.088 0.192 11.112 ;
    END
  END i[84]
  PIN i[85]
    DIRECTION INPUT ;
    USE SIGNAL ;
    PORT
      LAYER M4 ;
        RECT  0 11.184 0.192 11.208 ;
    END
  END i[85]
  PIN i[86]
    DIRECTION INPUT ;
    USE SIGNAL ;
    PORT
      LAYER M4 ;
        RECT  0 11.28 0.192 11.304 ;
    END
  END i[86]
  PIN i[87]
    DIRECTION INPUT ;
    USE SIGNAL ;
    PORT
      LAYER M4 ;
        RECT  0 11.424 0.192 11.448 ;
    END
  END i[87]
  PIN i[88]
    DIRECTION INPUT ;
    USE SIGNAL ;
    PORT
      LAYER M4 ;
        RECT  0 11.52 0.192 11.544 ;
    END
  END i[88]
  PIN i[89]
    DIRECTION INPUT ;
    USE SIGNAL ;
    PORT
      LAYER M4 ;
        RECT  0 11.616 0.192 11.64 ;
    END
  END i[89]
  PIN i[8]
    DIRECTION INPUT ;
    USE SIGNAL ;
    PORT
      LAYER M4 ;
        RECT  0 3.072 0.192 3.096 ;
    END
  END i[8]
  PIN i[90]
    DIRECTION INPUT ;
    USE SIGNAL ;
    PORT
      LAYER M4 ;
        RECT  0 11.712 0.192 11.736 ;
    END
  END i[90]
  PIN i[91]
    DIRECTION INPUT ;
    USE SIGNAL ;
    PORT
      LAYER M4 ;
        RECT  0 11.808 0.192 11.832 ;
    END
  END i[91]
  PIN i[92]
    DIRECTION INPUT ;
    USE SIGNAL ;
    PORT
      LAYER M4 ;
        RECT  0 11.904 0.192 11.928 ;
    END
  END i[92]
  PIN i[93]
    DIRECTION INPUT ;
    USE SIGNAL ;
    PORT
      LAYER M4 ;
        RECT  0 12.048 0.192 12.072 ;
    END
  END i[93]
  PIN i[94]
    DIRECTION INPUT ;
    USE SIGNAL ;
    PORT
      LAYER M4 ;
        RECT  0 12.144 0.192 12.168 ;
    END
  END i[94]
  PIN i[95]
    DIRECTION INPUT ;
    USE SIGNAL ;
    PORT
      LAYER M4 ;
        RECT  0 12.24 0.192 12.264 ;
    END
  END i[95]
  PIN i[96]
    DIRECTION INPUT ;
    USE SIGNAL ;
    PORT
      LAYER M4 ;
        RECT  0 12.336 0.192 12.36 ;
    END
  END i[96]
  PIN i[97]
    DIRECTION INPUT ;
    USE SIGNAL ;
    PORT
      LAYER M4 ;
        RECT  0 12.432 0.192 12.456 ;
    END
  END i[97]
  PIN i[98]
    DIRECTION INPUT ;
    USE SIGNAL ;
    PORT
      LAYER M4 ;
        RECT  0 12.576 0.192 12.6 ;
    END
  END i[98]
  PIN i[99]
    DIRECTION INPUT ;
    USE SIGNAL ;
    PORT
      LAYER M4 ;
        RECT  0 12.672 0.192 12.696 ;
    END
  END i[99]
  PIN i[9]
    DIRECTION INPUT ;
    USE SIGNAL ;
    PORT
      LAYER M4 ;
        RECT  0 3.168 0.192 3.192 ;
    END
  END i[9]
  PIN o[0]
    DIRECTION OUTPUT ;
    USE SIGNAL ;
    PORT
      LAYER M4 ;
        RECT  17.088 2.208 17.28 2.232 ;
    END
  END o[0]
  PIN o[100]
    DIRECTION OUTPUT ;
    USE SIGNAL ;
    PORT
      LAYER M4 ;
        RECT  17.088 12.768 17.28 12.792 ;
    END
  END o[100]
  PIN o[101]
    DIRECTION OUTPUT ;
    USE SIGNAL ;
    PORT
      LAYER M4 ;
        RECT  17.088 12.864 17.28 12.888 ;
    END
  END o[101]
  PIN o[102]
    DIRECTION OUTPUT ;
    USE SIGNAL ;
    PORT
      LAYER M4 ;
        RECT  17.088 12.96 17.28 12.984 ;
    END
  END o[102]
  PIN o[103]
    DIRECTION OUTPUT ;
    USE SIGNAL ;
    PORT
      LAYER M4 ;
        RECT  17.088 13.056 17.28 13.08 ;
    END
  END o[103]
  PIN o[104]
    DIRECTION OUTPUT ;
    USE SIGNAL ;
    PORT
      LAYER M4 ;
        RECT  17.088 13.152 17.28 13.176 ;
    END
  END o[104]
  PIN o[105]
    DIRECTION OUTPUT ;
    USE SIGNAL ;
    PORT
      LAYER M4 ;
        RECT  17.088 13.296 17.28 13.32 ;
    END
  END o[105]
  PIN o[106]
    DIRECTION OUTPUT ;
    USE SIGNAL ;
    PORT
      LAYER M4 ;
        RECT  17.088 13.392 17.28 13.416 ;
    END
  END o[106]
  PIN o[107]
    DIRECTION OUTPUT ;
    USE SIGNAL ;
    PORT
      LAYER M4 ;
        RECT  17.088 13.488 17.28 13.512 ;
    END
  END o[107]
  PIN o[108]
    DIRECTION OUTPUT ;
    USE SIGNAL ;
    PORT
      LAYER M4 ;
        RECT  17.088 13.584 17.28 13.608 ;
    END
  END o[108]
  PIN o[109]
    DIRECTION OUTPUT ;
    USE SIGNAL ;
    PORT
      LAYER M4 ;
        RECT  17.088 13.68 17.28 13.704 ;
    END
  END o[109]
  PIN o[10]
    DIRECTION OUTPUT ;
    USE SIGNAL ;
    PORT
      LAYER M4 ;
        RECT  17.088 3.264 17.28 3.288 ;
    END
  END o[10]
  PIN o[110]
    DIRECTION OUTPUT ;
    USE SIGNAL ;
    PORT
      LAYER M4 ;
        RECT  17.088 13.824 17.28 13.848 ;
    END
  END o[110]
  PIN o[111]
    DIRECTION OUTPUT ;
    USE SIGNAL ;
    PORT
      LAYER M4 ;
        RECT  17.088 13.92 17.28 13.944 ;
    END
  END o[111]
  PIN o[112]
    DIRECTION OUTPUT ;
    USE SIGNAL ;
    PORT
      LAYER M4 ;
        RECT  17.088 14.016 17.28 14.04 ;
    END
  END o[112]
  PIN o[113]
    DIRECTION OUTPUT ;
    USE SIGNAL ;
    PORT
      LAYER M4 ;
        RECT  17.088 14.112 17.28 14.136 ;
    END
  END o[113]
  PIN o[114]
    DIRECTION OUTPUT ;
    USE SIGNAL ;
    PORT
      LAYER M4 ;
        RECT  17.088 14.208 17.28 14.232 ;
    END
  END o[114]
  PIN o[115]
    DIRECTION OUTPUT ;
    USE SIGNAL ;
    PORT
      LAYER M4 ;
        RECT  17.088 14.352 17.28 14.376 ;
    END
  END o[115]
  PIN o[116]
    DIRECTION OUTPUT ;
    USE SIGNAL ;
    PORT
      LAYER M4 ;
        RECT  17.088 14.448 17.28 14.472 ;
    END
  END o[116]
  PIN o[117]
    DIRECTION OUTPUT ;
    USE SIGNAL ;
    PORT
      LAYER M4 ;
        RECT  17.088 14.544 17.28 14.568 ;
    END
  END o[117]
  PIN o[118]
    DIRECTION OUTPUT ;
    USE SIGNAL ;
    PORT
      LAYER M4 ;
        RECT  17.088 14.64 17.28 14.664 ;
    END
  END o[118]
  PIN o[119]
    DIRECTION OUTPUT ;
    USE SIGNAL ;
    PORT
      LAYER M4 ;
        RECT  17.088 14.736 17.28 14.76 ;
    END
  END o[119]
  PIN o[11]
    DIRECTION OUTPUT ;
    USE SIGNAL ;
    PORT
      LAYER M4 ;
        RECT  17.088 3.36 17.28 3.384 ;
    END
  END o[11]
  PIN o[120]
    DIRECTION OUTPUT ;
    USE SIGNAL ;
    PORT
      LAYER M4 ;
        RECT  17.088 14.88 17.28 14.904 ;
    END
  END o[120]
  PIN o[121]
    DIRECTION OUTPUT ;
    USE SIGNAL ;
    PORT
      LAYER M4 ;
        RECT  17.088 14.976 17.28 15 ;
    END
  END o[121]
  PIN o[122]
    DIRECTION OUTPUT ;
    USE SIGNAL ;
    PORT
      LAYER M4 ;
        RECT  17.088 15.072 17.28 15.096 ;
    END
  END o[122]
  PIN o[123]
    DIRECTION OUTPUT ;
    USE SIGNAL ;
    PORT
      LAYER M4 ;
        RECT  17.088 15.168 17.28 15.192 ;
    END
  END o[123]
  PIN o[124]
    DIRECTION OUTPUT ;
    USE SIGNAL ;
    PORT
      LAYER M4 ;
        RECT  17.088 15.264 17.28 15.288 ;
    END
  END o[124]
  PIN o[125]
    DIRECTION OUTPUT ;
    USE SIGNAL ;
    PORT
      LAYER M4 ;
        RECT  17.088 15.36 17.28 15.384 ;
    END
  END o[125]
  PIN o[126]
    DIRECTION OUTPUT ;
    USE SIGNAL ;
    PORT
      LAYER M4 ;
        RECT  17.088 15.504 17.28 15.528 ;
    END
  END o[126]
  PIN o[127]
    DIRECTION OUTPUT ;
    USE SIGNAL ;
    PORT
      LAYER M4 ;
        RECT  17.088 15.6 17.28 15.624 ;
    END
  END o[127]
  PIN o[128]
    DIRECTION OUTPUT ;
    USE SIGNAL ;
    PORT
      LAYER M4 ;
        RECT  17.088 15.696 17.28 15.72 ;
    END
  END o[128]
  PIN o[129]
    DIRECTION OUTPUT ;
    USE SIGNAL ;
    PORT
      LAYER M4 ;
        RECT  17.088 15.792 17.28 15.816 ;
    END
  END o[129]
  PIN o[12]
    DIRECTION OUTPUT ;
    USE SIGNAL ;
    PORT
      LAYER M4 ;
        RECT  17.088 3.504 17.28 3.528 ;
    END
  END o[12]
  PIN o[130]
    DIRECTION OUTPUT ;
    USE SIGNAL ;
    PORT
      LAYER M4 ;
        RECT  17.088 15.888 17.28 15.912 ;
    END
  END o[130]
  PIN o[131]
    DIRECTION OUTPUT ;
    USE SIGNAL ;
    PORT
      LAYER M4 ;
        RECT  17.088 16.032 17.28 16.056 ;
    END
  END o[131]
  PIN o[132]
    DIRECTION OUTPUT ;
    USE SIGNAL ;
    PORT
      LAYER M4 ;
        RECT  17.088 16.128 17.28 16.152 ;
    END
  END o[132]
  PIN o[133]
    DIRECTION OUTPUT ;
    USE SIGNAL ;
    PORT
      LAYER M4 ;
        RECT  17.088 16.224 17.28 16.248 ;
    END
  END o[133]
  PIN o[134]
    DIRECTION OUTPUT ;
    USE SIGNAL ;
    PORT
      LAYER M4 ;
        RECT  17.088 16.32 17.28 16.344 ;
    END
  END o[134]
  PIN o[135]
    DIRECTION OUTPUT ;
    USE SIGNAL ;
    PORT
      LAYER M4 ;
        RECT  17.088 16.416 17.28 16.44 ;
    END
  END o[135]
  PIN o[136]
    DIRECTION OUTPUT ;
    USE SIGNAL ;
    PORT
      LAYER M4 ;
        RECT  17.088 16.56 17.28 16.584 ;
    END
  END o[136]
  PIN o[137]
    DIRECTION OUTPUT ;
    USE SIGNAL ;
    PORT
      LAYER M4 ;
        RECT  17.088 16.656 17.28 16.68 ;
    END
  END o[137]
  PIN o[138]
    DIRECTION OUTPUT ;
    USE SIGNAL ;
    PORT
      LAYER M4 ;
        RECT  17.088 16.752 17.28 16.776 ;
    END
  END o[138]
  PIN o[139]
    DIRECTION OUTPUT ;
    USE SIGNAL ;
    PORT
      LAYER M4 ;
        RECT  17.088 16.848 17.28 16.872 ;
    END
  END o[139]
  PIN o[13]
    DIRECTION OUTPUT ;
    USE SIGNAL ;
    PORT
      LAYER M4 ;
        RECT  17.088 3.6 17.28 3.624 ;
    END
  END o[13]
  PIN o[140]
    DIRECTION OUTPUT ;
    USE SIGNAL ;
    PORT
      LAYER M4 ;
        RECT  17.088 16.944 17.28 16.968 ;
    END
  END o[140]
  PIN o[141]
    DIRECTION OUTPUT ;
    USE SIGNAL ;
    PORT
      LAYER M4 ;
        RECT  17.088 17.088 17.28 17.112 ;
    END
  END o[141]
  PIN o[142]
    DIRECTION OUTPUT ;
    USE SIGNAL ;
    PORT
      LAYER M4 ;
        RECT  17.088 17.184 17.28 17.208 ;
    END
  END o[142]
  PIN o[143]
    DIRECTION OUTPUT ;
    USE SIGNAL ;
    PORT
      LAYER M4 ;
        RECT  17.088 17.28 17.28 17.304 ;
    END
  END o[143]
  PIN o[144]
    DIRECTION OUTPUT ;
    USE SIGNAL ;
    PORT
      LAYER M4 ;
        RECT  17.088 17.376 17.28 17.4 ;
    END
  END o[144]
  PIN o[145]
    DIRECTION OUTPUT ;
    USE SIGNAL ;
    PORT
      LAYER M4 ;
        RECT  17.088 17.472 17.28 17.496 ;
    END
  END o[145]
  PIN o[146]
    DIRECTION OUTPUT ;
    USE SIGNAL ;
    PORT
      LAYER M4 ;
        RECT  17.088 17.616 17.28 17.64 ;
    END
  END o[146]
  PIN o[147]
    DIRECTION OUTPUT ;
    USE SIGNAL ;
    PORT
      LAYER M4 ;
        RECT  17.088 17.712 17.28 17.736 ;
    END
  END o[147]
  PIN o[148]
    DIRECTION OUTPUT ;
    USE SIGNAL ;
    PORT
      LAYER M4 ;
        RECT  17.088 17.808 17.28 17.832 ;
    END
  END o[148]
  PIN o[149]
    DIRECTION OUTPUT ;
    USE SIGNAL ;
    PORT
      LAYER M4 ;
        RECT  17.088 17.904 17.28 17.928 ;
    END
  END o[149]
  PIN o[14]
    DIRECTION OUTPUT ;
    USE SIGNAL ;
    PORT
      LAYER M4 ;
        RECT  17.088 3.696 17.28 3.72 ;
    END
  END o[14]
  PIN o[150]
    DIRECTION OUTPUT ;
    USE SIGNAL ;
    PORT
      LAYER M4 ;
        RECT  17.088 18 17.28 18.024 ;
    END
  END o[150]
  PIN o[151]
    DIRECTION OUTPUT ;
    USE SIGNAL ;
    PORT
      LAYER M4 ;
        RECT  17.088 18.096 17.28 18.12 ;
    END
  END o[151]
  PIN o[152]
    DIRECTION OUTPUT ;
    USE SIGNAL ;
    PORT
      LAYER M4 ;
        RECT  17.088 18.24 17.28 18.264 ;
    END
  END o[152]
  PIN o[153]
    DIRECTION OUTPUT ;
    USE SIGNAL ;
    PORT
      LAYER M4 ;
        RECT  17.088 18.336 17.28 18.36 ;
    END
  END o[153]
  PIN o[154]
    DIRECTION OUTPUT ;
    USE SIGNAL ;
    PORT
      LAYER M4 ;
        RECT  17.088 18.432 17.28 18.456 ;
    END
  END o[154]
  PIN o[155]
    DIRECTION OUTPUT ;
    USE SIGNAL ;
    PORT
      LAYER M4 ;
        RECT  17.088 18.528 17.28 18.552 ;
    END
  END o[155]
  PIN o[156]
    DIRECTION OUTPUT ;
    USE SIGNAL ;
    PORT
      LAYER M4 ;
        RECT  17.088 18.624 17.28 18.648 ;
    END
  END o[156]
  PIN o[157]
    DIRECTION OUTPUT ;
    USE SIGNAL ;
    PORT
      LAYER M4 ;
        RECT  17.088 18.768 17.28 18.792 ;
    END
  END o[157]
  PIN o[158]
    DIRECTION OUTPUT ;
    USE SIGNAL ;
    PORT
      LAYER M4 ;
        RECT  17.088 18.864 17.28 18.888 ;
    END
  END o[158]
  PIN o[159]
    DIRECTION OUTPUT ;
    USE SIGNAL ;
    PORT
      LAYER M4 ;
        RECT  17.088 18.96 17.28 18.984 ;
    END
  END o[159]
  PIN o[15]
    DIRECTION OUTPUT ;
    USE SIGNAL ;
    PORT
      LAYER M4 ;
        RECT  17.088 3.792 17.28 3.816 ;
    END
  END o[15]
  PIN o[160]
    DIRECTION OUTPUT ;
    USE SIGNAL ;
    PORT
      LAYER M4 ;
        RECT  17.088 19.056 17.28 19.08 ;
    END
  END o[160]
  PIN o[161]
    DIRECTION OUTPUT ;
    USE SIGNAL ;
    PORT
      LAYER M4 ;
        RECT  17.088 19.152 17.28 19.176 ;
    END
  END o[161]
  PIN o[162]
    DIRECTION OUTPUT ;
    USE SIGNAL ;
    PORT
      LAYER M4 ;
        RECT  17.088 19.296 17.28 19.32 ;
    END
  END o[162]
  PIN o[163]
    DIRECTION OUTPUT ;
    USE SIGNAL ;
    PORT
      LAYER M4 ;
        RECT  17.088 19.392 17.28 19.416 ;
    END
  END o[163]
  PIN o[164]
    DIRECTION OUTPUT ;
    USE SIGNAL ;
    PORT
      LAYER M4 ;
        RECT  17.088 19.488 17.28 19.512 ;
    END
  END o[164]
  PIN o[165]
    DIRECTION OUTPUT ;
    USE SIGNAL ;
    PORT
      LAYER M4 ;
        RECT  17.088 19.584 17.28 19.608 ;
    END
  END o[165]
  PIN o[166]
    DIRECTION OUTPUT ;
    USE SIGNAL ;
    PORT
      LAYER M4 ;
        RECT  17.088 19.68 17.28 19.704 ;
    END
  END o[166]
  PIN o[167]
    DIRECTION OUTPUT ;
    USE SIGNAL ;
    PORT
      LAYER M4 ;
        RECT  17.088 19.824 17.28 19.848 ;
    END
  END o[167]
  PIN o[168]
    DIRECTION OUTPUT ;
    USE SIGNAL ;
    PORT
      LAYER M4 ;
        RECT  17.088 19.92 17.28 19.944 ;
    END
  END o[168]
  PIN o[169]
    DIRECTION OUTPUT ;
    USE SIGNAL ;
    PORT
      LAYER M4 ;
        RECT  17.088 20.016 17.28 20.04 ;
    END
  END o[169]
  PIN o[16]
    DIRECTION OUTPUT ;
    USE SIGNAL ;
    PORT
      LAYER M4 ;
        RECT  17.088 3.888 17.28 3.912 ;
    END
  END o[16]
  PIN o[170]
    DIRECTION OUTPUT ;
    USE SIGNAL ;
    PORT
      LAYER M4 ;
        RECT  17.088 20.112 17.28 20.136 ;
    END
  END o[170]
  PIN o[171]
    DIRECTION OUTPUT ;
    USE SIGNAL ;
    PORT
      LAYER M4 ;
        RECT  17.088 20.208 17.28 20.232 ;
    END
  END o[171]
  PIN o[172]
    DIRECTION OUTPUT ;
    USE SIGNAL ;
    PORT
      LAYER M4 ;
        RECT  17.088 20.352 17.28 20.376 ;
    END
  END o[172]
  PIN o[173]
    DIRECTION OUTPUT ;
    USE SIGNAL ;
    PORT
      LAYER M4 ;
        RECT  17.088 20.448 17.28 20.472 ;
    END
  END o[173]
  PIN o[174]
    DIRECTION OUTPUT ;
    USE SIGNAL ;
    PORT
      LAYER M4 ;
        RECT  17.088 20.544 17.28 20.568 ;
    END
  END o[174]
  PIN o[175]
    DIRECTION OUTPUT ;
    USE SIGNAL ;
    PORT
      LAYER M4 ;
        RECT  17.088 20.64 17.28 20.664 ;
    END
  END o[175]
  PIN o[176]
    DIRECTION OUTPUT ;
    USE SIGNAL ;
    PORT
      LAYER M4 ;
        RECT  17.088 20.736 17.28 20.76 ;
    END
  END o[176]
  PIN o[177]
    DIRECTION OUTPUT ;
    USE SIGNAL ;
    PORT
      LAYER M4 ;
        RECT  17.088 20.88 17.28 20.904 ;
    END
  END o[177]
  PIN o[178]
    DIRECTION OUTPUT ;
    USE SIGNAL ;
    PORT
      LAYER M4 ;
        RECT  17.088 20.976 17.28 21 ;
    END
  END o[178]
  PIN o[179]
    DIRECTION OUTPUT ;
    USE SIGNAL ;
    PORT
      LAYER M4 ;
        RECT  17.088 21.072 17.28 21.096 ;
    END
  END o[179]
  PIN o[17]
    DIRECTION OUTPUT ;
    USE SIGNAL ;
    PORT
      LAYER M4 ;
        RECT  17.088 4.032 17.28 4.056 ;
    END
  END o[17]
  PIN o[180]
    DIRECTION OUTPUT ;
    USE SIGNAL ;
    PORT
      LAYER M4 ;
        RECT  17.088 21.168 17.28 21.192 ;
    END
  END o[180]
  PIN o[181]
    DIRECTION OUTPUT ;
    USE SIGNAL ;
    PORT
      LAYER M4 ;
        RECT  17.088 21.264 17.28 21.288 ;
    END
  END o[181]
  PIN o[182]
    DIRECTION OUTPUT ;
    USE SIGNAL ;
    PORT
      LAYER M4 ;
        RECT  17.088 21.36 17.28 21.384 ;
    END
  END o[182]
  PIN o[183]
    DIRECTION OUTPUT ;
    USE SIGNAL ;
    PORT
      LAYER M4 ;
        RECT  17.088 21.504 17.28 21.528 ;
    END
  END o[183]
  PIN o[184]
    DIRECTION OUTPUT ;
    USE SIGNAL ;
    PORT
      LAYER M4 ;
        RECT  17.088 21.6 17.28 21.624 ;
    END
  END o[184]
  PIN o[185]
    DIRECTION OUTPUT ;
    USE SIGNAL ;
    PORT
      LAYER M4 ;
        RECT  17.088 21.696 17.28 21.72 ;
    END
  END o[185]
  PIN o[186]
    DIRECTION OUTPUT ;
    USE SIGNAL ;
    PORT
      LAYER M4 ;
        RECT  17.088 21.792 17.28 21.816 ;
    END
  END o[186]
  PIN o[187]
    DIRECTION OUTPUT ;
    USE SIGNAL ;
    PORT
      LAYER M4 ;
        RECT  17.088 21.888 17.28 21.912 ;
    END
  END o[187]
  PIN o[188]
    DIRECTION OUTPUT ;
    USE SIGNAL ;
    PORT
      LAYER M4 ;
        RECT  17.088 22.032 17.28 22.056 ;
    END
  END o[188]
  PIN o[189]
    DIRECTION OUTPUT ;
    USE SIGNAL ;
    PORT
      LAYER M4 ;
        RECT  17.088 22.128 17.28 22.152 ;
    END
  END o[189]
  PIN o[18]
    DIRECTION OUTPUT ;
    USE SIGNAL ;
    PORT
      LAYER M4 ;
        RECT  17.088 4.128 17.28 4.152 ;
    END
  END o[18]
  PIN o[190]
    DIRECTION OUTPUT ;
    USE SIGNAL ;
    PORT
      LAYER M4 ;
        RECT  17.088 22.224 17.28 22.248 ;
    END
  END o[190]
  PIN o[191]
    DIRECTION OUTPUT ;
    USE SIGNAL ;
    PORT
      LAYER M4 ;
        RECT  17.088 22.32 17.28 22.344 ;
    END
  END o[191]
  PIN o[192]
    DIRECTION OUTPUT ;
    USE SIGNAL ;
    PORT
      LAYER M4 ;
        RECT  17.088 22.416 17.28 22.44 ;
    END
  END o[192]
  PIN o[193]
    DIRECTION OUTPUT ;
    USE SIGNAL ;
    PORT
      LAYER M4 ;
        RECT  17.088 22.56 17.28 22.584 ;
    END
  END o[193]
  PIN o[194]
    DIRECTION OUTPUT ;
    USE SIGNAL ;
    PORT
      LAYER M4 ;
        RECT  17.088 22.656 17.28 22.68 ;
    END
  END o[194]
  PIN o[195]
    DIRECTION OUTPUT ;
    USE SIGNAL ;
    PORT
      LAYER M4 ;
        RECT  17.088 22.752 17.28 22.776 ;
    END
  END o[195]
  PIN o[196]
    DIRECTION OUTPUT ;
    USE SIGNAL ;
    PORT
      LAYER M4 ;
        RECT  17.088 22.848 17.28 22.872 ;
    END
  END o[196]
  PIN o[197]
    DIRECTION OUTPUT ;
    USE SIGNAL ;
    PORT
      LAYER M4 ;
        RECT  17.088 22.944 17.28 22.968 ;
    END
  END o[197]
  PIN o[198]
    DIRECTION OUTPUT ;
    USE SIGNAL ;
    PORT
      LAYER M4 ;
        RECT  17.088 23.088 17.28 23.112 ;
    END
  END o[198]
  PIN o[199]
    DIRECTION OUTPUT ;
    USE SIGNAL ;
    PORT
      LAYER M4 ;
        RECT  17.088 23.184 17.28 23.208 ;
    END
  END o[199]
  PIN o[19]
    DIRECTION OUTPUT ;
    USE SIGNAL ;
    PORT
      LAYER M4 ;
        RECT  17.088 4.224 17.28 4.248 ;
    END
  END o[19]
  PIN o[1]
    DIRECTION OUTPUT ;
    USE SIGNAL ;
    PORT
      LAYER M4 ;
        RECT  17.088 2.352 17.28 2.376 ;
    END
  END o[1]
  PIN o[200]
    DIRECTION OUTPUT ;
    USE SIGNAL ;
    PORT
      LAYER M4 ;
        RECT  17.088 23.28 17.28 23.304 ;
    END
  END o[200]
  PIN o[201]
    DIRECTION OUTPUT ;
    USE SIGNAL ;
    PORT
      LAYER M4 ;
        RECT  17.088 23.376 17.28 23.4 ;
    END
  END o[201]
  PIN o[202]
    DIRECTION OUTPUT ;
    USE SIGNAL ;
    PORT
      LAYER M4 ;
        RECT  17.088 23.472 17.28 23.496 ;
    END
  END o[202]
  PIN o[203]
    DIRECTION OUTPUT ;
    USE SIGNAL ;
    PORT
      LAYER M4 ;
        RECT  17.088 23.616 17.28 23.64 ;
    END
  END o[203]
  PIN o[204]
    DIRECTION OUTPUT ;
    USE SIGNAL ;
    PORT
      LAYER M4 ;
        RECT  17.088 23.712 17.28 23.736 ;
    END
  END o[204]
  PIN o[205]
    DIRECTION OUTPUT ;
    USE SIGNAL ;
    PORT
      LAYER M4 ;
        RECT  17.088 23.808 17.28 23.832 ;
    END
  END o[205]
  PIN o[206]
    DIRECTION OUTPUT ;
    USE SIGNAL ;
    PORT
      LAYER M4 ;
        RECT  17.088 23.904 17.28 23.928 ;
    END
  END o[206]
  PIN o[207]
    DIRECTION OUTPUT ;
    USE SIGNAL ;
    PORT
      LAYER M4 ;
        RECT  17.088 24 17.28 24.024 ;
    END
  END o[207]
  PIN o[208]
    DIRECTION OUTPUT ;
    USE SIGNAL ;
    PORT
      LAYER M4 ;
        RECT  17.088 24.096 17.28 24.12 ;
    END
  END o[208]
  PIN o[209]
    DIRECTION OUTPUT ;
    USE SIGNAL ;
    PORT
      LAYER M4 ;
        RECT  17.088 24.24 17.28 24.264 ;
    END
  END o[209]
  PIN o[20]
    DIRECTION OUTPUT ;
    USE SIGNAL ;
    PORT
      LAYER M4 ;
        RECT  17.088 4.32 17.28 4.344 ;
    END
  END o[20]
  PIN o[210]
    DIRECTION OUTPUT ;
    USE SIGNAL ;
    PORT
      LAYER M4 ;
        RECT  17.088 24.336 17.28 24.36 ;
    END
  END o[210]
  PIN o[211]
    DIRECTION OUTPUT ;
    USE SIGNAL ;
    PORT
      LAYER M4 ;
        RECT  17.088 24.432 17.28 24.456 ;
    END
  END o[211]
  PIN o[212]
    DIRECTION OUTPUT ;
    USE SIGNAL ;
    PORT
      LAYER M4 ;
        RECT  17.088 24.528 17.28 24.552 ;
    END
  END o[212]
  PIN o[213]
    DIRECTION OUTPUT ;
    USE SIGNAL ;
    PORT
      LAYER M4 ;
        RECT  17.088 24.624 17.28 24.648 ;
    END
  END o[213]
  PIN o[214]
    DIRECTION OUTPUT ;
    USE SIGNAL ;
    PORT
      LAYER M4 ;
        RECT  17.088 24.768 17.28 24.792 ;
    END
  END o[214]
  PIN o[215]
    DIRECTION OUTPUT ;
    USE SIGNAL ;
    PORT
      LAYER M4 ;
        RECT  17.088 24.864 17.28 24.888 ;
    END
  END o[215]
  PIN o[216]
    DIRECTION OUTPUT ;
    USE SIGNAL ;
    PORT
      LAYER M4 ;
        RECT  17.088 24.96 17.28 24.984 ;
    END
  END o[216]
  PIN o[217]
    DIRECTION OUTPUT ;
    USE SIGNAL ;
    PORT
      LAYER M4 ;
        RECT  17.088 25.056 17.28 25.08 ;
    END
  END o[217]
  PIN o[218]
    DIRECTION OUTPUT ;
    USE SIGNAL ;
    PORT
      LAYER M4 ;
        RECT  17.088 25.152 17.28 25.176 ;
    END
  END o[218]
  PIN o[219]
    DIRECTION OUTPUT ;
    USE SIGNAL ;
    PORT
      LAYER M4 ;
        RECT  17.088 25.296 17.28 25.32 ;
    END
  END o[219]
  PIN o[21]
    DIRECTION OUTPUT ;
    USE SIGNAL ;
    PORT
      LAYER M4 ;
        RECT  17.088 4.416 17.28 4.44 ;
    END
  END o[21]
  PIN o[220]
    DIRECTION OUTPUT ;
    USE SIGNAL ;
    PORT
      LAYER M4 ;
        RECT  17.088 25.392 17.28 25.416 ;
    END
  END o[220]
  PIN o[221]
    DIRECTION OUTPUT ;
    USE SIGNAL ;
    PORT
      LAYER M4 ;
        RECT  17.088 25.488 17.28 25.512 ;
    END
  END o[221]
  PIN o[222]
    DIRECTION OUTPUT ;
    USE SIGNAL ;
    PORT
      LAYER M4 ;
        RECT  17.088 25.584 17.28 25.608 ;
    END
  END o[222]
  PIN o[223]
    DIRECTION OUTPUT ;
    USE SIGNAL ;
    PORT
      LAYER M4 ;
        RECT  17.088 25.68 17.28 25.704 ;
    END
  END o[223]
  PIN o[224]
    DIRECTION OUTPUT ;
    USE SIGNAL ;
    PORT
      LAYER M4 ;
        RECT  17.088 25.824 17.28 25.848 ;
    END
  END o[224]
  PIN o[225]
    DIRECTION OUTPUT ;
    USE SIGNAL ;
    PORT
      LAYER M4 ;
        RECT  17.088 25.92 17.28 25.944 ;
    END
  END o[225]
  PIN o[226]
    DIRECTION OUTPUT ;
    USE SIGNAL ;
    PORT
      LAYER M4 ;
        RECT  17.088 26.016 17.28 26.04 ;
    END
  END o[226]
  PIN o[227]
    DIRECTION OUTPUT ;
    USE SIGNAL ;
    PORT
      LAYER M4 ;
        RECT  17.088 26.112 17.28 26.136 ;
    END
  END o[227]
  PIN o[228]
    DIRECTION OUTPUT ;
    USE SIGNAL ;
    PORT
      LAYER M4 ;
        RECT  17.088 26.208 17.28 26.232 ;
    END
  END o[228]
  PIN o[229]
    DIRECTION OUTPUT ;
    USE SIGNAL ;
    PORT
      LAYER M4 ;
        RECT  17.088 26.352 17.28 26.376 ;
    END
  END o[229]
  PIN o[22]
    DIRECTION OUTPUT ;
    USE SIGNAL ;
    PORT
      LAYER M4 ;
        RECT  17.088 4.56 17.28 4.584 ;
    END
  END o[22]
  PIN o[230]
    DIRECTION OUTPUT ;
    USE SIGNAL ;
    PORT
      LAYER M4 ;
        RECT  17.088 26.448 17.28 26.472 ;
    END
  END o[230]
  PIN o[231]
    DIRECTION OUTPUT ;
    USE SIGNAL ;
    PORT
      LAYER M4 ;
        RECT  17.088 26.544 17.28 26.568 ;
    END
  END o[231]
  PIN o[232]
    DIRECTION OUTPUT ;
    USE SIGNAL ;
    PORT
      LAYER M4 ;
        RECT  17.088 26.64 17.28 26.664 ;
    END
  END o[232]
  PIN o[233]
    DIRECTION OUTPUT ;
    USE SIGNAL ;
    PORT
      LAYER M4 ;
        RECT  17.088 26.736 17.28 26.76 ;
    END
  END o[233]
  PIN o[234]
    DIRECTION OUTPUT ;
    USE SIGNAL ;
    PORT
      LAYER M4 ;
        RECT  17.088 26.88 17.28 26.904 ;
    END
  END o[234]
  PIN o[235]
    DIRECTION OUTPUT ;
    USE SIGNAL ;
    PORT
      LAYER M4 ;
        RECT  17.088 26.976 17.28 27 ;
    END
  END o[235]
  PIN o[236]
    DIRECTION OUTPUT ;
    USE SIGNAL ;
    PORT
      LAYER M4 ;
        RECT  17.088 27.072 17.28 27.096 ;
    END
  END o[236]
  PIN o[237]
    DIRECTION OUTPUT ;
    USE SIGNAL ;
    PORT
      LAYER M4 ;
        RECT  17.088 27.168 17.28 27.192 ;
    END
  END o[237]
  PIN o[238]
    DIRECTION OUTPUT ;
    USE SIGNAL ;
    PORT
      LAYER M4 ;
        RECT  17.088 27.264 17.28 27.288 ;
    END
  END o[238]
  PIN o[239]
    DIRECTION OUTPUT ;
    USE SIGNAL ;
    PORT
      LAYER M4 ;
        RECT  17.088 27.36 17.28 27.384 ;
    END
  END o[239]
  PIN o[23]
    DIRECTION OUTPUT ;
    USE SIGNAL ;
    PORT
      LAYER M4 ;
        RECT  17.088 4.656 17.28 4.68 ;
    END
  END o[23]
  PIN o[240]
    DIRECTION OUTPUT ;
    USE SIGNAL ;
    PORT
      LAYER M4 ;
        RECT  17.088 27.504 17.28 27.528 ;
    END
  END o[240]
  PIN o[241]
    DIRECTION OUTPUT ;
    USE SIGNAL ;
    PORT
      LAYER M4 ;
        RECT  17.088 27.6 17.28 27.624 ;
    END
  END o[241]
  PIN o[242]
    DIRECTION OUTPUT ;
    USE SIGNAL ;
    PORT
      LAYER M4 ;
        RECT  17.088 27.696 17.28 27.72 ;
    END
  END o[242]
  PIN o[243]
    DIRECTION OUTPUT ;
    USE SIGNAL ;
    PORT
      LAYER M4 ;
        RECT  17.088 27.792 17.28 27.816 ;
    END
  END o[243]
  PIN o[244]
    DIRECTION OUTPUT ;
    USE SIGNAL ;
    PORT
      LAYER M4 ;
        RECT  17.088 27.888 17.28 27.912 ;
    END
  END o[244]
  PIN o[245]
    DIRECTION OUTPUT ;
    USE SIGNAL ;
    PORT
      LAYER M4 ;
        RECT  17.088 28.032 17.28 28.056 ;
    END
  END o[245]
  PIN o[246]
    DIRECTION OUTPUT ;
    USE SIGNAL ;
    PORT
      LAYER M4 ;
        RECT  17.088 28.128 17.28 28.152 ;
    END
  END o[246]
  PIN o[247]
    DIRECTION OUTPUT ;
    USE SIGNAL ;
    PORT
      LAYER M4 ;
        RECT  17.088 28.224 17.28 28.248 ;
    END
  END o[247]
  PIN o[248]
    DIRECTION OUTPUT ;
    USE SIGNAL ;
    PORT
      LAYER M4 ;
        RECT  17.088 28.32 17.28 28.344 ;
    END
  END o[248]
  PIN o[249]
    DIRECTION OUTPUT ;
    USE SIGNAL ;
    PORT
      LAYER M4 ;
        RECT  17.088 28.416 17.28 28.44 ;
    END
  END o[249]
  PIN o[24]
    DIRECTION OUTPUT ;
    USE SIGNAL ;
    PORT
      LAYER M4 ;
        RECT  17.088 4.752 17.28 4.776 ;
    END
  END o[24]
  PIN o[250]
    DIRECTION OUTPUT ;
    USE SIGNAL ;
    PORT
      LAYER M4 ;
        RECT  17.088 28.56 17.28 28.584 ;
    END
  END o[250]
  PIN o[251]
    DIRECTION OUTPUT ;
    USE SIGNAL ;
    PORT
      LAYER M4 ;
        RECT  17.088 28.656 17.28 28.68 ;
    END
  END o[251]
  PIN o[252]
    DIRECTION OUTPUT ;
    USE SIGNAL ;
    PORT
      LAYER M4 ;
        RECT  17.088 28.752 17.28 28.776 ;
    END
  END o[252]
  PIN o[253]
    DIRECTION OUTPUT ;
    USE SIGNAL ;
    PORT
      LAYER M4 ;
        RECT  17.088 28.848 17.28 28.872 ;
    END
  END o[253]
  PIN o[254]
    DIRECTION OUTPUT ;
    USE SIGNAL ;
    PORT
      LAYER M4 ;
        RECT  17.088 28.944 17.28 28.968 ;
    END
  END o[254]
  PIN o[255]
    DIRECTION OUTPUT ;
    USE SIGNAL ;
    PORT
      LAYER M4 ;
        RECT  17.088 29.088 17.28 29.112 ;
    END
  END o[255]
  PIN o[256]
    DIRECTION OUTPUT ;
    USE SIGNAL ;
    PORT
      LAYER M4 ;
        RECT  17.088 29.184 17.28 29.208 ;
    END
  END o[256]
  PIN o[257]
    DIRECTION OUTPUT ;
    USE SIGNAL ;
    PORT
      LAYER M4 ;
        RECT  17.088 29.28 17.28 29.304 ;
    END
  END o[257]
  PIN o[258]
    DIRECTION OUTPUT ;
    USE SIGNAL ;
    PORT
      LAYER M4 ;
        RECT  17.088 29.376 17.28 29.4 ;
    END
  END o[258]
  PIN o[259]
    DIRECTION OUTPUT ;
    USE SIGNAL ;
    PORT
      LAYER M4 ;
        RECT  17.088 29.472 17.28 29.496 ;
    END
  END o[259]
  PIN o[25]
    DIRECTION OUTPUT ;
    USE SIGNAL ;
    PORT
      LAYER M4 ;
        RECT  17.088 4.848 17.28 4.872 ;
    END
  END o[25]
  PIN o[260]
    DIRECTION OUTPUT ;
    USE SIGNAL ;
    PORT
      LAYER M4 ;
        RECT  17.088 29.616 17.28 29.64 ;
    END
  END o[260]
  PIN o[261]
    DIRECTION OUTPUT ;
    USE SIGNAL ;
    PORT
      LAYER M4 ;
        RECT  17.088 29.712 17.28 29.736 ;
    END
  END o[261]
  PIN o[262]
    DIRECTION OUTPUT ;
    USE SIGNAL ;
    PORT
      LAYER M4 ;
        RECT  17.088 29.808 17.28 29.832 ;
    END
  END o[262]
  PIN o[263]
    DIRECTION OUTPUT ;
    USE SIGNAL ;
    PORT
      LAYER M4 ;
        RECT  17.088 29.904 17.28 29.928 ;
    END
  END o[263]
  PIN o[264]
    DIRECTION OUTPUT ;
    USE SIGNAL ;
    PORT
      LAYER M4 ;
        RECT  17.088 30 17.28 30.024 ;
    END
  END o[264]
  PIN o[265]
    DIRECTION OUTPUT ;
    USE SIGNAL ;
    PORT
      LAYER M4 ;
        RECT  17.088 30.096 17.28 30.12 ;
    END
  END o[265]
  PIN o[266]
    DIRECTION OUTPUT ;
    USE SIGNAL ;
    PORT
      LAYER M4 ;
        RECT  17.088 30.24 17.28 30.264 ;
    END
  END o[266]
  PIN o[267]
    DIRECTION OUTPUT ;
    USE SIGNAL ;
    PORT
      LAYER M4 ;
        RECT  17.088 30.336 17.28 30.36 ;
    END
  END o[267]
  PIN o[268]
    DIRECTION OUTPUT ;
    USE SIGNAL ;
    PORT
      LAYER M4 ;
        RECT  17.088 30.432 17.28 30.456 ;
    END
  END o[268]
  PIN o[269]
    DIRECTION OUTPUT ;
    USE SIGNAL ;
    PORT
      LAYER M4 ;
        RECT  17.088 30.528 17.28 30.552 ;
    END
  END o[269]
  PIN o[26]
    DIRECTION OUTPUT ;
    USE SIGNAL ;
    PORT
      LAYER M4 ;
        RECT  17.088 4.944 17.28 4.968 ;
    END
  END o[26]
  PIN o[270]
    DIRECTION OUTPUT ;
    USE SIGNAL ;
    PORT
      LAYER M4 ;
        RECT  17.088 30.624 17.28 30.648 ;
    END
  END o[270]
  PIN o[271]
    DIRECTION OUTPUT ;
    USE SIGNAL ;
    PORT
      LAYER M4 ;
        RECT  17.088 30.768 17.28 30.792 ;
    END
  END o[271]
  PIN o[272]
    DIRECTION OUTPUT ;
    USE SIGNAL ;
    PORT
      LAYER M4 ;
        RECT  17.088 30.864 17.28 30.888 ;
    END
  END o[272]
  PIN o[273]
    DIRECTION OUTPUT ;
    USE SIGNAL ;
    PORT
      LAYER M4 ;
        RECT  17.088 30.96 17.28 30.984 ;
    END
  END o[273]
  PIN o[274]
    DIRECTION OUTPUT ;
    USE SIGNAL ;
    PORT
      LAYER M4 ;
        RECT  17.088 31.056 17.28 31.08 ;
    END
  END o[274]
  PIN o[275]
    DIRECTION OUTPUT ;
    USE SIGNAL ;
    PORT
      LAYER M4 ;
        RECT  17.088 31.152 17.28 31.176 ;
    END
  END o[275]
  PIN o[276]
    DIRECTION OUTPUT ;
    USE SIGNAL ;
    PORT
      LAYER M4 ;
        RECT  17.088 31.296 17.28 31.32 ;
    END
  END o[276]
  PIN o[277]
    DIRECTION OUTPUT ;
    USE SIGNAL ;
    PORT
      LAYER M4 ;
        RECT  17.088 31.392 17.28 31.416 ;
    END
  END o[277]
  PIN o[278]
    DIRECTION OUTPUT ;
    USE SIGNAL ;
    PORT
      LAYER M4 ;
        RECT  17.088 31.488 17.28 31.512 ;
    END
  END o[278]
  PIN o[279]
    DIRECTION OUTPUT ;
    USE SIGNAL ;
    PORT
      LAYER M4 ;
        RECT  17.088 31.584 17.28 31.608 ;
    END
  END o[279]
  PIN o[27]
    DIRECTION OUTPUT ;
    USE SIGNAL ;
    PORT
      LAYER M4 ;
        RECT  17.088 5.088 17.28 5.112 ;
    END
  END o[27]
  PIN o[280]
    DIRECTION OUTPUT ;
    USE SIGNAL ;
    PORT
      LAYER M4 ;
        RECT  17.088 31.68 17.28 31.704 ;
    END
  END o[280]
  PIN o[281]
    DIRECTION OUTPUT ;
    USE SIGNAL ;
    PORT
      LAYER M4 ;
        RECT  17.088 31.824 17.28 31.848 ;
    END
  END o[281]
  PIN o[282]
    DIRECTION OUTPUT ;
    USE SIGNAL ;
    PORT
      LAYER M4 ;
        RECT  17.088 31.92 17.28 31.944 ;
    END
  END o[282]
  PIN o[283]
    DIRECTION OUTPUT ;
    USE SIGNAL ;
    PORT
      LAYER M4 ;
        RECT  17.088 32.016 17.28 32.04 ;
    END
  END o[283]
  PIN o[284]
    DIRECTION OUTPUT ;
    USE SIGNAL ;
    PORT
      LAYER M4 ;
        RECT  17.088 32.112 17.28 32.136 ;
    END
  END o[284]
  PIN o[285]
    DIRECTION OUTPUT ;
    USE SIGNAL ;
    PORT
      LAYER M4 ;
        RECT  17.088 32.208 17.28 32.232 ;
    END
  END o[285]
  PIN o[286]
    DIRECTION OUTPUT ;
    USE SIGNAL ;
    PORT
      LAYER M4 ;
        RECT  17.088 32.352 17.28 32.376 ;
    END
  END o[286]
  PIN o[287]
    DIRECTION OUTPUT ;
    USE SIGNAL ;
    PORT
      LAYER M4 ;
        RECT  17.088 32.448 17.28 32.472 ;
    END
  END o[287]
  PIN o[288]
    DIRECTION OUTPUT ;
    USE SIGNAL ;
    PORT
      LAYER M4 ;
        RECT  17.088 32.544 17.28 32.568 ;
    END
  END o[288]
  PIN o[289]
    DIRECTION OUTPUT ;
    USE SIGNAL ;
    PORT
      LAYER M4 ;
        RECT  17.088 32.64 17.28 32.664 ;
    END
  END o[289]
  PIN o[28]
    DIRECTION OUTPUT ;
    USE SIGNAL ;
    PORT
      LAYER M4 ;
        RECT  17.088 5.184 17.28 5.208 ;
    END
  END o[28]
  PIN o[290]
    DIRECTION OUTPUT ;
    USE SIGNAL ;
    PORT
      LAYER M4 ;
        RECT  17.088 32.736 17.28 32.76 ;
    END
  END o[290]
  PIN o[291]
    DIRECTION OUTPUT ;
    USE SIGNAL ;
    PORT
      LAYER M4 ;
        RECT  17.088 32.88 17.28 32.904 ;
    END
  END o[291]
  PIN o[292]
    DIRECTION OUTPUT ;
    USE SIGNAL ;
    PORT
      LAYER M4 ;
        RECT  17.088 32.976 17.28 33 ;
    END
  END o[292]
  PIN o[293]
    DIRECTION OUTPUT ;
    USE SIGNAL ;
    PORT
      LAYER M4 ;
        RECT  17.088 33.072 17.28 33.096 ;
    END
  END o[293]
  PIN o[294]
    DIRECTION OUTPUT ;
    USE SIGNAL ;
    PORT
      LAYER M4 ;
        RECT  17.088 33.168 17.28 33.192 ;
    END
  END o[294]
  PIN o[295]
    DIRECTION OUTPUT ;
    USE SIGNAL ;
    PORT
      LAYER M4 ;
        RECT  17.088 33.264 17.28 33.288 ;
    END
  END o[295]
  PIN o[296]
    DIRECTION OUTPUT ;
    USE SIGNAL ;
    PORT
      LAYER M4 ;
        RECT  17.088 33.36 17.28 33.384 ;
    END
  END o[296]
  PIN o[297]
    DIRECTION OUTPUT ;
    USE SIGNAL ;
    PORT
      LAYER M4 ;
        RECT  17.088 33.504 17.28 33.528 ;
    END
  END o[297]
  PIN o[298]
    DIRECTION OUTPUT ;
    USE SIGNAL ;
    PORT
      LAYER M4 ;
        RECT  17.088 33.6 17.28 33.624 ;
    END
  END o[298]
  PIN o[299]
    DIRECTION OUTPUT ;
    USE SIGNAL ;
    PORT
      LAYER M4 ;
        RECT  17.088 33.696 17.28 33.72 ;
    END
  END o[299]
  PIN o[29]
    DIRECTION OUTPUT ;
    USE SIGNAL ;
    PORT
      LAYER M4 ;
        RECT  17.088 5.28 17.28 5.304 ;
    END
  END o[29]
  PIN o[2]
    DIRECTION OUTPUT ;
    USE SIGNAL ;
    PORT
      LAYER M4 ;
        RECT  17.088 2.448 17.28 2.472 ;
    END
  END o[2]
  PIN o[300]
    DIRECTION OUTPUT ;
    USE SIGNAL ;
    PORT
      LAYER M4 ;
        RECT  17.088 33.792 17.28 33.816 ;
    END
  END o[300]
  PIN o[301]
    DIRECTION OUTPUT ;
    USE SIGNAL ;
    PORT
      LAYER M4 ;
        RECT  17.088 33.888 17.28 33.912 ;
    END
  END o[301]
  PIN o[302]
    DIRECTION OUTPUT ;
    USE SIGNAL ;
    PORT
      LAYER M4 ;
        RECT  17.088 34.032 17.28 34.056 ;
    END
  END o[302]
  PIN o[303]
    DIRECTION OUTPUT ;
    USE SIGNAL ;
    PORT
      LAYER M4 ;
        RECT  17.088 34.128 17.28 34.152 ;
    END
  END o[303]
  PIN o[304]
    DIRECTION OUTPUT ;
    USE SIGNAL ;
    PORT
      LAYER M4 ;
        RECT  17.088 34.224 17.28 34.248 ;
    END
  END o[304]
  PIN o[305]
    DIRECTION OUTPUT ;
    USE SIGNAL ;
    PORT
      LAYER M4 ;
        RECT  17.088 34.32 17.28 34.344 ;
    END
  END o[305]
  PIN o[306]
    DIRECTION OUTPUT ;
    USE SIGNAL ;
    PORT
      LAYER M4 ;
        RECT  17.088 34.416 17.28 34.44 ;
    END
  END o[306]
  PIN o[307]
    DIRECTION OUTPUT ;
    USE SIGNAL ;
    PORT
      LAYER M4 ;
        RECT  17.088 34.56 17.28 34.584 ;
    END
  END o[307]
  PIN o[308]
    DIRECTION OUTPUT ;
    USE SIGNAL ;
    PORT
      LAYER M4 ;
        RECT  17.088 34.656 17.28 34.68 ;
    END
  END o[308]
  PIN o[309]
    DIRECTION OUTPUT ;
    USE SIGNAL ;
    PORT
      LAYER M4 ;
        RECT  17.088 34.752 17.28 34.776 ;
    END
  END o[309]
  PIN o[30]
    DIRECTION OUTPUT ;
    USE SIGNAL ;
    PORT
      LAYER M4 ;
        RECT  17.088 5.376 17.28 5.4 ;
    END
  END o[30]
  PIN o[310]
    DIRECTION OUTPUT ;
    USE SIGNAL ;
    PORT
      LAYER M4 ;
        RECT  17.088 34.848 17.28 34.872 ;
    END
  END o[310]
  PIN o[311]
    DIRECTION OUTPUT ;
    USE SIGNAL ;
    PORT
      LAYER M4 ;
        RECT  17.088 34.944 17.28 34.968 ;
    END
  END o[311]
  PIN o[312]
    DIRECTION OUTPUT ;
    USE SIGNAL ;
    PORT
      LAYER M4 ;
        RECT  17.088 35.088 17.28 35.112 ;
    END
  END o[312]
  PIN o[313]
    DIRECTION OUTPUT ;
    USE SIGNAL ;
    PORT
      LAYER M4 ;
        RECT  17.088 35.184 17.28 35.208 ;
    END
  END o[313]
  PIN o[314]
    DIRECTION OUTPUT ;
    USE SIGNAL ;
    PORT
      LAYER M4 ;
        RECT  17.088 35.28 17.28 35.304 ;
    END
  END o[314]
  PIN o[315]
    DIRECTION OUTPUT ;
    USE SIGNAL ;
    PORT
      LAYER M4 ;
        RECT  17.088 35.376 17.28 35.4 ;
    END
  END o[315]
  PIN o[316]
    DIRECTION OUTPUT ;
    USE SIGNAL ;
    PORT
      LAYER M4 ;
        RECT  17.088 35.472 17.28 35.496 ;
    END
  END o[316]
  PIN o[317]
    DIRECTION OUTPUT ;
    USE SIGNAL ;
    PORT
      LAYER M4 ;
        RECT  17.088 35.616 17.28 35.64 ;
    END
  END o[317]
  PIN o[318]
    DIRECTION OUTPUT ;
    USE SIGNAL ;
    PORT
      LAYER M4 ;
        RECT  17.088 35.712 17.28 35.736 ;
    END
  END o[318]
  PIN o[319]
    DIRECTION OUTPUT ;
    USE SIGNAL ;
    PORT
      LAYER M4 ;
        RECT  17.088 35.808 17.28 35.832 ;
    END
  END o[319]
  PIN o[31]
    DIRECTION OUTPUT ;
    USE SIGNAL ;
    PORT
      LAYER M4 ;
        RECT  17.088 5.472 17.28 5.496 ;
    END
  END o[31]
  PIN o[320]
    DIRECTION OUTPUT ;
    USE SIGNAL ;
    PORT
      LAYER M4 ;
        RECT  17.088 35.904 17.28 35.928 ;
    END
  END o[320]
  PIN o[321]
    DIRECTION OUTPUT ;
    USE SIGNAL ;
    PORT
      LAYER M4 ;
        RECT  17.088 36 17.28 36.024 ;
    END
  END o[321]
  PIN o[322]
    DIRECTION OUTPUT ;
    USE SIGNAL ;
    PORT
      LAYER M4 ;
        RECT  17.088 36.096 17.28 36.12 ;
    END
  END o[322]
  PIN o[323]
    DIRECTION OUTPUT ;
    USE SIGNAL ;
    PORT
      LAYER M4 ;
        RECT  17.088 36.24 17.28 36.264 ;
    END
  END o[323]
  PIN o[324]
    DIRECTION OUTPUT ;
    USE SIGNAL ;
    PORT
      LAYER M4 ;
        RECT  17.088 36.336 17.28 36.36 ;
    END
  END o[324]
  PIN o[325]
    DIRECTION OUTPUT ;
    USE SIGNAL ;
    PORT
      LAYER M4 ;
        RECT  17.088 36.432 17.28 36.456 ;
    END
  END o[325]
  PIN o[326]
    DIRECTION OUTPUT ;
    USE SIGNAL ;
    PORT
      LAYER M4 ;
        RECT  17.088 36.528 17.28 36.552 ;
    END
  END o[326]
  PIN o[327]
    DIRECTION OUTPUT ;
    USE SIGNAL ;
    PORT
      LAYER M4 ;
        RECT  17.088 36.624 17.28 36.648 ;
    END
  END o[327]
  PIN o[328]
    DIRECTION OUTPUT ;
    USE SIGNAL ;
    PORT
      LAYER M4 ;
        RECT  17.088 36.768 17.28 36.792 ;
    END
  END o[328]
  PIN o[329]
    DIRECTION OUTPUT ;
    USE SIGNAL ;
    PORT
      LAYER M4 ;
        RECT  17.088 36.864 17.28 36.888 ;
    END
  END o[329]
  PIN o[32]
    DIRECTION OUTPUT ;
    USE SIGNAL ;
    PORT
      LAYER M4 ;
        RECT  17.088 5.616 17.28 5.64 ;
    END
  END o[32]
  PIN o[330]
    DIRECTION OUTPUT ;
    USE SIGNAL ;
    PORT
      LAYER M4 ;
        RECT  17.088 36.96 17.28 36.984 ;
    END
  END o[330]
  PIN o[331]
    DIRECTION OUTPUT ;
    USE SIGNAL ;
    PORT
      LAYER M4 ;
        RECT  17.088 37.056 17.28 37.08 ;
    END
  END o[331]
  PIN o[332]
    DIRECTION OUTPUT ;
    USE SIGNAL ;
    PORT
      LAYER M4 ;
        RECT  17.088 37.152 17.28 37.176 ;
    END
  END o[332]
  PIN o[333]
    DIRECTION OUTPUT ;
    USE SIGNAL ;
    PORT
      LAYER M4 ;
        RECT  17.088 37.296 17.28 37.32 ;
    END
  END o[333]
  PIN o[334]
    DIRECTION OUTPUT ;
    USE SIGNAL ;
    PORT
      LAYER M4 ;
        RECT  17.088 37.392 17.28 37.416 ;
    END
  END o[334]
  PIN o[335]
    DIRECTION OUTPUT ;
    USE SIGNAL ;
    PORT
      LAYER M4 ;
        RECT  17.088 37.488 17.28 37.512 ;
    END
  END o[335]
  PIN o[336]
    DIRECTION OUTPUT ;
    USE SIGNAL ;
    PORT
      LAYER M4 ;
        RECT  17.088 37.584 17.28 37.608 ;
    END
  END o[336]
  PIN o[337]
    DIRECTION OUTPUT ;
    USE SIGNAL ;
    PORT
      LAYER M4 ;
        RECT  17.088 37.68 17.28 37.704 ;
    END
  END o[337]
  PIN o[338]
    DIRECTION OUTPUT ;
    USE SIGNAL ;
    PORT
      LAYER M4 ;
        RECT  17.088 37.824 17.28 37.848 ;
    END
  END o[338]
  PIN o[339]
    DIRECTION OUTPUT ;
    USE SIGNAL ;
    PORT
      LAYER M4 ;
        RECT  17.088 37.92 17.28 37.944 ;
    END
  END o[339]
  PIN o[33]
    DIRECTION OUTPUT ;
    USE SIGNAL ;
    PORT
      LAYER M4 ;
        RECT  17.088 5.712 17.28 5.736 ;
    END
  END o[33]
  PIN o[340]
    DIRECTION OUTPUT ;
    USE SIGNAL ;
    PORT
      LAYER M4 ;
        RECT  17.088 38.016 17.28 38.04 ;
    END
  END o[340]
  PIN o[341]
    DIRECTION OUTPUT ;
    USE SIGNAL ;
    PORT
      LAYER M4 ;
        RECT  17.088 38.112 17.28 38.136 ;
    END
  END o[341]
  PIN o[342]
    DIRECTION OUTPUT ;
    USE SIGNAL ;
    PORT
      LAYER M4 ;
        RECT  17.088 38.208 17.28 38.232 ;
    END
  END o[342]
  PIN o[343]
    DIRECTION OUTPUT ;
    USE SIGNAL ;
    PORT
      LAYER M4 ;
        RECT  17.088 38.352 17.28 38.376 ;
    END
  END o[343]
  PIN o[344]
    DIRECTION OUTPUT ;
    USE SIGNAL ;
    PORT
      LAYER M4 ;
        RECT  17.088 38.448 17.28 38.472 ;
    END
  END o[344]
  PIN o[345]
    DIRECTION OUTPUT ;
    USE SIGNAL ;
    PORT
      LAYER M4 ;
        RECT  17.088 38.544 17.28 38.568 ;
    END
  END o[345]
  PIN o[346]
    DIRECTION OUTPUT ;
    USE SIGNAL ;
    PORT
      LAYER M4 ;
        RECT  17.088 38.64 17.28 38.664 ;
    END
  END o[346]
  PIN o[347]
    DIRECTION OUTPUT ;
    USE SIGNAL ;
    PORT
      LAYER M4 ;
        RECT  17.088 38.736 17.28 38.76 ;
    END
  END o[347]
  PIN o[348]
    DIRECTION OUTPUT ;
    USE SIGNAL ;
    PORT
      LAYER M4 ;
        RECT  17.088 38.88 17.28 38.904 ;
    END
  END o[348]
  PIN o[349]
    DIRECTION OUTPUT ;
    USE SIGNAL ;
    PORT
      LAYER M4 ;
        RECT  17.088 38.976 17.28 39 ;
    END
  END o[349]
  PIN o[34]
    DIRECTION OUTPUT ;
    USE SIGNAL ;
    PORT
      LAYER M4 ;
        RECT  17.088 5.808 17.28 5.832 ;
    END
  END o[34]
  PIN o[350]
    DIRECTION OUTPUT ;
    USE SIGNAL ;
    PORT
      LAYER M4 ;
        RECT  17.088 39.072 17.28 39.096 ;
    END
  END o[350]
  PIN o[351]
    DIRECTION OUTPUT ;
    USE SIGNAL ;
    PORT
      LAYER M4 ;
        RECT  17.088 39.168 17.28 39.192 ;
    END
  END o[351]
  PIN o[352]
    DIRECTION OUTPUT ;
    USE SIGNAL ;
    PORT
      LAYER M4 ;
        RECT  17.088 39.264 17.28 39.288 ;
    END
  END o[352]
  PIN o[353]
    DIRECTION OUTPUT ;
    USE SIGNAL ;
    PORT
      LAYER M4 ;
        RECT  17.088 39.36 17.28 39.384 ;
    END
  END o[353]
  PIN o[354]
    DIRECTION OUTPUT ;
    USE SIGNAL ;
    PORT
      LAYER M4 ;
        RECT  17.088 39.504 17.28 39.528 ;
    END
  END o[354]
  PIN o[355]
    DIRECTION OUTPUT ;
    USE SIGNAL ;
    PORT
      LAYER M4 ;
        RECT  17.088 39.6 17.28 39.624 ;
    END
  END o[355]
  PIN o[356]
    DIRECTION OUTPUT ;
    USE SIGNAL ;
    PORT
      LAYER M4 ;
        RECT  17.088 39.696 17.28 39.72 ;
    END
  END o[356]
  PIN o[357]
    DIRECTION OUTPUT ;
    USE SIGNAL ;
    PORT
      LAYER M4 ;
        RECT  17.088 39.792 17.28 39.816 ;
    END
  END o[357]
  PIN o[358]
    DIRECTION OUTPUT ;
    USE SIGNAL ;
    PORT
      LAYER M4 ;
        RECT  17.088 39.888 17.28 39.912 ;
    END
  END o[358]
  PIN o[359]
    DIRECTION OUTPUT ;
    USE SIGNAL ;
    PORT
      LAYER M4 ;
        RECT  17.088 40.032 17.28 40.056 ;
    END
  END o[359]
  PIN o[35]
    DIRECTION OUTPUT ;
    USE SIGNAL ;
    PORT
      LAYER M4 ;
        RECT  17.088 5.904 17.28 5.928 ;
    END
  END o[35]
  PIN o[360]
    DIRECTION OUTPUT ;
    USE SIGNAL ;
    PORT
      LAYER M4 ;
        RECT  17.088 40.128 17.28 40.152 ;
    END
  END o[360]
  PIN o[361]
    DIRECTION OUTPUT ;
    USE SIGNAL ;
    PORT
      LAYER M4 ;
        RECT  17.088 40.224 17.28 40.248 ;
    END
  END o[361]
  PIN o[362]
    DIRECTION OUTPUT ;
    USE SIGNAL ;
    PORT
      LAYER M4 ;
        RECT  17.088 40.32 17.28 40.344 ;
    END
  END o[362]
  PIN o[363]
    DIRECTION OUTPUT ;
    USE SIGNAL ;
    PORT
      LAYER M4 ;
        RECT  17.088 40.416 17.28 40.44 ;
    END
  END o[363]
  PIN o[364]
    DIRECTION OUTPUT ;
    USE SIGNAL ;
    PORT
      LAYER M4 ;
        RECT  17.088 40.56 17.28 40.584 ;
    END
  END o[364]
  PIN o[365]
    DIRECTION OUTPUT ;
    USE SIGNAL ;
    PORT
      LAYER M4 ;
        RECT  17.088 40.656 17.28 40.68 ;
    END
  END o[365]
  PIN o[366]
    DIRECTION OUTPUT ;
    USE SIGNAL ;
    PORT
      LAYER M4 ;
        RECT  17.088 40.752 17.28 40.776 ;
    END
  END o[366]
  PIN o[367]
    DIRECTION OUTPUT ;
    USE SIGNAL ;
    PORT
      LAYER M4 ;
        RECT  17.088 40.848 17.28 40.872 ;
    END
  END o[367]
  PIN o[368]
    DIRECTION OUTPUT ;
    USE SIGNAL ;
    PORT
      LAYER M4 ;
        RECT  17.088 40.944 17.28 40.968 ;
    END
  END o[368]
  PIN o[369]
    DIRECTION OUTPUT ;
    USE SIGNAL ;
    PORT
      LAYER M4 ;
        RECT  17.088 41.088 17.28 41.112 ;
    END
  END o[369]
  PIN o[36]
    DIRECTION OUTPUT ;
    USE SIGNAL ;
    PORT
      LAYER M4 ;
        RECT  17.088 6 17.28 6.024 ;
    END
  END o[36]
  PIN o[370]
    DIRECTION OUTPUT ;
    USE SIGNAL ;
    PORT
      LAYER M4 ;
        RECT  17.088 41.184 17.28 41.208 ;
    END
  END o[370]
  PIN o[371]
    DIRECTION OUTPUT ;
    USE SIGNAL ;
    PORT
      LAYER M4 ;
        RECT  17.088 41.28 17.28 41.304 ;
    END
  END o[371]
  PIN o[372]
    DIRECTION OUTPUT ;
    USE SIGNAL ;
    PORT
      LAYER M4 ;
        RECT  17.088 41.376 17.28 41.4 ;
    END
  END o[372]
  PIN o[373]
    DIRECTION OUTPUT ;
    USE SIGNAL ;
    PORT
      LAYER M4 ;
        RECT  17.088 41.472 17.28 41.496 ;
    END
  END o[373]
  PIN o[374]
    DIRECTION OUTPUT ;
    USE SIGNAL ;
    PORT
      LAYER M4 ;
        RECT  17.088 41.616 17.28 41.64 ;
    END
  END o[374]
  PIN o[375]
    DIRECTION OUTPUT ;
    USE SIGNAL ;
    PORT
      LAYER M4 ;
        RECT  17.088 41.712 17.28 41.736 ;
    END
  END o[375]
  PIN o[376]
    DIRECTION OUTPUT ;
    USE SIGNAL ;
    PORT
      LAYER M4 ;
        RECT  17.088 41.808 17.28 41.832 ;
    END
  END o[376]
  PIN o[377]
    DIRECTION OUTPUT ;
    USE SIGNAL ;
    PORT
      LAYER M4 ;
        RECT  17.088 41.904 17.28 41.928 ;
    END
  END o[377]
  PIN o[378]
    DIRECTION OUTPUT ;
    USE SIGNAL ;
    PORT
      LAYER M4 ;
        RECT  17.088 42 17.28 42.024 ;
    END
  END o[378]
  PIN o[379]
    DIRECTION OUTPUT ;
    USE SIGNAL ;
    PORT
      LAYER M4 ;
        RECT  17.088 42.096 17.28 42.12 ;
    END
  END o[379]
  PIN o[37]
    DIRECTION OUTPUT ;
    USE SIGNAL ;
    PORT
      LAYER M4 ;
        RECT  17.088 6.096 17.28 6.12 ;
    END
  END o[37]
  PIN o[380]
    DIRECTION OUTPUT ;
    USE SIGNAL ;
    PORT
      LAYER M4 ;
        RECT  17.088 42.24 17.28 42.264 ;
    END
  END o[380]
  PIN o[381]
    DIRECTION OUTPUT ;
    USE SIGNAL ;
    PORT
      LAYER M4 ;
        RECT  17.088 42.336 17.28 42.36 ;
    END
  END o[381]
  PIN o[382]
    DIRECTION OUTPUT ;
    USE SIGNAL ;
    PORT
      LAYER M4 ;
        RECT  17.088 42.432 17.28 42.456 ;
    END
  END o[382]
  PIN o[383]
    DIRECTION OUTPUT ;
    USE SIGNAL ;
    PORT
      LAYER M4 ;
        RECT  17.088 42.528 17.28 42.552 ;
    END
  END o[383]
  PIN o[384]
    DIRECTION OUTPUT ;
    USE SIGNAL ;
    PORT
      LAYER M4 ;
        RECT  17.088 42.624 17.28 42.648 ;
    END
  END o[384]
  PIN o[385]
    DIRECTION OUTPUT ;
    USE SIGNAL ;
    PORT
      LAYER M4 ;
        RECT  17.088 42.768 17.28 42.792 ;
    END
  END o[385]
  PIN o[386]
    DIRECTION OUTPUT ;
    USE SIGNAL ;
    PORT
      LAYER M4 ;
        RECT  17.088 42.864 17.28 42.888 ;
    END
  END o[386]
  PIN o[387]
    DIRECTION OUTPUT ;
    USE SIGNAL ;
    PORT
      LAYER M4 ;
        RECT  17.088 42.96 17.28 42.984 ;
    END
  END o[387]
  PIN o[388]
    DIRECTION OUTPUT ;
    USE SIGNAL ;
    PORT
      LAYER M4 ;
        RECT  17.088 43.056 17.28 43.08 ;
    END
  END o[388]
  PIN o[389]
    DIRECTION OUTPUT ;
    USE SIGNAL ;
    PORT
      LAYER M4 ;
        RECT  17.088 43.152 17.28 43.176 ;
    END
  END o[389]
  PIN o[38]
    DIRECTION OUTPUT ;
    USE SIGNAL ;
    PORT
      LAYER M4 ;
        RECT  17.088 6.24 17.28 6.264 ;
    END
  END o[38]
  PIN o[390]
    DIRECTION OUTPUT ;
    USE SIGNAL ;
    PORT
      LAYER M4 ;
        RECT  17.088 43.296 17.28 43.32 ;
    END
  END o[390]
  PIN o[391]
    DIRECTION OUTPUT ;
    USE SIGNAL ;
    PORT
      LAYER M4 ;
        RECT  17.088 43.392 17.28 43.416 ;
    END
  END o[391]
  PIN o[392]
    DIRECTION OUTPUT ;
    USE SIGNAL ;
    PORT
      LAYER M4 ;
        RECT  17.088 43.488 17.28 43.512 ;
    END
  END o[392]
  PIN o[393]
    DIRECTION OUTPUT ;
    USE SIGNAL ;
    PORT
      LAYER M4 ;
        RECT  17.088 43.584 17.28 43.608 ;
    END
  END o[393]
  PIN o[394]
    DIRECTION OUTPUT ;
    USE SIGNAL ;
    PORT
      LAYER M4 ;
        RECT  17.088 43.68 17.28 43.704 ;
    END
  END o[394]
  PIN o[395]
    DIRECTION OUTPUT ;
    USE SIGNAL ;
    PORT
      LAYER M4 ;
        RECT  17.088 43.824 17.28 43.848 ;
    END
  END o[395]
  PIN o[396]
    DIRECTION OUTPUT ;
    USE SIGNAL ;
    PORT
      LAYER M4 ;
        RECT  17.088 43.92 17.28 43.944 ;
    END
  END o[396]
  PIN o[397]
    DIRECTION OUTPUT ;
    USE SIGNAL ;
    PORT
      LAYER M4 ;
        RECT  17.088 44.016 17.28 44.04 ;
    END
  END o[397]
  PIN o[398]
    DIRECTION OUTPUT ;
    USE SIGNAL ;
    PORT
      LAYER M4 ;
        RECT  17.088 44.112 17.28 44.136 ;
    END
  END o[398]
  PIN o[399]
    DIRECTION OUTPUT ;
    USE SIGNAL ;
    PORT
      LAYER M4 ;
        RECT  17.088 44.208 17.28 44.232 ;
    END
  END o[399]
  PIN o[39]
    DIRECTION OUTPUT ;
    USE SIGNAL ;
    PORT
      LAYER M4 ;
        RECT  17.088 6.336 17.28 6.36 ;
    END
  END o[39]
  PIN o[3]
    DIRECTION OUTPUT ;
    USE SIGNAL ;
    PORT
      LAYER M4 ;
        RECT  17.088 2.544 17.28 2.568 ;
    END
  END o[3]
  PIN o[400]
    DIRECTION OUTPUT ;
    USE SIGNAL ;
    PORT
      LAYER M4 ;
        RECT  17.088 44.352 17.28 44.376 ;
    END
  END o[400]
  PIN o[401]
    DIRECTION OUTPUT ;
    USE SIGNAL ;
    PORT
      LAYER M4 ;
        RECT  17.088 44.448 17.28 44.472 ;
    END
  END o[401]
  PIN o[402]
    DIRECTION OUTPUT ;
    USE SIGNAL ;
    PORT
      LAYER M4 ;
        RECT  17.088 44.544 17.28 44.568 ;
    END
  END o[402]
  PIN o[403]
    DIRECTION OUTPUT ;
    USE SIGNAL ;
    PORT
      LAYER M4 ;
        RECT  17.088 44.64 17.28 44.664 ;
    END
  END o[403]
  PIN o[404]
    DIRECTION OUTPUT ;
    USE SIGNAL ;
    PORT
      LAYER M4 ;
        RECT  17.088 44.736 17.28 44.76 ;
    END
  END o[404]
  PIN o[405]
    DIRECTION OUTPUT ;
    USE SIGNAL ;
    PORT
      LAYER M4 ;
        RECT  17.088 44.88 17.28 44.904 ;
    END
  END o[405]
  PIN o[406]
    DIRECTION OUTPUT ;
    USE SIGNAL ;
    PORT
      LAYER M4 ;
        RECT  17.088 44.976 17.28 45 ;
    END
  END o[406]
  PIN o[407]
    DIRECTION OUTPUT ;
    USE SIGNAL ;
    PORT
      LAYER M4 ;
        RECT  17.088 45.072 17.28 45.096 ;
    END
  END o[407]
  PIN o[408]
    DIRECTION OUTPUT ;
    USE SIGNAL ;
    PORT
      LAYER M4 ;
        RECT  17.088 45.168 17.28 45.192 ;
    END
  END o[408]
  PIN o[409]
    DIRECTION OUTPUT ;
    USE SIGNAL ;
    PORT
      LAYER M4 ;
        RECT  17.088 45.264 17.28 45.288 ;
    END
  END o[409]
  PIN o[40]
    DIRECTION OUTPUT ;
    USE SIGNAL ;
    PORT
      LAYER M4 ;
        RECT  17.088 6.432 17.28 6.456 ;
    END
  END o[40]
  PIN o[410]
    DIRECTION OUTPUT ;
    USE SIGNAL ;
    PORT
      LAYER M4 ;
        RECT  17.088 45.36 17.28 45.384 ;
    END
  END o[410]
  PIN o[411]
    DIRECTION OUTPUT ;
    USE SIGNAL ;
    PORT
      LAYER M4 ;
        RECT  17.088 45.504 17.28 45.528 ;
    END
  END o[411]
  PIN o[412]
    DIRECTION OUTPUT ;
    USE SIGNAL ;
    PORT
      LAYER M4 ;
        RECT  17.088 45.6 17.28 45.624 ;
    END
  END o[412]
  PIN o[413]
    DIRECTION OUTPUT ;
    USE SIGNAL ;
    PORT
      LAYER M4 ;
        RECT  17.088 45.696 17.28 45.72 ;
    END
  END o[413]
  PIN o[414]
    DIRECTION OUTPUT ;
    USE SIGNAL ;
    PORT
      LAYER M4 ;
        RECT  17.088 45.792 17.28 45.816 ;
    END
  END o[414]
  PIN o[415]
    DIRECTION OUTPUT ;
    USE SIGNAL ;
    PORT
      LAYER M4 ;
        RECT  17.088 45.888 17.28 45.912 ;
    END
  END o[415]
  PIN o[416]
    DIRECTION OUTPUT ;
    USE SIGNAL ;
    PORT
      LAYER M4 ;
        RECT  17.088 46.032 17.28 46.056 ;
    END
  END o[416]
  PIN o[417]
    DIRECTION OUTPUT ;
    USE SIGNAL ;
    PORT
      LAYER M4 ;
        RECT  17.088 46.128 17.28 46.152 ;
    END
  END o[417]
  PIN o[418]
    DIRECTION OUTPUT ;
    USE SIGNAL ;
    PORT
      LAYER M4 ;
        RECT  17.088 46.224 17.28 46.248 ;
    END
  END o[418]
  PIN o[419]
    DIRECTION OUTPUT ;
    USE SIGNAL ;
    PORT
      LAYER M4 ;
        RECT  17.088 46.32 17.28 46.344 ;
    END
  END o[419]
  PIN o[41]
    DIRECTION OUTPUT ;
    USE SIGNAL ;
    PORT
      LAYER M4 ;
        RECT  17.088 6.528 17.28 6.552 ;
    END
  END o[41]
  PIN o[420]
    DIRECTION OUTPUT ;
    USE SIGNAL ;
    PORT
      LAYER M4 ;
        RECT  17.088 46.416 17.28 46.44 ;
    END
  END o[420]
  PIN o[421]
    DIRECTION OUTPUT ;
    USE SIGNAL ;
    PORT
      LAYER M4 ;
        RECT  17.088 46.56 17.28 46.584 ;
    END
  END o[421]
  PIN o[422]
    DIRECTION OUTPUT ;
    USE SIGNAL ;
    PORT
      LAYER M4 ;
        RECT  17.088 46.656 17.28 46.68 ;
    END
  END o[422]
  PIN o[423]
    DIRECTION OUTPUT ;
    USE SIGNAL ;
    PORT
      LAYER M4 ;
        RECT  17.088 46.752 17.28 46.776 ;
    END
  END o[423]
  PIN o[424]
    DIRECTION OUTPUT ;
    USE SIGNAL ;
    PORT
      LAYER M4 ;
        RECT  17.088 46.848 17.28 46.872 ;
    END
  END o[424]
  PIN o[425]
    DIRECTION OUTPUT ;
    USE SIGNAL ;
    PORT
      LAYER M4 ;
        RECT  17.088 46.944 17.28 46.968 ;
    END
  END o[425]
  PIN o[426]
    DIRECTION OUTPUT ;
    USE SIGNAL ;
    PORT
      LAYER M4 ;
        RECT  17.088 47.088 17.28 47.112 ;
    END
  END o[426]
  PIN o[427]
    DIRECTION OUTPUT ;
    USE SIGNAL ;
    PORT
      LAYER M4 ;
        RECT  17.088 47.184 17.28 47.208 ;
    END
  END o[427]
  PIN o[428]
    DIRECTION OUTPUT ;
    USE SIGNAL ;
    PORT
      LAYER M4 ;
        RECT  17.088 47.28 17.28 47.304 ;
    END
  END o[428]
  PIN o[429]
    DIRECTION OUTPUT ;
    USE SIGNAL ;
    PORT
      LAYER M4 ;
        RECT  17.088 47.376 17.28 47.4 ;
    END
  END o[429]
  PIN o[42]
    DIRECTION OUTPUT ;
    USE SIGNAL ;
    PORT
      LAYER M4 ;
        RECT  17.088 6.624 17.28 6.648 ;
    END
  END o[42]
  PIN o[430]
    DIRECTION OUTPUT ;
    USE SIGNAL ;
    PORT
      LAYER M4 ;
        RECT  17.088 47.472 17.28 47.496 ;
    END
  END o[430]
  PIN o[431]
    DIRECTION OUTPUT ;
    USE SIGNAL ;
    PORT
      LAYER M4 ;
        RECT  17.088 47.616 17.28 47.64 ;
    END
  END o[431]
  PIN o[432]
    DIRECTION OUTPUT ;
    USE SIGNAL ;
    PORT
      LAYER M4 ;
        RECT  17.088 47.712 17.28 47.736 ;
    END
  END o[432]
  PIN o[433]
    DIRECTION OUTPUT ;
    USE SIGNAL ;
    PORT
      LAYER M4 ;
        RECT  17.088 47.808 17.28 47.832 ;
    END
  END o[433]
  PIN o[434]
    DIRECTION OUTPUT ;
    USE SIGNAL ;
    PORT
      LAYER M4 ;
        RECT  17.088 47.904 17.28 47.928 ;
    END
  END o[434]
  PIN o[435]
    DIRECTION OUTPUT ;
    USE SIGNAL ;
    PORT
      LAYER M4 ;
        RECT  17.088 48 17.28 48.024 ;
    END
  END o[435]
  PIN o[436]
    DIRECTION OUTPUT ;
    USE SIGNAL ;
    PORT
      LAYER M4 ;
        RECT  17.088 48.096 17.28 48.12 ;
    END
  END o[436]
  PIN o[437]
    DIRECTION OUTPUT ;
    USE SIGNAL ;
    PORT
      LAYER M4 ;
        RECT  17.088 48.24 17.28 48.264 ;
    END
  END o[437]
  PIN o[438]
    DIRECTION OUTPUT ;
    USE SIGNAL ;
    PORT
      LAYER M4 ;
        RECT  17.088 48.336 17.28 48.36 ;
    END
  END o[438]
  PIN o[439]
    DIRECTION OUTPUT ;
    USE SIGNAL ;
    PORT
      LAYER M4 ;
        RECT  17.088 48.432 17.28 48.456 ;
    END
  END o[439]
  PIN o[43]
    DIRECTION OUTPUT ;
    USE SIGNAL ;
    PORT
      LAYER M4 ;
        RECT  17.088 6.768 17.28 6.792 ;
    END
  END o[43]
  PIN o[440]
    DIRECTION OUTPUT ;
    USE SIGNAL ;
    PORT
      LAYER M4 ;
        RECT  17.088 48.528 17.28 48.552 ;
    END
  END o[440]
  PIN o[441]
    DIRECTION OUTPUT ;
    USE SIGNAL ;
    PORT
      LAYER M4 ;
        RECT  17.088 48.624 17.28 48.648 ;
    END
  END o[441]
  PIN o[442]
    DIRECTION OUTPUT ;
    USE SIGNAL ;
    PORT
      LAYER M4 ;
        RECT  17.088 48.768 17.28 48.792 ;
    END
  END o[442]
  PIN o[443]
    DIRECTION OUTPUT ;
    USE SIGNAL ;
    PORT
      LAYER M4 ;
        RECT  17.088 48.864 17.28 48.888 ;
    END
  END o[443]
  PIN o[444]
    DIRECTION OUTPUT ;
    USE SIGNAL ;
    PORT
      LAYER M4 ;
        RECT  17.088 48.96 17.28 48.984 ;
    END
  END o[444]
  PIN o[445]
    DIRECTION OUTPUT ;
    USE SIGNAL ;
    PORT
      LAYER M4 ;
        RECT  17.088 49.056 17.28 49.08 ;
    END
  END o[445]
  PIN o[446]
    DIRECTION OUTPUT ;
    USE SIGNAL ;
    PORT
      LAYER M4 ;
        RECT  17.088 49.152 17.28 49.176 ;
    END
  END o[446]
  PIN o[447]
    DIRECTION OUTPUT ;
    USE SIGNAL ;
    PORT
      LAYER M4 ;
        RECT  17.088 49.296 17.28 49.32 ;
    END
  END o[447]
  PIN o[448]
    DIRECTION OUTPUT ;
    USE SIGNAL ;
    PORT
      LAYER M4 ;
        RECT  17.088 49.392 17.28 49.416 ;
    END
  END o[448]
  PIN o[449]
    DIRECTION OUTPUT ;
    USE SIGNAL ;
    PORT
      LAYER M4 ;
        RECT  17.088 49.488 17.28 49.512 ;
    END
  END o[449]
  PIN o[44]
    DIRECTION OUTPUT ;
    USE SIGNAL ;
    PORT
      LAYER M4 ;
        RECT  17.088 6.864 17.28 6.888 ;
    END
  END o[44]
  PIN o[450]
    DIRECTION OUTPUT ;
    USE SIGNAL ;
    PORT
      LAYER M4 ;
        RECT  17.088 49.584 17.28 49.608 ;
    END
  END o[450]
  PIN o[451]
    DIRECTION OUTPUT ;
    USE SIGNAL ;
    PORT
      LAYER M4 ;
        RECT  17.088 49.68 17.28 49.704 ;
    END
  END o[451]
  PIN o[452]
    DIRECTION OUTPUT ;
    USE SIGNAL ;
    PORT
      LAYER M4 ;
        RECT  17.088 49.824 17.28 49.848 ;
    END
  END o[452]
  PIN o[453]
    DIRECTION OUTPUT ;
    USE SIGNAL ;
    PORT
      LAYER M4 ;
        RECT  17.088 49.92 17.28 49.944 ;
    END
  END o[453]
  PIN o[454]
    DIRECTION OUTPUT ;
    USE SIGNAL ;
    PORT
      LAYER M4 ;
        RECT  17.088 50.016 17.28 50.04 ;
    END
  END o[454]
  PIN o[455]
    DIRECTION OUTPUT ;
    USE SIGNAL ;
    PORT
      LAYER M4 ;
        RECT  17.088 50.112 17.28 50.136 ;
    END
  END o[455]
  PIN o[456]
    DIRECTION OUTPUT ;
    USE SIGNAL ;
    PORT
      LAYER M4 ;
        RECT  17.088 50.208 17.28 50.232 ;
    END
  END o[456]
  PIN o[457]
    DIRECTION OUTPUT ;
    USE SIGNAL ;
    PORT
      LAYER M4 ;
        RECT  17.088 50.352 17.28 50.376 ;
    END
  END o[457]
  PIN o[458]
    DIRECTION OUTPUT ;
    USE SIGNAL ;
    PORT
      LAYER M4 ;
        RECT  17.088 50.448 17.28 50.472 ;
    END
  END o[458]
  PIN o[459]
    DIRECTION OUTPUT ;
    USE SIGNAL ;
    PORT
      LAYER M4 ;
        RECT  17.088 50.544 17.28 50.568 ;
    END
  END o[459]
  PIN o[45]
    DIRECTION OUTPUT ;
    USE SIGNAL ;
    PORT
      LAYER M4 ;
        RECT  17.088 6.96 17.28 6.984 ;
    END
  END o[45]
  PIN o[460]
    DIRECTION OUTPUT ;
    USE SIGNAL ;
    PORT
      LAYER M4 ;
        RECT  17.088 50.64 17.28 50.664 ;
    END
  END o[460]
  PIN o[461]
    DIRECTION OUTPUT ;
    USE SIGNAL ;
    PORT
      LAYER M4 ;
        RECT  17.088 50.736 17.28 50.76 ;
    END
  END o[461]
  PIN o[462]
    DIRECTION OUTPUT ;
    USE SIGNAL ;
    PORT
      LAYER M4 ;
        RECT  17.088 50.88 17.28 50.904 ;
    END
  END o[462]
  PIN o[463]
    DIRECTION OUTPUT ;
    USE SIGNAL ;
    PORT
      LAYER M4 ;
        RECT  17.088 50.976 17.28 51 ;
    END
  END o[463]
  PIN o[464]
    DIRECTION OUTPUT ;
    USE SIGNAL ;
    PORT
      LAYER M4 ;
        RECT  17.088 51.072 17.28 51.096 ;
    END
  END o[464]
  PIN o[465]
    DIRECTION OUTPUT ;
    USE SIGNAL ;
    PORT
      LAYER M4 ;
        RECT  17.088 51.168 17.28 51.192 ;
    END
  END o[465]
  PIN o[466]
    DIRECTION OUTPUT ;
    USE SIGNAL ;
    PORT
      LAYER M4 ;
        RECT  17.088 51.264 17.28 51.288 ;
    END
  END o[466]
  PIN o[467]
    DIRECTION OUTPUT ;
    USE SIGNAL ;
    PORT
      LAYER M4 ;
        RECT  17.088 51.36 17.28 51.384 ;
    END
  END o[467]
  PIN o[468]
    DIRECTION OUTPUT ;
    USE SIGNAL ;
    PORT
      LAYER M4 ;
        RECT  17.088 51.504 17.28 51.528 ;
    END
  END o[468]
  PIN o[469]
    DIRECTION OUTPUT ;
    USE SIGNAL ;
    PORT
      LAYER M4 ;
        RECT  17.088 51.6 17.28 51.624 ;
    END
  END o[469]
  PIN o[46]
    DIRECTION OUTPUT ;
    USE SIGNAL ;
    PORT
      LAYER M4 ;
        RECT  17.088 7.056 17.28 7.08 ;
    END
  END o[46]
  PIN o[470]
    DIRECTION OUTPUT ;
    USE SIGNAL ;
    PORT
      LAYER M4 ;
        RECT  17.088 51.696 17.28 51.72 ;
    END
  END o[470]
  PIN o[471]
    DIRECTION OUTPUT ;
    USE SIGNAL ;
    PORT
      LAYER M4 ;
        RECT  17.088 51.792 17.28 51.816 ;
    END
  END o[471]
  PIN o[472]
    DIRECTION OUTPUT ;
    USE SIGNAL ;
    PORT
      LAYER M4 ;
        RECT  17.088 51.888 17.28 51.912 ;
    END
  END o[472]
  PIN o[473]
    DIRECTION OUTPUT ;
    USE SIGNAL ;
    PORT
      LAYER M4 ;
        RECT  17.088 52.032 17.28 52.056 ;
    END
  END o[473]
  PIN o[474]
    DIRECTION OUTPUT ;
    USE SIGNAL ;
    PORT
      LAYER M4 ;
        RECT  17.088 52.128 17.28 52.152 ;
    END
  END o[474]
  PIN o[475]
    DIRECTION OUTPUT ;
    USE SIGNAL ;
    PORT
      LAYER M4 ;
        RECT  17.088 52.224 17.28 52.248 ;
    END
  END o[475]
  PIN o[476]
    DIRECTION OUTPUT ;
    USE SIGNAL ;
    PORT
      LAYER M4 ;
        RECT  17.088 52.32 17.28 52.344 ;
    END
  END o[476]
  PIN o[477]
    DIRECTION OUTPUT ;
    USE SIGNAL ;
    PORT
      LAYER M4 ;
        RECT  17.088 52.416 17.28 52.44 ;
    END
  END o[477]
  PIN o[478]
    DIRECTION OUTPUT ;
    USE SIGNAL ;
    PORT
      LAYER M4 ;
        RECT  17.088 52.56 17.28 52.584 ;
    END
  END o[478]
  PIN o[479]
    DIRECTION OUTPUT ;
    USE SIGNAL ;
    PORT
      LAYER M4 ;
        RECT  17.088 52.656 17.28 52.68 ;
    END
  END o[479]
  PIN o[47]
    DIRECTION OUTPUT ;
    USE SIGNAL ;
    PORT
      LAYER M4 ;
        RECT  17.088 7.152 17.28 7.176 ;
    END
  END o[47]
  PIN o[480]
    DIRECTION OUTPUT ;
    USE SIGNAL ;
    PORT
      LAYER M4 ;
        RECT  17.088 52.752 17.28 52.776 ;
    END
  END o[480]
  PIN o[481]
    DIRECTION OUTPUT ;
    USE SIGNAL ;
    PORT
      LAYER M4 ;
        RECT  17.088 52.848 17.28 52.872 ;
    END
  END o[481]
  PIN o[482]
    DIRECTION OUTPUT ;
    USE SIGNAL ;
    PORT
      LAYER M4 ;
        RECT  17.088 52.944 17.28 52.968 ;
    END
  END o[482]
  PIN o[483]
    DIRECTION OUTPUT ;
    USE SIGNAL ;
    PORT
      LAYER M4 ;
        RECT  17.088 53.088 17.28 53.112 ;
    END
  END o[483]
  PIN o[484]
    DIRECTION OUTPUT ;
    USE SIGNAL ;
    PORT
      LAYER M4 ;
        RECT  17.088 53.184 17.28 53.208 ;
    END
  END o[484]
  PIN o[485]
    DIRECTION OUTPUT ;
    USE SIGNAL ;
    PORT
      LAYER M4 ;
        RECT  17.088 53.28 17.28 53.304 ;
    END
  END o[485]
  PIN o[486]
    DIRECTION OUTPUT ;
    USE SIGNAL ;
    PORT
      LAYER M4 ;
        RECT  17.088 53.376 17.28 53.4 ;
    END
  END o[486]
  PIN o[487]
    DIRECTION OUTPUT ;
    USE SIGNAL ;
    PORT
      LAYER M4 ;
        RECT  17.088 53.472 17.28 53.496 ;
    END
  END o[487]
  PIN o[488]
    DIRECTION OUTPUT ;
    USE SIGNAL ;
    PORT
      LAYER M4 ;
        RECT  17.088 53.616 17.28 53.64 ;
    END
  END o[488]
  PIN o[489]
    DIRECTION OUTPUT ;
    USE SIGNAL ;
    PORT
      LAYER M4 ;
        RECT  17.088 53.712 17.28 53.736 ;
    END
  END o[489]
  PIN o[48]
    DIRECTION OUTPUT ;
    USE SIGNAL ;
    PORT
      LAYER M4 ;
        RECT  17.088 7.296 17.28 7.32 ;
    END
  END o[48]
  PIN o[490]
    DIRECTION OUTPUT ;
    USE SIGNAL ;
    PORT
      LAYER M4 ;
        RECT  17.088 53.808 17.28 53.832 ;
    END
  END o[490]
  PIN o[491]
    DIRECTION OUTPUT ;
    USE SIGNAL ;
    PORT
      LAYER M4 ;
        RECT  17.088 53.904 17.28 53.928 ;
    END
  END o[491]
  PIN o[492]
    DIRECTION OUTPUT ;
    USE SIGNAL ;
    PORT
      LAYER M4 ;
        RECT  17.088 54 17.28 54.024 ;
    END
  END o[492]
  PIN o[493]
    DIRECTION OUTPUT ;
    USE SIGNAL ;
    PORT
      LAYER M4 ;
        RECT  17.088 54.096 17.28 54.12 ;
    END
  END o[493]
  PIN o[494]
    DIRECTION OUTPUT ;
    USE SIGNAL ;
    PORT
      LAYER M4 ;
        RECT  17.088 54.24 17.28 54.264 ;
    END
  END o[494]
  PIN o[495]
    DIRECTION OUTPUT ;
    USE SIGNAL ;
    PORT
      LAYER M4 ;
        RECT  17.088 54.336 17.28 54.36 ;
    END
  END o[495]
  PIN o[496]
    DIRECTION OUTPUT ;
    USE SIGNAL ;
    PORT
      LAYER M4 ;
        RECT  17.088 54.432 17.28 54.456 ;
    END
  END o[496]
  PIN o[497]
    DIRECTION OUTPUT ;
    USE SIGNAL ;
    PORT
      LAYER M4 ;
        RECT  17.088 54.528 17.28 54.552 ;
    END
  END o[497]
  PIN o[498]
    DIRECTION OUTPUT ;
    USE SIGNAL ;
    PORT
      LAYER M4 ;
        RECT  17.088 54.624 17.28 54.648 ;
    END
  END o[498]
  PIN o[499]
    DIRECTION OUTPUT ;
    USE SIGNAL ;
    PORT
      LAYER M4 ;
        RECT  17.088 54.768 17.28 54.792 ;
    END
  END o[499]
  PIN o[49]
    DIRECTION OUTPUT ;
    USE SIGNAL ;
    PORT
      LAYER M4 ;
        RECT  17.088 7.392 17.28 7.416 ;
    END
  END o[49]
  PIN o[4]
    DIRECTION OUTPUT ;
    USE SIGNAL ;
    PORT
      LAYER M4 ;
        RECT  17.088 2.64 17.28 2.664 ;
    END
  END o[4]
  PIN o[500]
    DIRECTION OUTPUT ;
    USE SIGNAL ;
    PORT
      LAYER M4 ;
        RECT  17.088 54.864 17.28 54.888 ;
    END
  END o[500]
  PIN o[501]
    DIRECTION OUTPUT ;
    USE SIGNAL ;
    PORT
      LAYER M4 ;
        RECT  17.088 54.96 17.28 54.984 ;
    END
  END o[501]
  PIN o[502]
    DIRECTION OUTPUT ;
    USE SIGNAL ;
    PORT
      LAYER M4 ;
        RECT  17.088 55.056 17.28 55.08 ;
    END
  END o[502]
  PIN o[503]
    DIRECTION OUTPUT ;
    USE SIGNAL ;
    PORT
      LAYER M4 ;
        RECT  17.088 55.152 17.28 55.176 ;
    END
  END o[503]
  PIN o[504]
    DIRECTION OUTPUT ;
    USE SIGNAL ;
    PORT
      LAYER M4 ;
        RECT  17.088 55.296 17.28 55.32 ;
    END
  END o[504]
  PIN o[505]
    DIRECTION OUTPUT ;
    USE SIGNAL ;
    PORT
      LAYER M4 ;
        RECT  17.088 55.392 17.28 55.416 ;
    END
  END o[505]
  PIN o[506]
    DIRECTION OUTPUT ;
    USE SIGNAL ;
    PORT
      LAYER M4 ;
        RECT  17.088 55.488 17.28 55.512 ;
    END
  END o[506]
  PIN o[507]
    DIRECTION OUTPUT ;
    USE SIGNAL ;
    PORT
      LAYER M4 ;
        RECT  17.088 55.584 17.28 55.608 ;
    END
  END o[507]
  PIN o[508]
    DIRECTION OUTPUT ;
    USE SIGNAL ;
    PORT
      LAYER M4 ;
        RECT  17.088 55.68 17.28 55.704 ;
    END
  END o[508]
  PIN o[509]
    DIRECTION OUTPUT ;
    USE SIGNAL ;
    PORT
      LAYER M4 ;
        RECT  17.088 55.824 17.28 55.848 ;
    END
  END o[509]
  PIN o[50]
    DIRECTION OUTPUT ;
    USE SIGNAL ;
    PORT
      LAYER M4 ;
        RECT  17.088 7.488 17.28 7.512 ;
    END
  END o[50]
  PIN o[510]
    DIRECTION OUTPUT ;
    USE SIGNAL ;
    PORT
      LAYER M4 ;
        RECT  17.088 55.92 17.28 55.944 ;
    END
  END o[510]
  PIN o[511]
    DIRECTION OUTPUT ;
    USE SIGNAL ;
    PORT
      LAYER M4 ;
        RECT  17.088 56.016 17.28 56.04 ;
    END
  END o[511]
  PIN o[51]
    DIRECTION OUTPUT ;
    USE SIGNAL ;
    PORT
      LAYER M4 ;
        RECT  17.088 7.584 17.28 7.608 ;
    END
  END o[51]
  PIN o[52]
    DIRECTION OUTPUT ;
    USE SIGNAL ;
    PORT
      LAYER M4 ;
        RECT  17.088 7.68 17.28 7.704 ;
    END
  END o[52]
  PIN o[53]
    DIRECTION OUTPUT ;
    USE SIGNAL ;
    PORT
      LAYER M4 ;
        RECT  17.088 7.824 17.28 7.848 ;
    END
  END o[53]
  PIN o[54]
    DIRECTION OUTPUT ;
    USE SIGNAL ;
    PORT
      LAYER M4 ;
        RECT  17.088 7.92 17.28 7.944 ;
    END
  END o[54]
  PIN o[55]
    DIRECTION OUTPUT ;
    USE SIGNAL ;
    PORT
      LAYER M4 ;
        RECT  17.088 8.016 17.28 8.04 ;
    END
  END o[55]
  PIN o[56]
    DIRECTION OUTPUT ;
    USE SIGNAL ;
    PORT
      LAYER M4 ;
        RECT  17.088 8.112 17.28 8.136 ;
    END
  END o[56]
  PIN o[57]
    DIRECTION OUTPUT ;
    USE SIGNAL ;
    PORT
      LAYER M4 ;
        RECT  17.088 8.208 17.28 8.232 ;
    END
  END o[57]
  PIN o[58]
    DIRECTION OUTPUT ;
    USE SIGNAL ;
    PORT
      LAYER M4 ;
        RECT  17.088 8.352 17.28 8.376 ;
    END
  END o[58]
  PIN o[59]
    DIRECTION OUTPUT ;
    USE SIGNAL ;
    PORT
      LAYER M4 ;
        RECT  17.088 8.448 17.28 8.472 ;
    END
  END o[59]
  PIN o[5]
    DIRECTION OUTPUT ;
    USE SIGNAL ;
    PORT
      LAYER M4 ;
        RECT  17.088 2.736 17.28 2.76 ;
    END
  END o[5]
  PIN o[60]
    DIRECTION OUTPUT ;
    USE SIGNAL ;
    PORT
      LAYER M4 ;
        RECT  17.088 8.544 17.28 8.568 ;
    END
  END o[60]
  PIN o[61]
    DIRECTION OUTPUT ;
    USE SIGNAL ;
    PORT
      LAYER M4 ;
        RECT  17.088 8.64 17.28 8.664 ;
    END
  END o[61]
  PIN o[62]
    DIRECTION OUTPUT ;
    USE SIGNAL ;
    PORT
      LAYER M4 ;
        RECT  17.088 8.736 17.28 8.76 ;
    END
  END o[62]
  PIN o[63]
    DIRECTION OUTPUT ;
    USE SIGNAL ;
    PORT
      LAYER M4 ;
        RECT  17.088 8.88 17.28 8.904 ;
    END
  END o[63]
  PIN o[64]
    DIRECTION OUTPUT ;
    USE SIGNAL ;
    PORT
      LAYER M4 ;
        RECT  17.088 8.976 17.28 9 ;
    END
  END o[64]
  PIN o[65]
    DIRECTION OUTPUT ;
    USE SIGNAL ;
    PORT
      LAYER M4 ;
        RECT  17.088 9.072 17.28 9.096 ;
    END
  END o[65]
  PIN o[66]
    DIRECTION OUTPUT ;
    USE SIGNAL ;
    PORT
      LAYER M4 ;
        RECT  17.088 9.168 17.28 9.192 ;
    END
  END o[66]
  PIN o[67]
    DIRECTION OUTPUT ;
    USE SIGNAL ;
    PORT
      LAYER M4 ;
        RECT  17.088 9.264 17.28 9.288 ;
    END
  END o[67]
  PIN o[68]
    DIRECTION OUTPUT ;
    USE SIGNAL ;
    PORT
      LAYER M4 ;
        RECT  17.088 9.36 17.28 9.384 ;
    END
  END o[68]
  PIN o[69]
    DIRECTION OUTPUT ;
    USE SIGNAL ;
    PORT
      LAYER M4 ;
        RECT  17.088 9.504 17.28 9.528 ;
    END
  END o[69]
  PIN o[6]
    DIRECTION OUTPUT ;
    USE SIGNAL ;
    PORT
      LAYER M4 ;
        RECT  17.088 2.88 17.28 2.904 ;
    END
  END o[6]
  PIN o[70]
    DIRECTION OUTPUT ;
    USE SIGNAL ;
    PORT
      LAYER M4 ;
        RECT  17.088 9.6 17.28 9.624 ;
    END
  END o[70]
  PIN o[71]
    DIRECTION OUTPUT ;
    USE SIGNAL ;
    PORT
      LAYER M4 ;
        RECT  17.088 9.696 17.28 9.72 ;
    END
  END o[71]
  PIN o[72]
    DIRECTION OUTPUT ;
    USE SIGNAL ;
    PORT
      LAYER M4 ;
        RECT  17.088 9.792 17.28 9.816 ;
    END
  END o[72]
  PIN o[73]
    DIRECTION OUTPUT ;
    USE SIGNAL ;
    PORT
      LAYER M4 ;
        RECT  17.088 9.888 17.28 9.912 ;
    END
  END o[73]
  PIN o[74]
    DIRECTION OUTPUT ;
    USE SIGNAL ;
    PORT
      LAYER M4 ;
        RECT  17.088 10.032 17.28 10.056 ;
    END
  END o[74]
  PIN o[75]
    DIRECTION OUTPUT ;
    USE SIGNAL ;
    PORT
      LAYER M4 ;
        RECT  17.088 10.128 17.28 10.152 ;
    END
  END o[75]
  PIN o[76]
    DIRECTION OUTPUT ;
    USE SIGNAL ;
    PORT
      LAYER M4 ;
        RECT  17.088 10.224 17.28 10.248 ;
    END
  END o[76]
  PIN o[77]
    DIRECTION OUTPUT ;
    USE SIGNAL ;
    PORT
      LAYER M4 ;
        RECT  17.088 10.32 17.28 10.344 ;
    END
  END o[77]
  PIN o[78]
    DIRECTION OUTPUT ;
    USE SIGNAL ;
    PORT
      LAYER M4 ;
        RECT  17.088 10.416 17.28 10.44 ;
    END
  END o[78]
  PIN o[79]
    DIRECTION OUTPUT ;
    USE SIGNAL ;
    PORT
      LAYER M4 ;
        RECT  17.088 10.56 17.28 10.584 ;
    END
  END o[79]
  PIN o[7]
    DIRECTION OUTPUT ;
    USE SIGNAL ;
    PORT
      LAYER M4 ;
        RECT  17.088 2.976 17.28 3 ;
    END
  END o[7]
  PIN o[80]
    DIRECTION OUTPUT ;
    USE SIGNAL ;
    PORT
      LAYER M4 ;
        RECT  17.088 10.656 17.28 10.68 ;
    END
  END o[80]
  PIN o[81]
    DIRECTION OUTPUT ;
    USE SIGNAL ;
    PORT
      LAYER M4 ;
        RECT  17.088 10.752 17.28 10.776 ;
    END
  END o[81]
  PIN o[82]
    DIRECTION OUTPUT ;
    USE SIGNAL ;
    PORT
      LAYER M4 ;
        RECT  17.088 10.848 17.28 10.872 ;
    END
  END o[82]
  PIN o[83]
    DIRECTION OUTPUT ;
    USE SIGNAL ;
    PORT
      LAYER M4 ;
        RECT  17.088 10.944 17.28 10.968 ;
    END
  END o[83]
  PIN o[84]
    DIRECTION OUTPUT ;
    USE SIGNAL ;
    PORT
      LAYER M4 ;
        RECT  17.088 11.088 17.28 11.112 ;
    END
  END o[84]
  PIN o[85]
    DIRECTION OUTPUT ;
    USE SIGNAL ;
    PORT
      LAYER M4 ;
        RECT  17.088 11.184 17.28 11.208 ;
    END
  END o[85]
  PIN o[86]
    DIRECTION OUTPUT ;
    USE SIGNAL ;
    PORT
      LAYER M4 ;
        RECT  17.088 11.28 17.28 11.304 ;
    END
  END o[86]
  PIN o[87]
    DIRECTION OUTPUT ;
    USE SIGNAL ;
    PORT
      LAYER M4 ;
        RECT  17.088 11.376 17.28 11.4 ;
    END
  END o[87]
  PIN o[88]
    DIRECTION OUTPUT ;
    USE SIGNAL ;
    PORT
      LAYER M4 ;
        RECT  17.088 11.472 17.28 11.496 ;
    END
  END o[88]
  PIN o[89]
    DIRECTION OUTPUT ;
    USE SIGNAL ;
    PORT
      LAYER M4 ;
        RECT  17.088 11.616 17.28 11.64 ;
    END
  END o[89]
  PIN o[8]
    DIRECTION OUTPUT ;
    USE SIGNAL ;
    PORT
      LAYER M4 ;
        RECT  17.088 3.072 17.28 3.096 ;
    END
  END o[8]
  PIN o[90]
    DIRECTION OUTPUT ;
    USE SIGNAL ;
    PORT
      LAYER M4 ;
        RECT  17.088 11.712 17.28 11.736 ;
    END
  END o[90]
  PIN o[91]
    DIRECTION OUTPUT ;
    USE SIGNAL ;
    PORT
      LAYER M4 ;
        RECT  17.088 11.808 17.28 11.832 ;
    END
  END o[91]
  PIN o[92]
    DIRECTION OUTPUT ;
    USE SIGNAL ;
    PORT
      LAYER M4 ;
        RECT  17.088 11.904 17.28 11.928 ;
    END
  END o[92]
  PIN o[93]
    DIRECTION OUTPUT ;
    USE SIGNAL ;
    PORT
      LAYER M4 ;
        RECT  17.088 12 17.28 12.024 ;
    END
  END o[93]
  PIN o[94]
    DIRECTION OUTPUT ;
    USE SIGNAL ;
    PORT
      LAYER M4 ;
        RECT  17.088 12.096 17.28 12.12 ;
    END
  END o[94]
  PIN o[95]
    DIRECTION OUTPUT ;
    USE SIGNAL ;
    PORT
      LAYER M4 ;
        RECT  17.088 12.24 17.28 12.264 ;
    END
  END o[95]
  PIN o[96]
    DIRECTION OUTPUT ;
    USE SIGNAL ;
    PORT
      LAYER M4 ;
        RECT  17.088 12.336 17.28 12.36 ;
    END
  END o[96]
  PIN o[97]
    DIRECTION OUTPUT ;
    USE SIGNAL ;
    PORT
      LAYER M4 ;
        RECT  17.088 12.432 17.28 12.456 ;
    END
  END o[97]
  PIN o[98]
    DIRECTION OUTPUT ;
    USE SIGNAL ;
    PORT
      LAYER M4 ;
        RECT  17.088 12.528 17.28 12.552 ;
    END
  END o[98]
  PIN o[99]
    DIRECTION OUTPUT ;
    USE SIGNAL ;
    PORT
      LAYER M4 ;
        RECT  17.088 12.624 17.28 12.648 ;
    END
  END o[99]
  PIN o[9]
    DIRECTION OUTPUT ;
    USE SIGNAL ;
    PORT
      LAYER M4 ;
        RECT  17.088 3.168 17.28 3.192 ;
    END
  END o[9]
  PIN rs
    DIRECTION INPUT ;
    USE SIGNAL ;
    PORT
      LAYER M5 ;
        RECT  11.856 58.128 11.88 58.32 ;
    END
  END rs
  PIN VDD
    DIRECTION INOUT ;
    USE POWER ;
    PORT
      LAYER M5 ;
        RECT  13.392 2.151 13.512 56.169 ;
        RECT  10.692 2.151 10.812 56.169 ;
        RECT  7.992 2.151 8.112 56.169 ;
        RECT  5.292 2.151 5.412 56.169 ;
        RECT  2.592 2.151 2.712 56.169 ;
    END
  END VDD
  PIN VSS
    DIRECTION INOUT ;
    USE GROUND ;
    PORT
      LAYER M5 ;
        RECT  13.2 2.137 13.32 56.183 ;
        RECT  10.5 2.137 10.62 56.183 ;
        RECT  7.8 2.137 7.92 56.183 ;
        RECT  5.1 2.137 5.22 56.183 ;
        RECT  2.4 2.137 2.52 56.183 ;
    END
  END VSS
  OBS
    LAYER RVTN ;
     RECT  2.16 2.16 15.12 2.295 ;
     RECT  2.16 2.565 15.12 2.835 ;
     RECT  2.16 3.105 15.12 3.375 ;
     RECT  2.16 3.645 15.12 3.915 ;
     RECT  2.16 4.185 15.12 4.455 ;
     RECT  2.16 4.725 15.12 4.995 ;
     RECT  2.16 5.265 15.12 5.535 ;
     RECT  2.16 5.805 15.12 6.075 ;
     RECT  2.16 6.345 15.12 6.615 ;
     RECT  2.16 6.885 15.12 7.155 ;
     RECT  2.16 7.425 15.12 7.695 ;
     RECT  2.16 7.965 15.12 8.235 ;
     RECT  2.16 8.505 15.12 8.775 ;
     RECT  2.16 9.045 15.12 9.315 ;
     RECT  2.16 9.585 15.12 9.855 ;
     RECT  2.16 10.125 15.12 10.395 ;
     RECT  2.16 10.665 15.12 10.935 ;
     RECT  2.16 11.205 15.12 11.475 ;
     RECT  2.16 11.745 15.12 12.015 ;
     RECT  2.16 12.285 15.12 12.555 ;
     RECT  2.16 12.825 15.12 13.095 ;
     RECT  2.16 13.365 15.12 13.635 ;
     RECT  2.16 13.905 15.12 14.175 ;
     RECT  2.16 14.445 15.12 14.715 ;
     RECT  2.16 14.985 15.12 15.255 ;
     RECT  2.16 15.525 15.12 15.795 ;
     RECT  2.16 16.065 15.12 16.335 ;
     RECT  2.16 16.605 15.12 16.875 ;
     RECT  2.16 17.145 15.12 17.415 ;
     RECT  2.16 17.685 15.12 17.955 ;
     RECT  2.16 18.225 15.12 18.495 ;
     RECT  2.16 18.765 15.12 19.035 ;
     RECT  2.16 19.305 15.12 19.575 ;
     RECT  2.16 19.845 15.12 20.115 ;
     RECT  2.16 20.385 15.12 20.655 ;
     RECT  2.16 20.925 15.12 21.195 ;
     RECT  2.16 21.465 15.12 21.735 ;
     RECT  2.16 22.005 15.12 22.275 ;
     RECT  2.16 22.545 15.12 22.815 ;
     RECT  2.16 23.085 15.12 23.355 ;
     RECT  2.16 23.625 15.12 23.895 ;
     RECT  2.16 24.165 15.12 24.435 ;
     RECT  2.16 24.705 15.12 24.975 ;
     RECT  2.16 25.245 15.12 25.515 ;
     RECT  2.16 25.785 15.12 26.055 ;
     RECT  2.16 26.325 15.12 26.595 ;
     RECT  2.16 26.865 15.12 27.135 ;
     RECT  2.16 27.405 15.12 27.675 ;
     RECT  2.16 27.945 15.12 28.215 ;
     RECT  2.16 28.485 15.12 28.755 ;
     RECT  2.16 29.025 15.12 29.295 ;
     RECT  2.16 29.565 15.12 29.835 ;
     RECT  2.16 30.105 15.12 30.375 ;
     RECT  2.16 30.645 15.12 30.915 ;
     RECT  2.16 31.185 15.12 31.455 ;
     RECT  2.16 31.725 15.12 31.995 ;
     RECT  2.16 32.265 15.12 32.535 ;
     RECT  2.16 32.805 15.12 33.075 ;
     RECT  2.16 33.345 15.12 33.615 ;
     RECT  2.16 33.885 15.12 34.155 ;
     RECT  2.16 34.425 15.12 34.695 ;
     RECT  2.16 34.965 15.12 35.235 ;
     RECT  2.16 35.505 15.12 35.775 ;
     RECT  2.16 36.045 15.12 36.315 ;
     RECT  2.16 36.585 15.12 36.855 ;
     RECT  2.16 37.125 15.12 37.395 ;
     RECT  2.16 37.665 15.12 37.935 ;
     RECT  2.16 38.205 15.12 38.475 ;
     RECT  2.16 38.745 15.12 39.015 ;
     RECT  2.16 39.285 15.12 39.555 ;
     RECT  2.16 39.825 15.12 40.095 ;
     RECT  2.16 40.365 15.12 40.635 ;
     RECT  2.16 40.905 15.12 41.175 ;
     RECT  2.16 41.445 15.12 41.715 ;
     RECT  2.16 41.985 15.12 42.255 ;
     RECT  2.16 42.525 15.12 42.795 ;
     RECT  2.16 43.065 15.12 43.335 ;
     RECT  2.16 43.605 15.12 43.875 ;
     RECT  2.16 44.145 15.12 44.415 ;
     RECT  2.16 44.685 15.12 44.955 ;
     RECT  2.16 45.225 15.12 45.495 ;
     RECT  2.16 45.765 15.12 46.035 ;
     RECT  2.16 46.305 15.12 46.575 ;
     RECT  2.16 46.845 15.12 47.115 ;
     RECT  2.16 47.385 15.12 47.655 ;
     RECT  2.16 47.925 15.12 48.195 ;
     RECT  2.16 48.465 15.12 48.735 ;
     RECT  2.16 49.005 15.12 49.275 ;
     RECT  2.16 49.545 15.12 49.815 ;
     RECT  2.16 50.085 15.12 50.355 ;
     RECT  2.16 50.625 15.12 50.895 ;
     RECT  2.16 51.165 15.12 51.435 ;
     RECT  2.16 51.705 15.12 51.975 ;
     RECT  2.16 52.245 15.12 52.515 ;
     RECT  2.16 52.785 15.12 53.055 ;
     RECT  2.16 53.325 15.12 53.595 ;
     RECT  2.16 53.865 15.12 54.135 ;
     RECT  2.16 54.405 15.12 54.675 ;
     RECT  2.16 54.945 15.12 55.215 ;
     RECT  2.16 55.485 15.12 55.755 ;
     RECT  2.16 56.025 15.12 56.16 ;
    LAYER RVTP ;
     RECT  2.16 2.295 15.12 2.565 ;
     RECT  2.16 2.835 15.12 3.105 ;
     RECT  2.16 3.375 15.12 3.645 ;
     RECT  2.16 3.915 15.12 4.185 ;
     RECT  2.16 4.455 15.12 4.725 ;
     RECT  2.16 4.995 15.12 5.265 ;
     RECT  2.16 5.535 15.12 5.805 ;
     RECT  2.16 6.075 15.12 6.345 ;
     RECT  2.16 6.615 15.12 6.885 ;
     RECT  2.16 7.155 15.12 7.425 ;
     RECT  2.16 7.695 15.12 7.965 ;
     RECT  2.16 8.235 15.12 8.505 ;
     RECT  2.16 8.775 15.12 9.045 ;
     RECT  2.16 9.315 15.12 9.585 ;
     RECT  2.16 9.855 15.12 10.125 ;
     RECT  2.16 10.395 15.12 10.665 ;
     RECT  2.16 10.935 15.12 11.205 ;
     RECT  2.16 11.475 15.12 11.745 ;
     RECT  2.16 12.015 15.12 12.285 ;
     RECT  2.16 12.555 15.12 12.825 ;
     RECT  2.16 13.095 15.12 13.365 ;
     RECT  2.16 13.635 15.12 13.905 ;
     RECT  2.16 14.175 15.12 14.445 ;
     RECT  2.16 14.715 15.12 14.985 ;
     RECT  2.16 15.255 15.12 15.525 ;
     RECT  2.16 15.795 15.12 16.065 ;
     RECT  2.16 16.335 15.12 16.605 ;
     RECT  2.16 16.875 15.12 17.145 ;
     RECT  2.16 17.415 15.12 17.685 ;
     RECT  2.16 17.955 15.12 18.225 ;
     RECT  2.16 18.495 15.12 18.765 ;
     RECT  2.16 19.035 15.12 19.305 ;
     RECT  2.16 19.575 15.12 19.845 ;
     RECT  2.16 20.115 15.12 20.385 ;
     RECT  2.16 20.655 15.12 20.925 ;
     RECT  2.16 21.195 15.12 21.465 ;
     RECT  2.16 21.735 15.12 22.005 ;
     RECT  2.16 22.275 15.12 22.545 ;
     RECT  2.16 22.815 15.12 23.085 ;
     RECT  2.16 23.355 15.12 23.625 ;
     RECT  2.16 23.895 15.12 24.165 ;
     RECT  2.16 24.435 15.12 24.705 ;
     RECT  2.16 24.975 15.12 25.245 ;
     RECT  2.16 25.515 15.12 25.785 ;
     RECT  2.16 26.055 15.12 26.325 ;
     RECT  2.16 26.595 15.12 26.865 ;
     RECT  2.16 27.135 15.12 27.405 ;
     RECT  2.16 27.675 15.12 27.945 ;
     RECT  2.16 28.215 15.12 28.485 ;
     RECT  2.16 28.755 15.12 29.025 ;
     RECT  2.16 29.295 15.12 29.565 ;
     RECT  2.16 29.835 15.12 30.105 ;
     RECT  2.16 30.375 15.12 30.645 ;
     RECT  2.16 30.915 15.12 31.185 ;
     RECT  2.16 31.455 15.12 31.725 ;
     RECT  2.16 31.995 15.12 32.265 ;
     RECT  2.16 32.535 15.12 32.805 ;
     RECT  2.16 33.075 15.12 33.345 ;
     RECT  2.16 33.615 15.12 33.885 ;
     RECT  2.16 34.155 15.12 34.425 ;
     RECT  2.16 34.695 15.12 34.965 ;
     RECT  2.16 35.235 15.12 35.505 ;
     RECT  2.16 35.775 15.12 36.045 ;
     RECT  2.16 36.315 15.12 36.585 ;
     RECT  2.16 36.855 15.12 37.125 ;
     RECT  2.16 37.395 15.12 37.665 ;
     RECT  2.16 37.935 15.12 38.205 ;
     RECT  2.16 38.475 15.12 38.745 ;
     RECT  2.16 39.015 15.12 39.285 ;
     RECT  2.16 39.555 15.12 39.825 ;
     RECT  2.16 40.095 15.12 40.365 ;
     RECT  2.16 40.635 15.12 40.905 ;
     RECT  2.16 41.175 15.12 41.445 ;
     RECT  2.16 41.715 15.12 41.985 ;
     RECT  2.16 42.255 15.12 42.525 ;
     RECT  2.16 42.795 15.12 43.065 ;
     RECT  2.16 43.335 15.12 43.605 ;
     RECT  2.16 43.875 15.12 44.145 ;
     RECT  2.16 44.415 15.12 44.685 ;
     RECT  2.16 44.955 15.12 45.225 ;
     RECT  2.16 45.495 15.12 45.765 ;
     RECT  2.16 46.035 15.12 46.305 ;
     RECT  2.16 46.575 15.12 46.845 ;
     RECT  2.16 47.115 15.12 47.385 ;
     RECT  2.16 47.655 15.12 47.925 ;
     RECT  2.16 48.195 15.12 48.465 ;
     RECT  2.16 48.735 15.12 49.005 ;
     RECT  2.16 49.275 15.12 49.545 ;
     RECT  2.16 49.815 15.12 50.085 ;
     RECT  2.16 50.355 15.12 50.625 ;
     RECT  2.16 50.895 15.12 51.165 ;
     RECT  2.16 51.435 15.12 51.705 ;
     RECT  2.16 51.975 15.12 52.245 ;
     RECT  2.16 52.515 15.12 52.785 ;
     RECT  2.16 53.055 15.12 53.325 ;
     RECT  2.16 53.595 15.12 53.865 ;
     RECT  2.16 54.135 15.12 54.405 ;
     RECT  2.16 54.675 15.12 54.945 ;
     RECT  2.16 55.215 15.12 55.485 ;
     RECT  2.16 55.755 15.12 56.025 ;
    LAYER M1 ;
     RECT  2.16 2.151 15.12 56.169 ;
    LAYER M2 ;
     RECT  0.211 5.616 0.311 5.634 ;
     RECT  0.211 14.526 0.311 14.544 ;
     RECT  0.211 23.328 0.311 23.58 ;
     RECT  0.211 24.948 0.311 25.704 ;
     RECT  0.211 26.991 0.311 27.009 ;
     RECT  0.211 30.771 0.311 30.789 ;
     RECT  0.211 34.632 0.311 34.65 ;
     RECT  0.211 39.096 0.311 39.114 ;
     RECT  0.211 40.716 0.311 40.734 ;
     RECT  0.211 44.226 0.311 45.054 ;
     RECT  0.211 54.261 0.311 54.279 ;
     RECT  0.311 24.948 0.347 25.236 ;
     RECT  0.247 56.106 0.347 56.124 ;
     RECT  0.347 25.218 0.383 25.236 ;
     RECT  0.211 2.538 0.463 2.556 ;
     RECT  0.463 2.538 0.535 2.592 ;
     RECT  0.535 42.732 0.571 42.75 ;
     RECT  0.535 8.442 0.635 8.532 ;
     RECT  0.211 33.048 1.111 33.066 ;
     RECT  0.535 2.106 2.16 2.592 ;
     RECT  0.535 6.822 2.16 6.84 ;
     RECT  0.211 7.596 2.16 7.614 ;
     RECT  0.635 8.514 2.16 8.532 ;
     RECT  0.211 13.032 2.16 13.05 ;
     RECT  0.211 16.956 2.16 16.974 ;
     RECT  0.211 18.504 2.16 18.522 ;
     RECT  0.535 27.918 2.16 27.936 ;
     RECT  1.111 33.048 2.16 33.444 ;
     RECT  2.155 35.982 2.16 36 ;
     RECT  0.571 42.732 2.16 43.128 ;
     RECT  0.311 44.226 2.16 44.244 ;
     RECT  0.535 49.554 2.16 49.572 ;
     RECT  0.535 53.406 2.16 53.424 ;
     RECT  2.16 2.106 4.495 56.169 ;
     RECT  4.495 2.07 6.763 56.214 ;
     RECT  6.763 2.07 6.835 56.25 ;
     RECT  6.835 2.07 7.231 56.394 ;
     RECT  7.231 2.034 7.951 56.394 ;
     RECT  7.951 1.998 8.311 56.394 ;
     RECT  8.311 1.926 9.491 56.394 ;
     RECT  9.491 2.034 9.959 56.394 ;
     RECT  9.959 2.034 12.263 56.322 ;
     RECT  12.263 2.034 13.027 56.169 ;
     RECT  13.027 2.034 13.055 56.214 ;
     RECT  13.055 2.106 13.927 56.214 ;
     RECT  13.927 1.962 15.431 56.214 ;
     RECT  15.431 1.962 15.467 29.592 ;
     RECT  15.431 30.384 15.467 56.214 ;
     RECT  15.467 2.268 15.503 29.592 ;
     RECT  15.467 30.456 15.503 56.214 ;
     RECT  15.503 2.268 16.007 2.286 ;
     RECT  15.503 3.186 16.007 29.592 ;
     RECT  15.503 31.392 16.007 56.214 ;
     RECT  16.007 12.996 16.043 16.164 ;
     RECT  16.007 32.976 16.043 40.392 ;
     RECT  16.007 53.802 16.043 55.674 ;
     RECT  16.007 48.636 16.475 52.848 ;
     RECT  16.007 3.276 16.511 6.84 ;
     RECT  16.043 13.068 16.511 16.164 ;
     RECT  16.007 17.046 16.511 23.346 ;
     RECT  16.007 24.102 16.511 29.592 ;
     RECT  15.503 30.456 16.511 30.564 ;
     RECT  16.007 31.392 16.511 31.914 ;
     RECT  16.043 39.096 16.511 40.392 ;
     RECT  16.007 41.382 16.511 47.844 ;
     RECT  16.475 48.636 16.511 48.996 ;
     RECT  16.475 49.752 16.511 52.848 ;
     RECT  16.043 53.802 16.511 54.324 ;
     RECT  16.043 55.188 16.511 55.674 ;
     RECT  16.511 3.276 16.547 3.87 ;
     RECT  16.511 4.734 16.547 6.84 ;
     RECT  16.007 7.632 16.547 7.65 ;
     RECT  16.007 8.712 16.547 12.24 ;
     RECT  16.511 13.068 16.547 13.734 ;
     RECT  16.511 14.994 16.547 16.164 ;
     RECT  16.511 17.964 16.547 23.346 ;
     RECT  16.511 24.516 16.547 27.504 ;
     RECT  16.511 28.458 16.547 29.592 ;
     RECT  16.511 30.456 16.547 30.474 ;
     RECT  16.511 31.536 16.547 31.824 ;
     RECT  16.043 32.976 16.547 38.304 ;
     RECT  16.511 39.096 16.547 39.204 ;
     RECT  16.511 40.374 16.547 40.392 ;
     RECT  16.511 41.382 16.547 44.748 ;
     RECT  16.511 45.666 16.547 47.178 ;
     RECT  16.511 48.744 16.547 48.996 ;
     RECT  16.511 49.752 16.547 52.002 ;
     RECT  16.511 52.758 16.547 52.848 ;
     RECT  16.511 53.802 16.547 53.82 ;
     RECT  16.511 55.188 16.547 55.206 ;
     RECT  16.547 5.85 16.583 5.868 ;
     RECT  16.547 9.396 16.583 9.846 ;
     RECT  16.547 11.214 16.583 12.24 ;
     RECT  16.547 13.266 16.583 13.734 ;
     RECT  16.547 15.876 16.583 15.894 ;
     RECT  16.547 20.7 16.583 20.916 ;
     RECT  16.547 25.326 16.583 25.344 ;
     RECT  16.547 28.728 16.583 28.746 ;
     RECT  16.547 31.626 16.583 31.824 ;
     RECT  16.547 34.938 16.583 34.956 ;
     RECT  16.547 36.288 16.583 36.882 ;
     RECT  16.547 46.314 16.583 46.404 ;
     RECT  16.547 52.758 16.583 52.776 ;
     RECT  16.547 3.42 16.619 3.438 ;
     RECT  16.583 11.376 16.619 12.24 ;
     RECT  16.547 19.584 16.619 19.602 ;
     RECT  16.583 20.7 16.619 20.718 ;
     RECT  16.583 31.806 16.619 31.824 ;
     RECT  16.547 37.98 16.619 38.232 ;
     RECT  16.547 42.696 16.619 42.714 ;
     RECT  16.583 46.386 16.619 46.404 ;
     RECT  16.619 38.214 16.655 38.232 ;
     RECT  16.619 11.376 17.087 11.97 ;
    LAYER M3 ;
     RECT  8.316 1.921 8.334 1.993 ;
     RECT  9.468 1.921 9.486 1.993 ;
     RECT  7.956 1.993 9.486 2.029 ;
     RECT  13.932 1.957 13.95 2.029 ;
     RECT  15.444 1.957 15.462 2.029 ;
     RECT  10.836 2.065 10.854 2.101 ;
     RECT  13.032 2.029 13.05 2.101 ;
     RECT  13.932 2.029 14.49 2.101 ;
     RECT  2.628 2.101 2.826 2.143 ;
     RECT  4.5 2.065 4.518 2.143 ;
     RECT  10.764 2.101 10.854 2.143 ;
     RECT  13.032 2.101 13.158 2.143 ;
     RECT  13.932 2.101 14.562 2.143 ;
     RECT  2.415 2.143 2.826 2.203 ;
     RECT  6.12 2.101 6.138 2.219 ;
     RECT  13.032 2.143 14.562 2.255 ;
     RECT  2.304 2.203 2.826 2.263 ;
     RECT  15.408 2.029 15.462 2.263 ;
     RECT  4.5 2.143 5.205 2.299 ;
     RECT  7.236 2.029 9.486 2.299 ;
     RECT  4.068 2.299 5.205 2.335 ;
     RECT  15.408 2.263 16.002 2.381 ;
     RECT  0.54 2.101 0.558 2.443 ;
     RECT  10.515 2.143 10.854 2.497 ;
     RECT  0.216 2.443 0.558 2.561 ;
     RECT  10.515 2.497 11.394 2.569 ;
     RECT  2.304 2.263 3.222 2.587 ;
     RECT  4.068 2.335 6.102 2.587 ;
     RECT  10.224 2.569 12.006 2.759 ;
     RECT  13.032 2.255 14.526 2.759 ;
     RECT  14.508 2.759 14.526 2.795 ;
     RECT  6.84 2.299 9.486 2.839 ;
     RECT  10.224 2.759 10.797 2.839 ;
     RECT  0.252 2.561 0.558 2.909 ;
     RECT  13.032 2.759 13.59 2.911 ;
     RECT  0.252 2.909 0.486 3.005 ;
     RECT  2.304 2.587 6.102 3.037 ;
     RECT  6.84 2.839 10.797 3.037 ;
     RECT  15.408 2.381 15.498 3.163 ;
     RECT  15.408 3.163 16.002 3.209 ;
     RECT  16.488 3.259 16.542 3.415 ;
     RECT  16.488 3.415 16.614 3.533 ;
     RECT  11.664 2.759 11.682 3.541 ;
     RECT  12.528 2.911 13.59 3.541 ;
     RECT  11.664 3.541 13.59 3.641 ;
     RECT  2.304 3.037 10.797 3.749 ;
     RECT  14.544 3.541 14.562 3.749 ;
     RECT  2.304 3.749 9.774 3.875 ;
     RECT  11.952 3.641 13.59 3.965 ;
     RECT  11.988 3.965 13.59 4.117 ;
     RECT  11.988 4.117 14.13 4.157 ;
     RECT  11.988 4.157 13.497 4.217 ;
     RECT  10.515 3.749 10.797 4.225 ;
     RECT  15.408 3.209 15.462 4.261 ;
     RECT  16.488 3.533 16.542 4.261 ;
     RECT  15.408 4.261 16.542 4.445 ;
     RECT  10.515 4.225 10.926 4.487 ;
     RECT  15.408 4.445 15.462 4.729 ;
     RECT  2.304 3.875 9.702 4.843 ;
     RECT  12.708 4.217 13.497 4.939 ;
     RECT  12.528 4.939 13.497 5.027 ;
     RECT  2.268 4.843 9.702 5.035 ;
     RECT  10.515 4.487 10.854 5.035 ;
     RECT  2.268 5.035 10.854 5.063 ;
     RECT  14.796 4.729 15.462 5.161 ;
     RECT  2.304 5.063 10.854 5.189 ;
     RECT  12.672 5.027 13.497 5.213 ;
     RECT  12.924 5.213 13.497 5.233 ;
     RECT  3.852 5.189 10.854 5.269 ;
     RECT  3.852 5.269 11.394 5.333 ;
     RECT  10.515 5.333 11.394 5.549 ;
     RECT  0.252 3.005 0.27 5.596 ;
     RECT  14.364 5.161 15.462 5.803 ;
     RECT  16.488 4.445 16.542 5.803 ;
     RECT  14.364 5.803 16.542 5.843 ;
     RECT  16.488 5.843 16.542 5.845 ;
     RECT  12.924 5.233 13.59 5.881 ;
     RECT  14.364 5.843 15.426 5.881 ;
     RECT  0.216 5.596 0.306 5.885 ;
     RECT  0.216 5.885 0.27 5.933 ;
     RECT  3.852 5.333 9.774 6.035 ;
     RECT  2.304 5.189 3.078 6.079 ;
     RECT  3.852 6.035 9.702 6.079 ;
     RECT  16.488 5.845 16.578 6.125 ;
     RECT  10.515 5.549 11.07 6.385 ;
     RECT  2.304 6.079 9.702 6.413 ;
     RECT  12.924 5.881 15.426 6.511 ;
     RECT  2.304 6.413 9.666 6.523 ;
     RECT  10.515 6.385 11.502 6.539 ;
     RECT  12.816 6.511 15.426 6.557 ;
     RECT  2.268 6.523 9.666 6.575 ;
     RECT  13.032 6.557 15.426 6.619 ;
     RECT  16.488 6.125 16.542 6.619 ;
     RECT  13.032 6.619 16.542 6.809 ;
     RECT  0.252 5.933 0.27 6.817 ;
     RECT  2.304 6.575 9.666 6.845 ;
     RECT  0.252 6.817 0.558 6.893 ;
     RECT  13.032 6.809 14.058 7.501 ;
     RECT  0.252 6.893 0.27 7.579 ;
     RECT  10.515 6.539 10.797 7.591 ;
     RECT  12.888 7.501 14.058 7.591 ;
     RECT  14.832 6.809 16.542 7.591 ;
     RECT  0.216 7.579 0.27 7.619 ;
     RECT  3.816 6.845 9.666 7.627 ;
     RECT  10.515 7.591 10.854 7.627 ;
     RECT  12.816 7.591 16.542 7.655 ;
     RECT  2.304 6.845 2.898 7.735 ;
     RECT  3.816 7.627 10.854 7.735 ;
     RECT  2.304 7.735 10.854 7.771 ;
     RECT  2.304 7.771 11.538 7.889 ;
     RECT  12.816 7.655 16.002 7.889 ;
     RECT  0.252 7.619 0.27 7.949 ;
     RECT  2.304 7.889 11.43 7.997 ;
     RECT  3.96 7.997 11.43 8.24 ;
     RECT  0.324 7.963 0.342 8.437 ;
     RECT  0.324 8.437 0.63 8.525 ;
     RECT  0.324 8.525 0.558 8.573 ;
     RECT  3.96 8.24 10.854 8.573 ;
     RECT  14.22 7.889 16.002 8.635 ;
     RECT  14.22 8.635 16.542 8.699 ;
     RECT  2.304 7.997 3.222 8.815 ;
     RECT  3.96 8.573 9.342 8.815 ;
     RECT  2.304 8.815 9.342 8.909 ;
     RECT  0.324 8.573 0.414 8.971 ;
     RECT  13.032 7.889 13.497 8.971 ;
     RECT  0.288 8.971 0.414 9.005 ;
     RECT  13.032 8.971 13.698 9.005 ;
     RECT  2.376 8.909 9.342 9.041 ;
     RECT  10.224 8.573 10.854 9.041 ;
     RECT  13.104 9.005 13.698 9.053 ;
     RECT  11.952 8.971 11.97 9.077 ;
     RECT  0.288 9.005 0.306 9.101 ;
     RECT  14.616 8.699 16.542 9.259 ;
     RECT  2.415 9.041 9.342 9.275 ;
     RECT  10.224 9.041 10.797 9.319 ;
     RECT  13.215 9.053 13.698 9.481 ;
     RECT  12.312 9.355 12.33 9.509 ;
     RECT  14.616 9.259 16.578 9.617 ;
     RECT  3.996 9.275 9.342 9.625 ;
     RECT  10.116 9.319 10.797 9.625 ;
     RECT  13.215 9.481 13.878 9.751 ;
     RECT  14.616 9.617 14.634 9.751 ;
     RECT  13.215 9.751 14.634 9.787 ;
     RECT  15.408 9.617 16.578 9.851 ;
     RECT  3.996 9.625 10.797 9.859 ;
     RECT  15.408 9.851 16.542 9.917 ;
     RECT  3.996 9.859 10.854 9.931 ;
     RECT  13.104 9.787 14.634 10.049 ;
     RECT  2.415 9.275 3.258 10.219 ;
     RECT  2.304 10.219 3.258 10.315 ;
     RECT  3.996 9.931 10.998 10.315 ;
     RECT  13.215 10.049 14.634 10.319 ;
     RECT  2.304 10.315 10.998 10.399 ;
     RECT  11.916 10.201 11.934 10.399 ;
     RECT  0.252 9.163 0.27 10.411 ;
     RECT  14.436 10.319 14.634 10.411 ;
     RECT  15.408 9.917 15.462 10.411 ;
     RECT  0.252 10.411 0.342 10.603 ;
     RECT  14.436 10.411 15.462 10.637 ;
     RECT  0.252 10.603 0.414 10.733 ;
     RECT  14.724 10.637 15.462 10.747 ;
     RECT  16.524 9.917 16.542 10.747 ;
     RECT  0.396 10.733 0.414 10.781 ;
     RECT  14.724 10.747 16.542 10.859 ;
     RECT  16.524 10.859 16.542 10.939 ;
     RECT  2.304 10.399 11.934 11.011 ;
     RECT  13.215 10.319 13.518 11.011 ;
     RECT  2.304 11.011 13.518 11.101 ;
     RECT  16.524 10.939 16.578 11.371 ;
     RECT  2.304 11.101 13.842 11.399 ;
     RECT  11.7 11.399 13.842 11.543 ;
     RECT  14.724 10.859 15.462 11.611 ;
     RECT  14.688 11.611 15.462 11.668 ;
     RECT  11.988 11.543 13.842 11.677 ;
     RECT  14.652 11.668 15.462 11.677 ;
     RECT  0.252 11.467 0.27 11.741 ;
     RECT  11.988 11.677 15.462 11.939 ;
     RECT  11.988 11.939 14.526 11.981 ;
     RECT  16.524 11.371 17.082 12.029 ;
     RECT  2.304 11.399 10.797 12.083 ;
     RECT  15.408 11.939 15.462 12.091 ;
     RECT  16.524 12.029 16.614 12.091 ;
     RECT  11.988 11.981 12.006 12.289 ;
     RECT  2.304 12.083 5.49 12.361 ;
     RECT  2.268 12.361 5.49 12.461 ;
     RECT  11.628 12.289 12.006 12.479 ;
     RECT  12.888 11.981 14.526 12.515 ;
     RECT  15.408 12.091 16.614 12.557 ;
     RECT  11.988 12.479 12.006 12.659 ;
     RECT  2.304 12.461 5.49 12.829 ;
     RECT  0.252 12.811 0.27 12.989 ;
     RECT  12.888 12.515 14.13 13.019 ;
     RECT  6.444 12.083 10.797 13.099 ;
     RECT  2.304 12.829 5.598 13.135 ;
     RECT  6.408 13.099 10.797 13.135 ;
     RECT  0.216 13.027 0.234 13.229 ;
     RECT  15.408 12.557 16.578 13.325 ;
     RECT  2.304 13.135 10.797 13.531 ;
     RECT  15.408 13.325 15.426 13.531 ;
     RECT  2.304 13.531 10.926 13.801 ;
     RECT  13.104 13.019 13.626 13.801 ;
     RECT  2.304 13.801 11.358 13.829 ;
     RECT  12.888 13.801 13.77 13.853 ;
     RECT  3.996 13.829 11.358 13.901 ;
     RECT  16.488 13.325 16.578 13.949 ;
     RECT  14.76 13.531 15.426 14.071 ;
     RECT  14.508 14.071 15.426 14.141 ;
     RECT  12.888 13.853 13.662 14.207 ;
     RECT  0.252 14.251 0.27 14.395 ;
     RECT  3.996 13.901 10.797 14.441 ;
     RECT  0.252 14.395 0.378 14.521 ;
     RECT  13.215 14.207 13.662 14.635 ;
     RECT  14.868 14.141 15.426 14.635 ;
     RECT  10.515 14.441 10.797 14.647 ;
     RECT  0.216 14.521 0.378 14.717 ;
     RECT  16.488 13.949 16.506 14.731 ;
     RECT  2.304 13.829 3.078 14.755 ;
     RECT  0.288 14.717 0.378 14.765 ;
     RECT  0.36 14.765 0.378 14.813 ;
     RECT  14.868 14.635 15.462 14.875 ;
     RECT  13.215 14.635 13.698 14.881 ;
     RECT  14.832 14.875 15.462 14.915 ;
     RECT  2.304 14.755 3.258 14.917 ;
     RECT  3.996 14.441 9.666 14.917 ;
     RECT  13.215 14.881 13.95 14.917 ;
     RECT  12.348 14.791 12.366 14.971 ;
     RECT  13.215 14.917 14.31 14.971 ;
     RECT  10.515 14.647 11.214 15.016 ;
     RECT  10.515 15.016 11.43 15.053 ;
     RECT  12.348 14.971 14.31 15.059 ;
     RECT  15.408 14.915 15.462 15.163 ;
     RECT  16.488 14.731 16.542 15.163 ;
     RECT  2.304 14.917 9.666 15.295 ;
     RECT  10.515 15.053 10.797 15.295 ;
     RECT  12.276 15.061 12.294 15.323 ;
     RECT  15.408 15.163 16.542 15.499 ;
     RECT  13.104 15.059 14.31 15.691 ;
     RECT  15.408 15.499 16.578 15.691 ;
     RECT  13.104 15.691 16.578 15.899 ;
     RECT  0.252 15.787 0.27 15.979 ;
     RECT  2.304 15.295 10.797 16.027 ;
     RECT  12.06 16.075 12.078 16.123 ;
     RECT  13.104 15.899 16.542 16.169 ;
     RECT  11.988 16.123 12.078 16.363 ;
     RECT  13.104 16.169 16.002 16.363 ;
     RECT  11.988 16.363 16.002 16.439 ;
     RECT  0.252 15.979 0.342 16.493 ;
     RECT  11.988 16.439 14.67 16.529 ;
     RECT  2.304 16.027 10.818 16.795 ;
     RECT  2.304 16.795 11.43 16.829 ;
     RECT  4.14 16.829 11.43 16.871 ;
     RECT  15.408 16.439 16.002 16.939 ;
     RECT  0.252 16.493 0.27 16.951 ;
     RECT  12.348 16.529 14.67 17.069 ;
     RECT  0.216 16.951 0.27 17.117 ;
     RECT  4.14 16.871 10.89 17.165 ;
     RECT  6.372 17.165 10.89 17.249 ;
     RECT  15.408 16.939 16.506 17.383 ;
     RECT  14.832 17.383 16.506 17.447 ;
     RECT  2.304 16.829 3.366 17.609 ;
     RECT  6.408 17.249 10.89 17.611 ;
     RECT  4.14 17.165 5.634 17.617 ;
     RECT  0.396 17.515 0.414 17.645 ;
     RECT  6.408 17.611 11.43 17.681 ;
     RECT  12.492 17.069 14.058 17.899 ;
     RECT  12.024 17.899 14.058 17.947 ;
     RECT  14.832 17.447 15.462 17.947 ;
     RECT  16.488 17.447 16.506 17.959 ;
     RECT  3.996 17.617 5.634 18.031 ;
     RECT  6.408 17.681 11.25 18.031 ;
     RECT  0.252 17.899 0.27 18.077 ;
     RECT  3.996 18.031 11.25 18.149 ;
     RECT  12.024 17.947 15.462 18.221 ;
     RECT  0.216 18.499 0.234 18.605 ;
     RECT  2.304 17.609 3.222 18.697 ;
     RECT  3.996 18.149 10.926 18.697 ;
     RECT  12.492 18.221 15.462 18.697 ;
     RECT  2.304 18.697 10.926 18.761 ;
     RECT  2.304 18.761 10.854 18.797 ;
     RECT  6.192 18.797 10.854 18.995 ;
     RECT  12.492 18.697 15.498 18.995 ;
     RECT  0.252 18.907 0.27 19.003 ;
     RECT  12.888 18.995 15.498 19.031 ;
     RECT  12.096 19.075 12.114 19.111 ;
     RECT  12.024 19.111 12.114 19.229 ;
     RECT  10.515 18.995 10.854 19.301 ;
     RECT  14.796 19.031 15.498 19.301 ;
     RECT  12.888 19.031 13.878 19.373 ;
     RECT  14.832 19.301 15.498 19.387 ;
     RECT  16.488 17.959 16.542 19.387 ;
     RECT  2.304 18.797 5.397 19.531 ;
     RECT  6.192 18.995 9.45 19.531 ;
     RECT  12.888 19.373 13.626 19.571 ;
     RECT  14.832 19.387 16.542 19.579 ;
     RECT  14.832 19.579 16.614 19.679 ;
     RECT  16.488 19.679 16.614 19.709 ;
     RECT  2.304 19.531 9.45 19.741 ;
     RECT  12.996 19.571 13.554 19.769 ;
     RECT  0.252 19.003 0.342 19.901 ;
     RECT  2.304 19.741 9.738 20.011 ;
     RECT  10.515 19.301 10.797 20.011 ;
     RECT  11.988 20.059 12.006 20.111 ;
     RECT  2.304 20.011 10.797 20.147 ;
     RECT  5.115 20.147 10.797 20.155 ;
     RECT  12.168 20.119 12.258 20.219 ;
     RECT  5.115 20.155 11.106 20.395 ;
     RECT  0.252 19.901 0.27 20.429 ;
     RECT  12.24 20.219 12.258 20.489 ;
     RECT  12.996 19.769 13.497 20.551 ;
     RECT  14.832 19.679 15.426 20.551 ;
     RECT  2.304 20.147 4.302 20.615 ;
     RECT  16.488 19.709 16.542 20.635 ;
     RECT  12.564 20.551 13.497 20.695 ;
     RECT  16.488 20.635 16.578 20.695 ;
     RECT  12.564 20.695 13.734 20.731 ;
     RECT  14.724 20.551 15.426 20.849 ;
     RECT  4.104 20.615 4.302 20.893 ;
     RECT  5.115 20.395 11.214 20.893 ;
     RECT  14.724 20.849 14.85 20.909 ;
     RECT  12.564 20.731 13.806 20.965 ;
     RECT  16.488 20.695 16.614 21.005 ;
     RECT  16.488 21.005 16.542 21.091 ;
     RECT  4.104 20.893 11.214 21.211 ;
     RECT  4.104 21.211 11.286 21.263 ;
     RECT  2.304 20.615 3.33 21.397 ;
     RECT  4.104 21.263 9.702 21.397 ;
     RECT  12.564 20.965 14.562 21.403 ;
     RECT  0.252 21.163 0.27 21.437 ;
     RECT  15.984 21.091 16.542 21.595 ;
     RECT  12.024 21.403 14.562 21.659 ;
     RECT  10.515 21.263 11.286 21.787 ;
     RECT  2.304 21.397 9.702 21.803 ;
     RECT  12.888 21.659 14.562 21.883 ;
     RECT  15.408 21.595 16.542 21.883 ;
     RECT  10.515 21.787 12.006 21.929 ;
     RECT  2.304 21.803 9.666 22.081 ;
     RECT  10.515 21.929 11.43 22.109 ;
     RECT  2.268 22.081 9.666 22.307 ;
     RECT  12.888 21.883 16.542 22.379 ;
     RECT  10.515 22.109 11.142 22.469 ;
     RECT  2.304 22.307 9.666 22.747 ;
     RECT  12.888 22.379 13.986 22.747 ;
     RECT  12.744 22.747 13.986 22.855 ;
     RECT  2.304 22.747 9.774 22.891 ;
     RECT  10.515 22.469 10.797 22.891 ;
     RECT  2.304 22.891 10.797 23.009 ;
     RECT  12.456 22.855 13.986 23.117 ;
     RECT  14.724 22.379 16.542 23.161 ;
     RECT  0.216 23.227 0.234 23.275 ;
     RECT  12.456 23.117 13.59 23.279 ;
     RECT  14.364 23.161 16.542 23.351 ;
     RECT  14.796 23.351 16.002 23.423 ;
     RECT  0.216 23.275 0.306 23.851 ;
     RECT  0.216 23.851 0.594 23.885 ;
     RECT  2.304 23.009 2.826 23.947 ;
     RECT  3.636 23.009 10.797 23.947 ;
     RECT  0.288 23.885 0.594 23.981 ;
     RECT  14.832 23.423 16.002 24.029 ;
     RECT  12.924 23.279 13.497 24.061 ;
     RECT  2.304 23.947 10.854 24.197 ;
     RECT  2.304 24.197 10.797 24.269 ;
     RECT  2.304 24.269 5.562 24.283 ;
     RECT  14.832 24.029 15.426 24.331 ;
     RECT  2.232 24.283 5.562 24.359 ;
     RECT  16.488 24.088 16.506 24.427 ;
     RECT  14.472 24.331 15.426 24.431 ;
     RECT  2.304 24.359 5.562 24.467 ;
     RECT  12.924 24.061 13.662 24.511 ;
     RECT  12.924 24.511 13.734 24.667 ;
     RECT  12.924 24.667 13.842 24.781 ;
     RECT  12.492 24.781 13.842 24.899 ;
     RECT  0.288 23.981 0.414 24.907 ;
     RECT  0.216 24.907 0.414 24.941 ;
     RECT  16.488 24.427 16.542 24.955 ;
     RECT  4.14 24.467 5.562 25.051 ;
     RECT  6.3 24.269 10.797 25.051 ;
     RECT  4.14 25.051 10.797 25.141 ;
     RECT  13.212 24.899 13.497 25.181 ;
     RECT  0.216 24.941 0.378 25.277 ;
     RECT  16.488 24.955 16.578 25.349 ;
     RECT  14.832 24.431 15.426 25.411 ;
     RECT  16.488 25.349 16.542 25.411 ;
     RECT  12.456 25.321 12.474 25.435 ;
     RECT  11.952 25.435 12.474 25.475 ;
     RECT  14.796 25.411 16.542 25.483 ;
     RECT  14.724 25.483 16.542 25.517 ;
     RECT  2.304 24.467 3.402 25.555 ;
     RECT  4.14 25.141 10.926 25.555 ;
     RECT  2.304 25.555 10.926 25.613 ;
     RECT  14.724 25.517 15.426 25.619 ;
     RECT  16.488 25.517 16.542 25.979 ;
     RECT  3.42 25.613 10.926 25.987 ;
     RECT  13.215 25.181 13.497 25.987 ;
     RECT  0.216 25.277 0.306 25.997 ;
     RECT  13.215 25.987 13.95 26.059 ;
     RECT  3.42 25.987 10.998 26.299 ;
     RECT  3.42 26.299 11.322 26.401 ;
     RECT  0.288 25.997 0.306 26.491 ;
     RECT  2.304 25.613 2.697 26.599 ;
     RECT  3.42 26.401 11.718 26.599 ;
     RECT  12.528 26.059 14.022 26.599 ;
     RECT  14.832 25.619 15.426 26.599 ;
     RECT  0.288 26.491 0.414 26.621 ;
     RECT  12.528 26.599 15.426 26.627 ;
     RECT  2.304 26.599 11.718 26.635 ;
     RECT  13.104 26.627 15.426 26.669 ;
     RECT  2.304 26.635 12.006 26.825 ;
     RECT  0.288 26.621 0.342 26.827 ;
     RECT  0.252 26.827 0.342 26.986 ;
     RECT  15.408 26.669 15.426 27.061 ;
     RECT  16.524 25.979 16.542 27.163 ;
     RECT  2.415 26.825 12.006 27.203 ;
     RECT  4.14 27.203 12.006 27.239 ;
     RECT  0.216 26.986 0.342 27.245 ;
     RECT  11.988 27.239 12.006 27.329 ;
     RECT  2.415 27.203 3.402 27.547 ;
     RECT  13.104 26.669 14.598 27.571 ;
     RECT  15.408 27.061 15.462 27.571 ;
     RECT  13.104 27.571 15.462 27.595 ;
     RECT  0.252 27.245 0.342 27.677 ;
     RECT  0.324 27.677 0.342 27.869 ;
     RECT  12.06 27.409 12.078 27.869 ;
     RECT  12.816 27.595 15.462 27.869 ;
     RECT  14.652 27.869 15.462 27.905 ;
     RECT  12.816 27.869 13.497 27.949 ;
     RECT  0.54 27.913 0.558 27.965 ;
     RECT  2.304 27.547 3.402 27.985 ;
     RECT  4.14 27.239 10.797 27.985 ;
     RECT  14.832 27.905 15.462 28.183 ;
     RECT  16.488 27.163 16.542 28.183 ;
     RECT  14.832 28.183 16.542 28.349 ;
     RECT  12.384 27.949 13.497 28.409 ;
     RECT  2.304 27.985 10.797 28.561 ;
     RECT  12.456 28.409 13.497 28.651 ;
     RECT  16.524 28.349 16.542 28.651 ;
     RECT  16.524 28.651 16.578 28.751 ;
     RECT  2.304 28.561 10.926 28.949 ;
     RECT  3.96 28.949 10.926 28.973 ;
     RECT  10.116 28.973 10.926 29.021 ;
     RECT  10.116 29.021 10.818 29.093 ;
     RECT  12.456 28.651 13.518 29.101 ;
     RECT  14.832 28.349 15.426 29.263 ;
     RECT  0.252 29.131 0.27 29.275 ;
     RECT  12.456 29.101 13.554 29.371 ;
     RECT  14.832 29.263 15.462 29.405 ;
     RECT  0.252 29.275 0.306 29.453 ;
     RECT  16.524 28.751 16.542 29.597 ;
     RECT  12.456 29.371 13.626 29.605 ;
     RECT  12.24 29.605 13.626 29.641 ;
     RECT  12.24 29.641 13.842 29.731 ;
     RECT  11.916 29.731 13.842 29.803 ;
     RECT  3.96 28.973 9.342 29.899 ;
     RECT  11.916 29.803 14.058 29.939 ;
     RECT  3.96 29.899 9.378 29.992 ;
     RECT  3.96 29.992 9.486 30.125 ;
     RECT  11.916 29.939 13.986 30.137 ;
     RECT  14.832 29.405 15.426 30.235 ;
     RECT  0.252 29.453 0.27 30.283 ;
     RECT  5.076 30.125 9.486 30.307 ;
     RECT  10.515 29.093 10.818 30.307 ;
     RECT  0.252 30.283 0.414 30.413 ;
     RECT  2.304 28.949 3.222 30.415 ;
     RECT  3.96 30.125 4.194 30.415 ;
     RECT  5.076 30.307 10.998 30.451 ;
     RECT  11.916 30.137 13.806 30.451 ;
     RECT  16.524 30.427 16.542 30.523 ;
     RECT  16.488 30.523 16.542 30.569 ;
     RECT  1.152 30.571 1.278 30.619 ;
     RECT  2.304 30.415 4.194 30.641 ;
     RECT  1.152 30.619 1.458 30.701 ;
     RECT  1.26 30.701 1.458 30.749 ;
     RECT  0.252 30.413 0.306 30.766 ;
     RECT  1.26 30.749 1.278 30.797 ;
     RECT  14.832 30.235 15.462 30.883 ;
     RECT  2.304 30.641 2.862 30.907 ;
     RECT  5.076 30.451 13.806 30.955 ;
     RECT  0.216 30.766 0.306 30.989 ;
     RECT  3.708 30.641 4.194 30.991 ;
     RECT  5.076 30.955 13.878 30.991 ;
     RECT  0.216 30.989 0.234 31.037 ;
     RECT  2.196 30.907 2.862 31.145 ;
     RECT  3.708 30.991 13.878 31.217 ;
     RECT  10.515 31.217 13.878 31.351 ;
     RECT  16.524 30.569 16.542 31.387 ;
     RECT  10.515 31.351 14.094 31.423 ;
     RECT  14.832 30.883 15.498 31.423 ;
     RECT  10.515 31.423 15.498 31.483 ;
     RECT  16.488 31.387 16.542 31.483 ;
     RECT  2.304 31.145 2.862 31.495 ;
     RECT  3.708 31.217 9.738 31.495 ;
     RECT  10.515 31.483 16.542 31.559 ;
     RECT  11.952 31.559 16.542 31.579 ;
     RECT  11.952 31.579 16.578 31.649 ;
     RECT  11.988 31.649 16.578 31.801 ;
     RECT  11.988 31.801 16.614 31.829 ;
     RECT  12.24 31.829 16.614 31.949 ;
     RECT  10.515 31.559 11.214 32.189 ;
     RECT  12.24 31.949 16.002 32.237 ;
     RECT  2.304 31.495 9.738 32.467 ;
     RECT  10.515 32.189 10.962 32.467 ;
     RECT  12.24 32.237 14.85 32.765 ;
     RECT  15.984 32.237 16.002 32.837 ;
     RECT  12.24 32.765 13.626 32.845 ;
     RECT  14.364 32.765 14.85 32.971 ;
     RECT  2.304 32.467 10.962 33.007 ;
     RECT  2.196 33.007 10.962 33.053 ;
     RECT  11.808 32.845 13.626 33.071 ;
     RECT  2.304 33.053 10.962 33.143 ;
     RECT  0.216 33.043 0.234 33.149 ;
     RECT  10.515 33.143 10.962 33.421 ;
     RECT  11.808 33.071 13.497 33.421 ;
     RECT  10.515 33.421 13.497 33.575 ;
     RECT  2.304 33.143 9.738 33.629 ;
     RECT  1.116 33.421 1.134 33.677 ;
     RECT  0.252 33.211 0.27 33.835 ;
     RECT  10.515 33.575 11.394 33.881 ;
     RECT  14.364 32.971 15.426 33.925 ;
     RECT  0.252 33.835 0.342 34.013 ;
     RECT  12.708 33.575 13.497 34.075 ;
     RECT  14.292 33.925 15.426 34.075 ;
     RECT  12.708 34.075 15.426 34.079 ;
     RECT  2.304 33.629 9.666 34.115 ;
     RECT  13.215 34.079 15.426 34.151 ;
     RECT  16.488 32.971 16.542 34.231 ;
     RECT  2.412 34.115 9.666 34.385 ;
     RECT  0.252 34.013 0.306 34.603 ;
     RECT  2.415 34.385 9.666 34.627 ;
     RECT  10.515 33.881 10.854 34.627 ;
     RECT  0.216 34.603 0.306 34.655 ;
     RECT  2.415 34.627 10.854 34.733 ;
     RECT  11.7 34.465 11.79 34.735 ;
     RECT  15.984 34.231 16.542 34.772 ;
     RECT  0.252 34.655 0.306 34.795 ;
     RECT  10.515 34.733 10.854 34.795 ;
     RECT  11.7 34.735 11.97 34.795 ;
     RECT  16.488 34.772 16.542 34.843 ;
     RECT  16.488 34.843 16.578 34.961 ;
     RECT  10.515 34.795 11.97 34.997 ;
     RECT  10.515 34.997 11.43 35.021 ;
     RECT  2.415 34.733 9.702 35.131 ;
     RECT  12.348 35.041 12.366 35.159 ;
     RECT  16.488 34.961 16.542 35.159 ;
     RECT  13.215 34.151 14.85 35.179 ;
     RECT  13.215 35.179 15.426 35.267 ;
     RECT  0.252 34.795 0.342 35.309 ;
     RECT  0.324 35.309 0.342 35.501 ;
     RECT  2.304 35.131 9.702 35.659 ;
     RECT  13.215 35.267 14.022 35.671 ;
     RECT  12.888 35.671 14.022 35.699 ;
     RECT  2.268 35.659 9.702 35.743 ;
     RECT  10.515 35.021 10.962 35.743 ;
     RECT  12.888 35.699 13.497 35.941 ;
     RECT  2.268 35.743 10.962 35.947 ;
     RECT  14.832 35.267 15.426 35.995 ;
     RECT  2.16 35.947 10.962 36.005 ;
     RECT  16.524 35.159 16.542 36.076 ;
     RECT  2.412 36.005 10.962 36.085 ;
     RECT  12.672 35.941 13.497 36.121 ;
     RECT  11.952 36.121 13.497 36.239 ;
     RECT  16.524 36.076 16.578 36.331 ;
     RECT  2.412 36.085 11.106 36.391 ;
     RECT  14.832 35.995 15.462 36.517 ;
     RECT  16.488 36.331 16.578 36.517 ;
     RECT  14.58 36.517 16.578 36.553 ;
     RECT  14.22 36.553 16.578 36.689 ;
     RECT  14.544 36.689 16.578 36.893 ;
     RECT  12.168 36.239 13.497 36.895 ;
     RECT  2.412 36.391 11.358 37.049 ;
     RECT  12.168 36.895 13.77 37.085 ;
     RECT  16.524 36.893 16.578 37.085 ;
     RECT  2.412 37.049 3.258 37.243 ;
     RECT  4.104 37.049 11.358 37.339 ;
     RECT  0.252 36.043 0.27 37.387 ;
     RECT  14.832 36.893 15.462 37.391 ;
     RECT  4.104 37.339 11.43 37.427 ;
     RECT  6.444 37.427 11.43 37.471 ;
     RECT  12.168 37.085 13.497 37.471 ;
     RECT  15.408 37.391 15.462 37.517 ;
     RECT  0.252 37.387 0.342 37.565 ;
     RECT  6.444 37.471 13.497 37.613 ;
     RECT  0.252 37.565 0.27 37.901 ;
     RECT  16.524 37.085 16.542 37.915 ;
     RECT  13.215 37.613 13.497 37.963 ;
     RECT  4.104 37.427 5.706 37.975 ;
     RECT  16.524 37.915 16.578 37.975 ;
     RECT  2.304 37.243 3.258 38.137 ;
     RECT  4.068 37.975 5.706 38.137 ;
     RECT  2.304 38.137 5.706 38.189 ;
     RECT  16.524 37.975 16.614 38.209 ;
     RECT  3.636 38.189 5.706 38.281 ;
     RECT  6.444 37.613 12.474 38.281 ;
     RECT  13.215 37.963 13.986 38.281 ;
     RECT  1.152 38.155 1.17 38.333 ;
     RECT  16.524 38.209 16.65 38.381 ;
     RECT  13.215 38.281 14.058 38.399 ;
     RECT  3.636 38.281 12.474 38.443 ;
     RECT  13.215 38.399 13.497 38.443 ;
     RECT  15.408 37.517 15.426 38.539 ;
     RECT  16.524 38.381 16.542 38.539 ;
     RECT  14.256 38.551 14.418 38.621 ;
     RECT  14.256 38.621 14.346 38.669 ;
     RECT  0.288 38.779 0.306 38.827 ;
     RECT  3.636 38.443 13.497 38.939 ;
     RECT  0.216 38.827 0.306 38.971 ;
     RECT  0.216 38.971 0.342 39.119 ;
     RECT  11.736 38.939 13.497 39.119 ;
     RECT  12.168 39.119 13.497 39.245 ;
     RECT  15.408 38.539 16.542 39.281 ;
     RECT  16.488 39.281 16.542 39.293 ;
     RECT  2.304 38.189 2.79 39.325 ;
     RECT  2.304 39.325 2.826 39.355 ;
     RECT  3.636 38.939 10.962 39.355 ;
     RECT  2.304 39.355 10.962 39.451 ;
     RECT  15.408 39.281 15.462 39.451 ;
     RECT  12.276 39.245 13.497 39.479 ;
     RECT  2.268 39.451 10.962 39.515 ;
     RECT  14.724 39.451 15.462 39.551 ;
     RECT  14.724 39.551 14.886 39.559 ;
     RECT  2.304 39.515 10.962 39.587 ;
     RECT  2.412 39.587 10.962 39.632 ;
     RECT  14.328 39.559 14.886 39.659 ;
     RECT  2.412 39.632 10.926 39.749 ;
     RECT  12.276 39.479 12.474 39.749 ;
     RECT  2.412 39.749 9.486 39.821 ;
     RECT  10.44 39.749 10.926 39.857 ;
     RECT  2.415 39.821 9.486 39.917 ;
     RECT  12.276 39.749 12.366 40.019 ;
     RECT  3.96 39.917 9.486 40.055 ;
     RECT  0.252 39.119 0.342 40.061 ;
     RECT  13.215 39.479 13.497 40.261 ;
     RECT  16.488 39.293 16.506 40.315 ;
     RECT  10.515 39.857 10.926 40.397 ;
     RECT  16.488 40.315 16.542 40.397 ;
     RECT  12.348 40.019 12.366 40.433 ;
     RECT  4.068 40.055 9.486 40.507 ;
     RECT  4.068 40.507 9.666 40.559 ;
     RECT  13.14 40.261 13.497 40.567 ;
     RECT  4.068 40.559 9.594 40.595 ;
     RECT  13.14 40.567 13.95 40.639 ;
     RECT  14.832 39.659 14.886 40.651 ;
     RECT  15.984 40.411 16.002 40.651 ;
     RECT  12.924 40.639 13.95 40.667 ;
     RECT  14.832 40.651 16.002 40.667 ;
     RECT  0.252 40.061 0.306 40.711 ;
     RECT  0.216 40.711 0.306 40.877 ;
     RECT  14.832 40.667 15.462 40.901 ;
     RECT  0.288 40.877 0.306 40.925 ;
     RECT  2.415 39.917 3.222 40.945 ;
     RECT  4.068 40.595 9.522 40.945 ;
     RECT  2.415 40.945 9.522 41.035 ;
     RECT  10.515 40.397 10.797 41.083 ;
     RECT  11.952 40.945 11.97 41.099 ;
     RECT  10.404 41.083 10.797 41.135 ;
     RECT  12.924 40.667 13.497 41.251 ;
     RECT  2.304 41.035 9.522 41.341 ;
     RECT  14.832 40.901 15.426 41.405 ;
     RECT  12.528 41.251 13.497 41.453 ;
     RECT  14.832 41.405 14.886 41.549 ;
     RECT  2.304 41.341 9.666 41.611 ;
     RECT  16.524 41.275 16.542 41.611 ;
     RECT  16.488 41.611 16.542 41.707 ;
     RECT  2.304 41.611 9.774 41.989 ;
     RECT  10.515 41.135 10.797 41.989 ;
     RECT  12.672 41.453 13.497 42.061 ;
     RECT  14.832 41.549 14.85 42.061 ;
     RECT  12.672 42.061 14.85 42.089 ;
     RECT  0.252 41.707 0.27 42.125 ;
     RECT  2.304 41.989 10.797 42.151 ;
     RECT  2.304 42.151 10.854 42.215 ;
     RECT  15.984 41.707 16.542 42.269 ;
     RECT  4.032 42.215 10.854 42.331 ;
     RECT  4.032 42.331 11.178 42.449 ;
     RECT  12.672 42.089 14.13 42.565 ;
     RECT  12.564 42.565 14.13 42.605 ;
     RECT  16.488 42.269 16.542 42.691 ;
     RECT  15.408 42.427 15.462 42.755 ;
     RECT  16.488 42.691 16.614 42.797 ;
     RECT  0.54 42.619 0.594 42.845 ;
     RECT  12.636 42.605 14.13 42.871 ;
     RECT  12.636 42.871 14.454 42.955 ;
     RECT  15.408 42.755 15.426 42.955 ;
     RECT  12.636 42.955 15.426 42.989 ;
     RECT  0.576 42.845 0.594 43.133 ;
     RECT  2.304 42.215 3.258 43.141 ;
     RECT  4.032 42.449 10.926 43.141 ;
     RECT  14.292 42.989 15.426 43.259 ;
     RECT  12.636 42.989 13.554 43.799 ;
     RECT  14.616 43.259 15.426 43.799 ;
     RECT  2.268 43.141 10.926 43.807 ;
     RECT  16.488 42.797 16.542 44.069 ;
     RECT  2.268 43.807 11.394 44.155 ;
     RECT  12.636 43.799 13.497 44.221 ;
     RECT  2.268 44.155 11.43 44.333 ;
     RECT  2.304 44.333 11.43 44.339 ;
     RECT  12.384 44.221 13.497 44.339 ;
     RECT  0.216 44.203 0.234 44.38 ;
     RECT  2.304 44.339 11.394 44.429 ;
     RECT  2.304 44.429 11.322 44.609 ;
     RECT  14.832 43.799 15.426 44.653 ;
     RECT  2.304 44.609 11.142 44.753 ;
     RECT  16.524 44.069 16.542 44.851 ;
     RECT  13.104 44.339 13.497 44.875 ;
     RECT  13.104 44.875 13.626 44.951 ;
     RECT  2.304 44.753 11.07 44.987 ;
     RECT  14.508 44.653 15.426 45.067 ;
     RECT  16.488 44.851 16.542 45.067 ;
     RECT  14.508 45.067 16.542 45.157 ;
     RECT  0.216 44.38 0.306 45.197 ;
     RECT  14.328 45.157 16.542 45.197 ;
     RECT  0.288 45.197 0.306 45.245 ;
     RECT  14.328 45.197 14.85 45.257 ;
     RECT  14.4 45.257 14.85 45.329 ;
     RECT  14.4 45.329 14.418 45.419 ;
     RECT  2.304 44.987 11.034 45.527 ;
     RECT  2.304 45.527 10.854 45.563 ;
     RECT  15.984 45.197 16.542 46.027 ;
     RECT  13.104 44.951 13.497 46.075 ;
     RECT  15.984 46.027 16.578 46.123 ;
     RECT  10.515 45.563 10.854 46.345 ;
     RECT  2.304 45.563 9.774 46.363 ;
     RECT  10.515 46.345 11.394 46.363 ;
     RECT  15.984 46.123 16.614 46.409 ;
     RECT  12.78 46.075 13.497 46.471 ;
     RECT  14.832 46.219 14.85 46.543 ;
     RECT  15.984 46.409 16.542 46.543 ;
     RECT  2.304 46.363 11.394 46.589 ;
     RECT  12.78 46.471 14.094 46.741 ;
     RECT  14.832 46.543 16.542 46.741 ;
     RECT  12.78 46.741 16.542 46.769 ;
     RECT  12.78 46.769 15.498 46.84 ;
     RECT  12.564 46.84 15.498 46.921 ;
     RECT  2.304 46.589 11.178 46.949 ;
     RECT  11.952 46.921 15.498 47.039 ;
     RECT  11.952 47.039 12.366 47.069 ;
     RECT  16.488 46.769 16.542 47.213 ;
     RECT  13.104 47.039 15.498 47.219 ;
     RECT  0.252 47.083 0.27 47.419 ;
     RECT  2.304 46.949 10.818 47.425 ;
     RECT  2.268 47.425 10.818 47.501 ;
     RECT  0.252 47.419 0.306 47.563 ;
     RECT  0.252 47.563 0.414 47.693 ;
     RECT  2.304 47.501 10.818 47.707 ;
     RECT  2.304 47.707 11.43 47.849 ;
     RECT  13.215 47.219 15.498 47.885 ;
     RECT  12.276 47.069 12.366 47.929 ;
     RECT  11.772 47.929 12.366 48.199 ;
     RECT  14.832 47.885 15.498 48.331 ;
     RECT  16.488 47.213 16.506 48.331 ;
     RECT  11.772 48.199 12.474 48.361 ;
     RECT  13.215 47.885 13.554 48.361 ;
     RECT  11.772 48.361 13.554 48.389 ;
     RECT  14.832 48.331 16.506 48.461 ;
     RECT  16.452 48.461 16.506 48.619 ;
     RECT  14.832 48.461 15.426 48.631 ;
     RECT  2.304 47.849 10.797 48.715 ;
     RECT  16.452 48.619 16.542 49.001 ;
     RECT  12.276 48.389 13.554 49.081 ;
     RECT  14.544 48.631 15.426 49.081 ;
     RECT  2.304 48.715 11.394 49.147 ;
     RECT  12.276 49.081 15.426 49.279 ;
     RECT  16.452 49.001 16.47 49.279 ;
     RECT  2.268 49.147 11.394 49.307 ;
     RECT  12.276 49.279 16.47 49.307 ;
     RECT  2.304 49.307 11.394 49.469 ;
     RECT  12.276 49.307 13.497 49.513 ;
     RECT  14.256 49.307 16.47 49.541 ;
     RECT  0.252 47.693 0.342 49.549 ;
     RECT  0.252 49.549 0.558 49.613 ;
     RECT  0.252 49.613 0.27 49.709 ;
     RECT  14.652 49.541 16.47 49.709 ;
     RECT  2.304 49.469 11.142 49.775 ;
     RECT  3.996 49.775 11.142 50.009 ;
     RECT  11.916 49.513 13.497 50.009 ;
     RECT  3.996 50.009 10.797 50.045 ;
     RECT  11.916 50.009 12.186 50.081 ;
     RECT  13.215 50.009 13.497 50.161 ;
     RECT  5.076 50.045 10.797 50.189 ;
     RECT  12.168 50.081 12.186 50.279 ;
     RECT  14.652 49.709 15.426 50.279 ;
     RECT  2.304 49.775 3.258 50.299 ;
     RECT  2.196 50.299 3.258 50.387 ;
     RECT  14.832 50.279 15.426 50.443 ;
     RECT  14.832 50.443 15.462 50.549 ;
     RECT  6.12 50.189 10.797 50.729 ;
     RECT  2.304 50.387 3.258 50.827 ;
     RECT  3.996 50.045 4.194 50.827 ;
     RECT  2.304 50.827 4.194 50.899 ;
     RECT  5.076 50.189 5.397 50.899 ;
     RECT  13.215 50.161 13.698 50.935 ;
     RECT  2.304 50.899 5.397 50.971 ;
     RECT  6.12 50.729 6.462 50.971 ;
     RECT  12.96 50.935 13.698 50.971 ;
     RECT  7.272 50.729 9.738 51.089 ;
     RECT  11.628 50.971 11.646 51.089 ;
     RECT  0.252 50.923 0.27 51.115 ;
     RECT  10.515 50.729 10.797 51.133 ;
     RECT  12.528 50.971 14.058 51.161 ;
     RECT  10.515 51.133 11.394 51.197 ;
     RECT  12.996 51.161 14.058 51.205 ;
     RECT  14.832 50.549 15.426 51.205 ;
     RECT  12.996 51.205 15.426 51.389 ;
     RECT  2.304 50.971 6.462 51.511 ;
     RECT  7.272 51.089 9.702 51.511 ;
     RECT  12.24 51.439 12.258 51.629 ;
     RECT  12.996 51.389 13.842 51.629 ;
     RECT  14.616 51.389 15.426 51.691 ;
     RECT  16.524 49.747 16.542 51.691 ;
     RECT  0.252 51.115 0.342 51.821 ;
     RECT  2.304 51.511 9.702 51.835 ;
     RECT  2.304 51.835 9.738 51.907 ;
     RECT  10.515 51.197 10.797 51.907 ;
     RECT  14.616 51.691 16.542 52.007 ;
     RECT  2.304 51.907 10.797 52.171 ;
     RECT  2.304 52.171 11.394 52.205 ;
     RECT  13.14 51.629 13.842 52.519 ;
     RECT  12.816 52.519 13.842 52.681 ;
     RECT  14.616 52.007 16.506 52.681 ;
     RECT  6.12 52.205 11.394 52.699 ;
     RECT  12.816 52.681 16.506 52.747 ;
     RECT  12.816 52.747 16.542 52.753 ;
     RECT  1.152 51.643 1.17 52.781 ;
     RECT  2.304 52.205 3.258 52.861 ;
     RECT  2.268 52.861 3.258 52.973 ;
     RECT  3.996 52.205 5.397 53.059 ;
     RECT  6.12 52.699 11.97 53.059 ;
     RECT  2.304 52.973 3.258 53.095 ;
     RECT  3.996 53.059 11.97 53.095 ;
     RECT  12.816 52.753 16.578 53.213 ;
     RECT  0.252 51.821 0.27 53.401 ;
     RECT  12.816 53.213 16.542 53.429 ;
     RECT  0.252 53.401 0.558 53.501 ;
     RECT  2.304 53.095 11.97 53.599 ;
     RECT  2.304 53.599 12.006 53.635 ;
     RECT  12.816 53.429 13.554 53.635 ;
     RECT  2.304 53.635 13.554 53.789 ;
     RECT  14.328 53.429 16.542 53.825 ;
     RECT  2.304 53.789 10.797 53.861 ;
     RECT  11.628 53.789 13.554 54.211 ;
     RECT  14.328 53.825 16.506 54.211 ;
     RECT  0.252 53.501 0.27 54.256 ;
     RECT  0.216 54.256 0.306 54.365 ;
     RECT  0.288 54.365 0.306 54.413 ;
     RECT  11.628 54.211 16.506 54.653 ;
     RECT  2.304 53.861 3.258 54.671 ;
     RECT  11.628 54.653 12.006 54.679 ;
     RECT  11.52 54.679 12.006 54.869 ;
     RECT  12.888 54.653 16.506 54.955 ;
     RECT  12.888 54.955 16.542 55.139 ;
     RECT  0.432 55.051 0.45 55.147 ;
     RECT  14.616 55.139 16.542 55.175 ;
     RECT  0.288 55.147 0.45 55.181 ;
     RECT  12.888 55.139 13.878 55.181 ;
     RECT  14.832 55.175 16.542 55.211 ;
     RECT  11.772 54.869 12.006 55.229 ;
     RECT  3.996 53.861 10.797 55.291 ;
     RECT  12.888 55.181 13.59 55.531 ;
     RECT  2.304 54.671 3.222 55.553 ;
     RECT  0.288 55.181 0.378 55.579 ;
     RECT  12.564 55.531 13.59 55.589 ;
     RECT  2.415 55.553 3.222 55.651 ;
     RECT  3.996 55.291 10.854 55.651 ;
     RECT  14.832 55.211 16.506 55.679 ;
     RECT  2.415 55.651 10.854 55.787 ;
     RECT  6.156 55.787 10.854 55.823 ;
     RECT  6.408 55.823 10.854 55.901 ;
     RECT  2.415 55.787 5.397 55.907 ;
     RECT  13.032 55.589 13.59 55.907 ;
     RECT  0.252 55.579 0.378 55.915 ;
     RECT  11.772 55.229 11.79 55.949 ;
     RECT  14.832 55.679 16.002 55.957 ;
     RECT  2.415 55.907 5.205 55.985 ;
     RECT  6.408 55.901 8.19 55.985 ;
     RECT  14.076 55.957 16.002 55.997 ;
     RECT  0.252 55.915 0.414 56.011 ;
     RECT  4.032 55.985 5.205 56.021 ;
     RECT  8.928 55.901 10.854 56.021 ;
     RECT  0.216 56.011 0.414 56.045 ;
     RECT  2.415 55.985 3.294 56.045 ;
     RECT  14.832 55.997 16.002 56.045 ;
     RECT  8.964 56.021 10.854 56.093 ;
     RECT  0.216 56.045 0.342 56.129 ;
     RECT  14.076 55.997 14.094 56.129 ;
     RECT  14.832 56.045 14.922 56.129 ;
     RECT  0.216 56.129 0.27 56.141 ;
     RECT  14.832 56.129 14.85 56.141 ;
     RECT  2.415 56.045 2.505 56.177 ;
     RECT  4.5 56.021 5.205 56.177 ;
     RECT  8.964 56.093 10.605 56.177 ;
     RECT  13.032 55.907 13.305 56.177 ;
     RECT  4.5 56.177 4.518 56.219 ;
     RECT  12.06 56.101 12.258 56.219 ;
     RECT  13.032 56.177 13.05 56.219 ;
     RECT  15.984 56.045 16.002 56.219 ;
     RECT  6.768 55.985 8.19 56.255 ;
     RECT  8.964 56.177 10.386 56.255 ;
     RECT  0.216 56.141 0.234 56.285 ;
     RECT  3.276 56.045 3.294 56.285 ;
     RECT  8.964 56.255 10.17 56.291 ;
     RECT  7.776 56.255 8.19 56.327 ;
     RECT  12.24 56.219 12.258 56.327 ;
     RECT  8.172 56.327 8.19 56.363 ;
     RECT  9.504 56.291 9.954 56.363 ;
     RECT  6.84 56.255 6.858 56.399 ;
     RECT  9.936 56.363 9.954 56.399 ;
     RECT  5.4 57.595 5.418 58.188 ;
    LAYER M4 ;
     RECT  0.156 2.208 0.205 56.136 ;
     RECT  0.205 2.208 2.408 56.28 ;
     RECT  2.408 2.148 2.512 56.28 ;
     RECT  2.512 2.418 2.704 56.28 ;
     RECT  2.704 2.496 3.305 56.28 ;
     RECT  3.305 2.496 5.108 56.088 ;
     RECT  5.108 2.148 5.212 56.172 ;
     RECT  5.212 2.418 5.404 56.088 ;
     RECT  5.389 57.6 6.371 57.624 ;
     RECT  5.404 2.496 7.808 56.088 ;
     RECT  7.808 2.148 7.912 56.172 ;
     RECT  7.912 2.418 8.104 56.088 ;
     RECT  8.104 2.544 8.813 56.088 ;
     RECT  8.813 2.832 9.281 56.088 ;
     RECT  9.281 2.88 9.389 56.088 ;
     RECT  9.389 2.88 10.508 56.04 ;
     RECT  10.508 2.148 10.612 56.172 ;
     RECT  10.612 2.418 10.804 55.902 ;
     RECT  10.804 2.88 10.973 39.624 ;
     RECT  10.804 41.088 11.153 49.896 ;
     RECT  10.804 51.12 11.761 55.902 ;
     RECT  11.761 51.12 11.891 55.944 ;
     RECT  11.153 41.088 11.945 49.848 ;
     RECT  10.973 2.88 12.017 39.24 ;
     RECT  12.017 31.872 12.197 39.24 ;
     RECT  12.017 2.88 13.208 30.6 ;
     RECT  12.197 31.872 13.208 38.712 ;
     RECT  11.945 41.088 13.208 49.752 ;
     RECT  11.891 51.12 13.208 55.896 ;
     RECT  13.208 2.148 13.312 56.172 ;
     RECT  13.312 2.418 13.504 55.902 ;
     RECT  13.504 42.288 13.565 42.792 ;
     RECT  13.504 44.88 13.637 44.904 ;
     RECT  13.504 8.976 13.673 10.632 ;
     RECT  13.504 21.456 13.673 24.696 ;
     RECT  13.504 12.96 13.709 14.664 ;
     RECT  13.504 34.08 13.709 35.256 ;
     RECT  13.709 12.96 13.781 14.136 ;
     RECT  13.504 16.656 13.781 19.368 ;
     RECT  13.673 24.672 13.781 24.696 ;
     RECT  13.504 27.264 13.781 27.48 ;
     RECT  13.709 34.368 13.781 35.256 ;
     RECT  13.673 9.504 13.889 10.632 ;
     RECT  13.504 6 13.997 6.84 ;
     RECT  13.504 37.968 13.997 38.616 ;
     RECT  13.504 4.128 14.141 4.152 ;
     RECT  13.781 16.656 14.321 16.68 ;
     RECT  13.997 38.592 14.429 38.616 ;
     RECT  13.504 55.152 14.497 55.176 ;
     RECT  14.497 54.768 14.533 55.176 ;
     RECT  13.504 51.36 14.641 52.056 ;
     RECT  14.677 11.616 14.749 11.64 ;
     RECT  13.997 6.432 14.821 6.84 ;
     RECT  13.889 10.128 14.821 10.632 ;
     RECT  14.749 11.616 14.821 11.928 ;
     RECT  13.781 12.96 14.821 12.984 ;
     RECT  13.781 14.112 14.821 14.136 ;
     RECT  14.569 16.224 14.821 16.248 ;
     RECT  13.781 17.952 14.821 19.368 ;
     RECT  13.673 21.456 14.821 23.304 ;
     RECT  13.504 26.064 14.821 26.088 ;
     RECT  13.781 27.264 14.821 27.288 ;
     RECT  13.504 32.352 14.821 32.904 ;
     RECT  13.781 34.416 14.821 35.256 ;
     RECT  13.504 36.864 14.821 36.888 ;
     RECT  13.565 42.288 14.821 42.312 ;
     RECT  14.605 43.68 14.821 43.704 ;
     RECT  13.504 46.608 14.821 46.632 ;
     RECT  13.504 47.856 14.821 49.224 ;
     RECT  14.641 50.208 14.821 50.232 ;
     RECT  14.641 51.36 14.821 52.248 ;
     RECT  13.504 53.28 14.821 53.304 ;
     RECT  14.533 54.768 14.821 55.992 ;
     RECT  14.821 32.112 14.857 33.192 ;
     RECT  14.821 34.224 14.857 37.176 ;
     RECT  13.504 2.544 15.397 2.568 ;
     RECT  14.821 4.752 15.397 4.776 ;
     RECT  14.821 6.432 15.397 8.76 ;
     RECT  14.821 10.128 15.397 11.928 ;
     RECT  14.821 12.96 15.397 14.904 ;
     RECT  14.821 16.128 15.397 16.248 ;
     RECT  14.821 17.472 15.397 30.888 ;
     RECT  14.857 32.112 15.397 37.176 ;
     RECT  14.821 39.6 15.397 56.136 ;
     RECT  15.397 2.208 17.1 56.136 ;
    LAYER M5 ;
     RECT  2.4 2.137 2.52 2.151 ;
     RECT  5.1 2.137 5.22 2.151 ;
     RECT  7.8 2.137 7.92 2.151 ;
     RECT  10.5 2.137 10.62 2.151 ;
     RECT  13.2 2.137 13.32 2.151 ;
     RECT  7.8 2.151 8.112 2.821 ;
     RECT  2.4 2.151 2.712 3.397 ;
     RECT  2.4 3.397 3.288 4.115 ;
     RECT  5.1 2.151 5.412 6.085 ;
     RECT  5.1 6.085 5.736 7.237 ;
     RECT  5.1 7.237 6.696 7.715 ;
     RECT  5.1 7.715 5.544 7.957 ;
     RECT  2.4 4.115 2.712 8.725 ;
     RECT  4.992 7.957 5.544 8.819 ;
     RECT  2.304 8.725 2.712 8.915 ;
     RECT  2.4 8.915 2.712 9.061 ;
     RECT  0.192 8.917 0.216 9.107 ;
     RECT  5.1 8.819 5.544 9.107 ;
     RECT  2.4 9.061 3.24 9.925 ;
     RECT  7.8 2.821 8.616 10.741 ;
     RECT  5.1 9.107 5.412 11.749 ;
     RECT  2.4 9.925 3.336 12.035 ;
     RECT  6.672 7.715 6.696 12.613 ;
     RECT  7.8 10.741 8.712 12.613 ;
     RECT  5.1 11.749 5.544 13.045 ;
     RECT  6.672 12.613 8.712 13.045 ;
     RECT  4.992 13.045 5.544 13.091 ;
     RECT  6.672 13.045 9.144 13.139 ;
     RECT  4.992 13.091 5.412 13.715 ;
     RECT  7.8 13.139 9.144 14.197 ;
     RECT  7.8 14.197 9.288 14.723 ;
     RECT  7.8 14.723 8.28 15.251 ;
     RECT  5.1 13.715 5.412 17.029 ;
     RECT  0.288 17.461 0.312 17.651 ;
     RECT  5.1 17.029 5.688 18.133 ;
     RECT  6.672 13.139 6.696 18.133 ;
     RECT  5.1 18.133 6.696 18.467 ;
     RECT  5.1 18.467 6.504 20.149 ;
     RECT  7.8 15.251 8.112 20.149 ;
     RECT  9.264 14.723 9.288 20.149 ;
     RECT  7.8 20.149 9.288 20.387 ;
     RECT  5.1 20.149 6.696 20.435 ;
     RECT  7.8 20.387 8.232 21.539 ;
     RECT  2.4 12.035 2.712 22.501 ;
     RECT  2.304 22.501 2.712 22.549 ;
     RECT  2.304 22.549 3.288 22.739 ;
     RECT  9.264 20.387 9.288 22.835 ;
     RECT  7.8 21.539 8.112 23.509 ;
     RECT  2.4 22.739 3.288 23.987 ;
     RECT  5.1 20.435 6.504 24.563 ;
     RECT  5.1 24.563 6.168 26.629 ;
     RECT  9.312 23.125 9.336 26.773 ;
     RECT  9.312 26.773 9.48 26.963 ;
     RECT  4.992 26.629 6.168 27.347 ;
     RECT  7.68 23.509 8.112 27.395 ;
     RECT  7.8 27.395 8.112 27.781 ;
     RECT  9.312 26.963 9.432 27.781 ;
     RECT  7.8 27.781 9.432 27.827 ;
     RECT  10.5 2.151 10.812 28.645 ;
     RECT  9.888 28.645 10.812 28.979 ;
     RECT  5.1 27.347 6.168 29.653 ;
     RECT  0.288 30.373 0.312 30.613 ;
     RECT  0.288 30.613 1.176 30.659 ;
     RECT  7.8 27.827 8.664 30.659 ;
     RECT  1.152 30.659 1.176 30.803 ;
     RECT  2.4 23.987 2.712 30.805 ;
     RECT  2.304 30.805 2.712 30.947 ;
     RECT  16.992 30.757 17.016 30.947 ;
     RECT  2.4 30.947 2.712 31.141 ;
     RECT  2.4 31.141 2.904 31.811 ;
     RECT  2.4 31.811 2.712 32.197 ;
     RECT  2.304 32.197 2.712 33.059 ;
     RECT  5.1 29.653 6.36 34.789 ;
     RECT  2.4 33.059 2.712 35.797 ;
     RECT  2.256 35.797 2.712 35.987 ;
     RECT  2.4 35.987 2.712 38.149 ;
     RECT  5.1 34.789 6.456 38.149 ;
     RECT  7.8 30.659 8.328 38.149 ;
     RECT  2.256 38.149 3.192 38.291 ;
     RECT  2.4 38.291 3.192 38.725 ;
     RECT  7.8 38.149 9.288 39.395 ;
     RECT  5.1 38.149 6.648 39.443 ;
     RECT  2.4 38.725 3.576 39.491 ;
     RECT  2.4 39.491 3.432 40.595 ;
     RECT  5.1 39.443 6.456 40.933 ;
     RECT  7.8 39.395 9.24 40.933 ;
     RECT  5.1 40.933 9.24 41.603 ;
     RECT  7.8 41.603 9.24 42.275 ;
     RECT  5.1 41.603 6.456 42.565 ;
     RECT  7.8 42.275 8.328 42.803 ;
     RECT  2.4 40.595 2.712 43.429 ;
     RECT  4.8 42.565 6.456 43.859 ;
     RECT  2.304 43.429 2.712 43.955 ;
     RECT  7.8 42.803 8.112 44.197 ;
     RECT  5.1 43.859 6.456 44.677 ;
     RECT  2.4 43.955 2.712 46.741 ;
     RECT  2.4 46.741 3.048 47.315 ;
     RECT  7.8 44.197 9 48.325 ;
     RECT  7.8 48.325 9.096 48.563 ;
     RECT  2.4 47.315 2.712 49.525 ;
     RECT  3.696 49.429 3.72 49.525 ;
     RECT  2.4 49.525 3.72 49.571 ;
     RECT  7.8 48.563 9 49.717 ;
     RECT  10.5 28.979 10.812 49.717 ;
     RECT  7.8 49.717 10.812 49.907 ;
     RECT  2.4 49.571 3.624 50.197 ;
     RECT  2.304 50.197 3.624 50.339 ;
     RECT  2.4 50.339 3.624 51.635 ;
     RECT  7.8 49.907 9 51.635 ;
     RECT  2.4 51.635 3.288 52.739 ;
     RECT  5.1 44.677 6.552 52.933 ;
     RECT  5.1 52.933 6.744 53.317 ;
     RECT  7.8 51.635 8.568 53.317 ;
     RECT  5.1 53.317 8.568 53.603 ;
     RECT  10.5 49.907 10.812 53.653 ;
     RECT  7.8 53.603 8.568 54.179 ;
     RECT  5.1 53.603 6.792 54.659 ;
     RECT  2.4 52.739 2.712 54.709 ;
     RECT  2.304 54.709 2.712 54.947 ;
     RECT  10.5 53.653 11.304 55.907 ;
     RECT  2.4 54.947 2.712 56.169 ;
     RECT  5.1 54.659 6.36 56.169 ;
     RECT  7.8 54.179 8.112 56.169 ;
     RECT  10.5 55.907 10.812 56.169 ;
     RECT  13.2 2.151 13.512 56.169 ;
     RECT  2.4 56.169 2.52 56.183 ;
     RECT  5.1 56.169 5.22 56.183 ;
     RECT  7.8 56.169 7.92 56.183 ;
     RECT  10.5 56.169 10.62 56.183 ;
     RECT  13.2 56.169 13.32 56.183 ;
     RECT  6.336 56.169 6.36 57.635 ;
     RECT  11.856 55.909 11.88 58.192 ;
  END
END dsfd_dvrly_512_WE
END LIBRARY
